VERSION 5.8 ;
BUSBITCHARS "[]" ;
DIVIDERCHAR "/" ;
UNITS
    DATABASE MICRONS 1000 ;
END UNITS

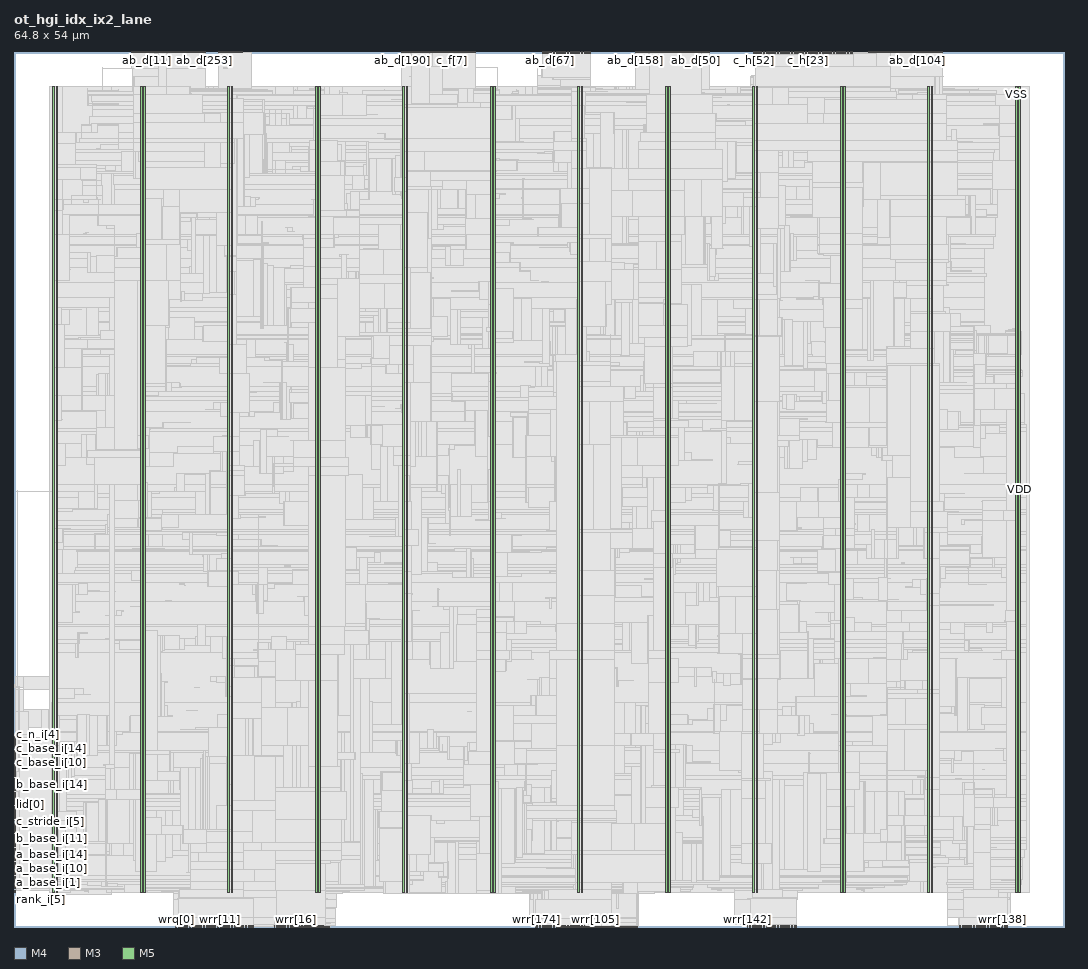
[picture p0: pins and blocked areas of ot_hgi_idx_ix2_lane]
MACRO ot_hgi_idx_ix2_lane
  FOREIGN ot_hgi_idx_ix2_lane 0 0 ;
  CLASS BLOCK ;
  SIZE 64.8 BY 54 ;
  PIN a_base_i[0]
    DIRECTION INPUT ;
    USE SIGNAL ;
    PORT
      LAYER M4 ;
        RECT  0 2.64 0.084 2.664 ;
    END
  END a_base_i[0]
  PIN a_base_i[10]
    DIRECTION INPUT ;
    USE SIGNAL ;
    PORT
      LAYER M4 ;
        RECT  0 3.6 0.084 3.624 ;
    END
  END a_base_i[10]
  PIN a_base_i[11]
    DIRECTION INPUT ;
    USE SIGNAL ;
    PORT
      LAYER M4 ;
        RECT  0 3.696 0.084 3.72 ;
    END
  END a_base_i[11]
  PIN a_base_i[12]
    DIRECTION INPUT ;
    USE SIGNAL ;
    PORT
      LAYER M4 ;
        RECT  0 3.792 0.084 3.816 ;
    END
  END a_base_i[12]
  PIN a_base_i[13]
    DIRECTION INPUT ;
    USE SIGNAL ;
    PORT
      LAYER M4 ;
        RECT  0 3.888 0.084 3.912 ;
    END
  END a_base_i[13]
  PIN a_base_i[14]
    DIRECTION INPUT ;
    USE SIGNAL ;
    PORT
      LAYER M4 ;
        RECT  0 3.984 0.084 4.008 ;
    END
  END a_base_i[14]
  PIN a_base_i[15]
    DIRECTION INPUT ;
    USE SIGNAL ;
    PORT
      LAYER M4 ;
        RECT  0 4.08 0.084 4.104 ;
    END
  END a_base_i[15]
  PIN a_base_i[16]
    DIRECTION INPUT ;
    USE SIGNAL ;
    PORT
      LAYER M4 ;
        RECT  0 4.176 0.084 4.2 ;
    END
  END a_base_i[16]
  PIN a_base_i[17]
    DIRECTION INPUT ;
    USE SIGNAL ;
    PORT
      LAYER M4 ;
        RECT  0 4.272 0.084 4.296 ;
    END
  END a_base_i[17]
  PIN a_base_i[1]
    DIRECTION INPUT ;
    USE SIGNAL ;
    PORT
      LAYER M4 ;
        RECT  0 2.736 0.084 2.76 ;
    END
  END a_base_i[1]
  PIN a_base_i[2]
    DIRECTION INPUT ;
    USE SIGNAL ;
    PORT
      LAYER M4 ;
        RECT  0 2.832 0.084 2.856 ;
    END
  END a_base_i[2]
  PIN a_base_i[3]
    DIRECTION INPUT ;
    USE SIGNAL ;
    PORT
      LAYER M4 ;
        RECT  0 2.928 0.084 2.952 ;
    END
  END a_base_i[3]
  PIN a_base_i[4]
    DIRECTION INPUT ;
    USE SIGNAL ;
    PORT
      LAYER M4 ;
        RECT  0 3.024 0.084 3.048 ;
    END
  END a_base_i[4]
  PIN a_base_i[5]
    DIRECTION INPUT ;
    USE SIGNAL ;
    PORT
      LAYER M4 ;
        RECT  0 3.12 0.084 3.144 ;
    END
  END a_base_i[5]
  PIN a_base_i[6]
    DIRECTION INPUT ;
    USE SIGNAL ;
    PORT
      LAYER M4 ;
        RECT  0 3.216 0.084 3.24 ;
    END
  END a_base_i[6]
  PIN a_base_i[7]
    DIRECTION INPUT ;
    USE SIGNAL ;
    PORT
      LAYER M4 ;
        RECT  0 3.312 0.084 3.336 ;
    END
  END a_base_i[7]
  PIN a_base_i[8]
    DIRECTION INPUT ;
    USE SIGNAL ;
    PORT
      LAYER M4 ;
        RECT  0 3.408 0.084 3.432 ;
    END
  END a_base_i[8]
  PIN a_base_i[9]
    DIRECTION INPUT ;
    USE SIGNAL ;
    PORT
      LAYER M4 ;
        RECT  0 3.504 0.084 3.528 ;
    END
  END a_base_i[9]
  PIN a_cr
    DIRECTION INPUT ;
    USE SIGNAL ;
    PORT
      LAYER M3 ;
        RECT  7.236 53.963 7.254 54 ;
    END
  END a_cr
  PIN a_v
    DIRECTION OUTPUT ;
    USE SIGNAL ;
    PORT
      LAYER M3 ;
        RECT  7.308 53.963 7.326 54 ;
    END
  END a_v
  PIN ab_d[0]
    DIRECTION OUTPUT ;
    USE SIGNAL ;
    PORT
      LAYER M3 ;
        RECT  7.38 53.963 7.398 54 ;
    END
  END ab_d[0]
  PIN ab_d[100]
    DIRECTION OUTPUT ;
    USE SIGNAL ;
    PORT
      LAYER M3 ;
        RECT  55.476 53.963 55.494 54 ;
    END
  END ab_d[100]
  PIN ab_d[101]
    DIRECTION OUTPUT ;
    USE SIGNAL ;
    PORT
      LAYER M3 ;
        RECT  55.548 53.963 55.566 54 ;
    END
  END ab_d[101]
  PIN ab_d[102]
    DIRECTION OUTPUT ;
    USE SIGNAL ;
    PORT
      LAYER M3 ;
        RECT  55.62 53.963 55.638 54 ;
    END
  END ab_d[102]
  PIN ab_d[103]
    DIRECTION OUTPUT ;
    USE SIGNAL ;
    PORT
      LAYER M3 ;
        RECT  55.692 53.963 55.71 54 ;
    END
  END ab_d[103]
  PIN ab_d[104]
    DIRECTION OUTPUT ;
    USE SIGNAL ;
    PORT
      LAYER M3 ;
        RECT  55.764 53.963 55.782 54 ;
    END
  END ab_d[104]
  PIN ab_d[105]
    DIRECTION OUTPUT ;
    USE SIGNAL ;
    PORT
      LAYER M3 ;
        RECT  55.836 53.963 55.854 54 ;
    END
  END ab_d[105]
  PIN ab_d[106]
    DIRECTION OUTPUT ;
    USE SIGNAL ;
    PORT
      LAYER M3 ;
        RECT  55.908 53.963 55.926 54 ;
    END
  END ab_d[106]
  PIN ab_d[107]
    DIRECTION OUTPUT ;
    USE SIGNAL ;
    PORT
      LAYER M3 ;
        RECT  55.98 53.963 55.998 54 ;
    END
  END ab_d[107]
  PIN ab_d[108]
    DIRECTION OUTPUT ;
    USE SIGNAL ;
    PORT
      LAYER M3 ;
        RECT  56.052 53.963 56.07 54 ;
    END
  END ab_d[108]
  PIN ab_d[109]
    DIRECTION OUTPUT ;
    USE SIGNAL ;
    PORT
      LAYER M3 ;
        RECT  56.124 53.963 56.142 54 ;
    END
  END ab_d[109]
  PIN ab_d[10]
    DIRECTION OUTPUT ;
    USE SIGNAL ;
    PORT
      LAYER M3 ;
        RECT  8.1 53.963 8.118 54 ;
    END
  END ab_d[10]
  PIN ab_d[110]
    DIRECTION OUTPUT ;
    USE SIGNAL ;
    PORT
      LAYER M3 ;
        RECT  56.196 53.963 56.214 54 ;
    END
  END ab_d[110]
  PIN ab_d[111]
    DIRECTION OUTPUT ;
    USE SIGNAL ;
    PORT
      LAYER M3 ;
        RECT  56.268 53.963 56.286 54 ;
    END
  END ab_d[111]
  PIN ab_d[112]
    DIRECTION OUTPUT ;
    USE SIGNAL ;
    PORT
      LAYER M3 ;
        RECT  56.34 53.963 56.358 54 ;
    END
  END ab_d[112]
  PIN ab_d[113]
    DIRECTION OUTPUT ;
    USE SIGNAL ;
    PORT
      LAYER M3 ;
        RECT  56.412 53.963 56.43 54 ;
    END
  END ab_d[113]
  PIN ab_d[114]
    DIRECTION OUTPUT ;
    USE SIGNAL ;
    PORT
      LAYER M3 ;
        RECT  56.484 53.963 56.502 54 ;
    END
  END ab_d[114]
  PIN ab_d[115]
    DIRECTION OUTPUT ;
    USE SIGNAL ;
    PORT
      LAYER M3 ;
        RECT  56.556 53.963 56.574 54 ;
    END
  END ab_d[115]
  PIN ab_d[116]
    DIRECTION OUTPUT ;
    USE SIGNAL ;
    PORT
      LAYER M3 ;
        RECT  56.628 53.963 56.646 54 ;
    END
  END ab_d[116]
  PIN ab_d[117]
    DIRECTION OUTPUT ;
    USE SIGNAL ;
    PORT
      LAYER M3 ;
        RECT  56.7 53.963 56.718 54 ;
    END
  END ab_d[117]
  PIN ab_d[118]
    DIRECTION OUTPUT ;
    USE SIGNAL ;
    PORT
      LAYER M3 ;
        RECT  56.772 53.963 56.79 54 ;
    END
  END ab_d[118]
  PIN ab_d[119]
    DIRECTION OUTPUT ;
    USE SIGNAL ;
    PORT
      LAYER M3 ;
        RECT  56.844 53.963 56.862 54 ;
    END
  END ab_d[119]
  PIN ab_d[11]
    DIRECTION OUTPUT ;
    USE SIGNAL ;
    PORT
      LAYER M3 ;
        RECT  8.172 53.963 8.19 54 ;
    END
  END ab_d[11]
  PIN ab_d[120]
    DIRECTION OUTPUT ;
    USE SIGNAL ;
    PORT
      LAYER M3 ;
        RECT  56.916 53.963 56.934 54 ;
    END
  END ab_d[120]
  PIN ab_d[121]
    DIRECTION OUTPUT ;
    USE SIGNAL ;
    PORT
      LAYER M3 ;
        RECT  56.988 53.963 57.006 54 ;
    END
  END ab_d[121]
  PIN ab_d[122]
    DIRECTION OUTPUT ;
    USE SIGNAL ;
    PORT
      LAYER M3 ;
        RECT  57.06 53.963 57.078 54 ;
    END
  END ab_d[122]
  PIN ab_d[123]
    DIRECTION OUTPUT ;
    USE SIGNAL ;
    PORT
      LAYER M3 ;
        RECT  57.132 53.963 57.15 54 ;
    END
  END ab_d[123]
  PIN ab_d[124]
    DIRECTION OUTPUT ;
    USE SIGNAL ;
    PORT
      LAYER M3 ;
        RECT  57.204 53.963 57.222 54 ;
    END
  END ab_d[124]
  PIN ab_d[125]
    DIRECTION OUTPUT ;
    USE SIGNAL ;
    PORT
      LAYER M3 ;
        RECT  57.276 53.963 57.294 54 ;
    END
  END ab_d[125]
  PIN ab_d[126]
    DIRECTION OUTPUT ;
    USE SIGNAL ;
    PORT
      LAYER M3 ;
        RECT  52.74 53.963 52.758 54 ;
    END
  END ab_d[126]
  PIN ab_d[127]
    DIRECTION OUTPUT ;
    USE SIGNAL ;
    PORT
      LAYER M3 ;
        RECT  52.812 53.963 52.83 54 ;
    END
  END ab_d[127]
  PIN ab_d[128]
    DIRECTION OUTPUT ;
    USE SIGNAL ;
    PORT
      LAYER M3 ;
        RECT  52.884 53.963 52.902 54 ;
    END
  END ab_d[128]
  PIN ab_d[129]
    DIRECTION OUTPUT ;
    USE SIGNAL ;
    PORT
      LAYER M3 ;
        RECT  52.956 53.963 52.974 54 ;
    END
  END ab_d[129]
  PIN ab_d[12]
    DIRECTION OUTPUT ;
    USE SIGNAL ;
    PORT
      LAYER M3 ;
        RECT  8.244 53.963 8.262 54 ;
    END
  END ab_d[12]
  PIN ab_d[130]
    DIRECTION OUTPUT ;
    USE SIGNAL ;
    PORT
      LAYER M3 ;
        RECT  53.028 53.963 53.046 54 ;
    END
  END ab_d[130]
  PIN ab_d[131]
    DIRECTION OUTPUT ;
    USE SIGNAL ;
    PORT
      LAYER M3 ;
        RECT  53.1 53.963 53.118 54 ;
    END
  END ab_d[131]
  PIN ab_d[132]
    DIRECTION OUTPUT ;
    USE SIGNAL ;
    PORT
      LAYER M3 ;
        RECT  53.172 53.963 53.19 54 ;
    END
  END ab_d[132]
  PIN ab_d[133]
    DIRECTION OUTPUT ;
    USE SIGNAL ;
    PORT
      LAYER M3 ;
        RECT  53.244 53.963 53.262 54 ;
    END
  END ab_d[133]
  PIN ab_d[134]
    DIRECTION OUTPUT ;
    USE SIGNAL ;
    PORT
      LAYER M3 ;
        RECT  53.316 53.963 53.334 54 ;
    END
  END ab_d[134]
  PIN ab_d[135]
    DIRECTION OUTPUT ;
    USE SIGNAL ;
    PORT
      LAYER M3 ;
        RECT  53.388 53.963 53.406 54 ;
    END
  END ab_d[135]
  PIN ab_d[136]
    DIRECTION OUTPUT ;
    USE SIGNAL ;
    PORT
      LAYER M3 ;
        RECT  53.46 53.963 53.478 54 ;
    END
  END ab_d[136]
  PIN ab_d[137]
    DIRECTION OUTPUT ;
    USE SIGNAL ;
    PORT
      LAYER M3 ;
        RECT  53.532 53.963 53.55 54 ;
    END
  END ab_d[137]
  PIN ab_d[138]
    DIRECTION OUTPUT ;
    USE SIGNAL ;
    PORT
      LAYER M3 ;
        RECT  53.604 53.963 53.622 54 ;
    END
  END ab_d[138]
  PIN ab_d[139]
    DIRECTION OUTPUT ;
    USE SIGNAL ;
    PORT
      LAYER M3 ;
        RECT  53.676 53.963 53.694 54 ;
    END
  END ab_d[139]
  PIN ab_d[13]
    DIRECTION OUTPUT ;
    USE SIGNAL ;
    PORT
      LAYER M3 ;
        RECT  8.316 53.963 8.334 54 ;
    END
  END ab_d[13]
  PIN ab_d[140]
    DIRECTION OUTPUT ;
    USE SIGNAL ;
    PORT
      LAYER M3 ;
        RECT  53.748 53.963 53.766 54 ;
    END
  END ab_d[140]
  PIN ab_d[141]
    DIRECTION OUTPUT ;
    USE SIGNAL ;
    PORT
      LAYER M3 ;
        RECT  53.82 53.963 53.838 54 ;
    END
  END ab_d[141]
  PIN ab_d[142]
    DIRECTION OUTPUT ;
    USE SIGNAL ;
    PORT
      LAYER M3 ;
        RECT  53.892 53.963 53.91 54 ;
    END
  END ab_d[142]
  PIN ab_d[143]
    DIRECTION OUTPUT ;
    USE SIGNAL ;
    PORT
      LAYER M3 ;
        RECT  53.964 53.963 53.982 54 ;
    END
  END ab_d[143]
  PIN ab_d[144]
    DIRECTION OUTPUT ;
    USE SIGNAL ;
    PORT
      LAYER M3 ;
        RECT  54.036 53.963 54.054 54 ;
    END
  END ab_d[144]
  PIN ab_d[145]
    DIRECTION OUTPUT ;
    USE SIGNAL ;
    PORT
      LAYER M3 ;
        RECT  54.108 53.963 54.126 54 ;
    END
  END ab_d[145]
  PIN ab_d[146]
    DIRECTION OUTPUT ;
    USE SIGNAL ;
    PORT
      LAYER M3 ;
        RECT  54.18 53.963 54.198 54 ;
    END
  END ab_d[146]
  PIN ab_d[147]
    DIRECTION OUTPUT ;
    USE SIGNAL ;
    PORT
      LAYER M3 ;
        RECT  54.252 53.963 54.27 54 ;
    END
  END ab_d[147]
  PIN ab_d[148]
    DIRECTION OUTPUT ;
    USE SIGNAL ;
    PORT
      LAYER M3 ;
        RECT  54.324 53.963 54.342 54 ;
    END
  END ab_d[148]
  PIN ab_d[149]
    DIRECTION OUTPUT ;
    USE SIGNAL ;
    PORT
      LAYER M3 ;
        RECT  54.396 53.963 54.414 54 ;
    END
  END ab_d[149]
  PIN ab_d[14]
    DIRECTION OUTPUT ;
    USE SIGNAL ;
    PORT
      LAYER M3 ;
        RECT  8.388 53.963 8.406 54 ;
    END
  END ab_d[14]
  PIN ab_d[150]
    DIRECTION OUTPUT ;
    USE SIGNAL ;
    PORT
      LAYER M3 ;
        RECT  54.468 53.963 54.486 54 ;
    END
  END ab_d[150]
  PIN ab_d[151]
    DIRECTION OUTPUT ;
    USE SIGNAL ;
    PORT
      LAYER M3 ;
        RECT  54.54 53.963 54.558 54 ;
    END
  END ab_d[151]
  PIN ab_d[152]
    DIRECTION OUTPUT ;
    USE SIGNAL ;
    PORT
      LAYER M3 ;
        RECT  54.612 53.963 54.63 54 ;
    END
  END ab_d[152]
  PIN ab_d[153]
    DIRECTION OUTPUT ;
    USE SIGNAL ;
    PORT
      LAYER M3 ;
        RECT  54.684 53.963 54.702 54 ;
    END
  END ab_d[153]
  PIN ab_d[154]
    DIRECTION OUTPUT ;
    USE SIGNAL ;
    PORT
      LAYER M3 ;
        RECT  54.756 53.963 54.774 54 ;
    END
  END ab_d[154]
  PIN ab_d[155]
    DIRECTION OUTPUT ;
    USE SIGNAL ;
    PORT
      LAYER M3 ;
        RECT  54.828 53.963 54.846 54 ;
    END
  END ab_d[155]
  PIN ab_d[156]
    DIRECTION OUTPUT ;
    USE SIGNAL ;
    PORT
      LAYER M3 ;
        RECT  54.9 53.963 54.918 54 ;
    END
  END ab_d[156]
  PIN ab_d[157]
    DIRECTION OUTPUT ;
    USE SIGNAL ;
    PORT
      LAYER M3 ;
        RECT  54.972 53.963 54.99 54 ;
    END
  END ab_d[157]
  PIN ab_d[158]
    DIRECTION OUTPUT ;
    USE SIGNAL ;
    PORT
      LAYER M3 ;
        RECT  38.34 53.963 38.358 54 ;
    END
  END ab_d[158]
  PIN ab_d[159]
    DIRECTION OUTPUT ;
    USE SIGNAL ;
    PORT
      LAYER M3 ;
        RECT  38.412 53.963 38.43 54 ;
    END
  END ab_d[159]
  PIN ab_d[15]
    DIRECTION OUTPUT ;
    USE SIGNAL ;
    PORT
      LAYER M3 ;
        RECT  8.46 53.963 8.478 54 ;
    END
  END ab_d[15]
  PIN ab_d[160]
    DIRECTION OUTPUT ;
    USE SIGNAL ;
    PORT
      LAYER M3 ;
        RECT  38.484 53.963 38.502 54 ;
    END
  END ab_d[160]
  PIN ab_d[161]
    DIRECTION OUTPUT ;
    USE SIGNAL ;
    PORT
      LAYER M3 ;
        RECT  38.556 53.963 38.574 54 ;
    END
  END ab_d[161]
  PIN ab_d[162]
    DIRECTION OUTPUT ;
    USE SIGNAL ;
    PORT
      LAYER M3 ;
        RECT  38.628 53.963 38.646 54 ;
    END
  END ab_d[162]
  PIN ab_d[163]
    DIRECTION OUTPUT ;
    USE SIGNAL ;
    PORT
      LAYER M3 ;
        RECT  38.7 53.963 38.718 54 ;
    END
  END ab_d[163]
  PIN ab_d[164]
    DIRECTION OUTPUT ;
    USE SIGNAL ;
    PORT
      LAYER M3 ;
        RECT  38.772 53.963 38.79 54 ;
    END
  END ab_d[164]
  PIN ab_d[165]
    DIRECTION OUTPUT ;
    USE SIGNAL ;
    PORT
      LAYER M3 ;
        RECT  38.844 53.963 38.862 54 ;
    END
  END ab_d[165]
  PIN ab_d[166]
    DIRECTION OUTPUT ;
    USE SIGNAL ;
    PORT
      LAYER M3 ;
        RECT  38.916 53.963 38.934 54 ;
    END
  END ab_d[166]
  PIN ab_d[167]
    DIRECTION OUTPUT ;
    USE SIGNAL ;
    PORT
      LAYER M3 ;
        RECT  38.988 53.963 39.006 54 ;
    END
  END ab_d[167]
  PIN ab_d[168]
    DIRECTION OUTPUT ;
    USE SIGNAL ;
    PORT
      LAYER M3 ;
        RECT  39.06 53.963 39.078 54 ;
    END
  END ab_d[168]
  PIN ab_d[169]
    DIRECTION OUTPUT ;
    USE SIGNAL ;
    PORT
      LAYER M3 ;
        RECT  39.132 53.963 39.15 54 ;
    END
  END ab_d[169]
  PIN ab_d[16]
    DIRECTION OUTPUT ;
    USE SIGNAL ;
    PORT
      LAYER M3 ;
        RECT  8.532 53.963 8.55 54 ;
    END
  END ab_d[16]
  PIN ab_d[170]
    DIRECTION OUTPUT ;
    USE SIGNAL ;
    PORT
      LAYER M3 ;
        RECT  39.204 53.963 39.222 54 ;
    END
  END ab_d[170]
  PIN ab_d[171]
    DIRECTION OUTPUT ;
    USE SIGNAL ;
    PORT
      LAYER M3 ;
        RECT  39.276 53.963 39.294 54 ;
    END
  END ab_d[171]
  PIN ab_d[172]
    DIRECTION OUTPUT ;
    USE SIGNAL ;
    PORT
      LAYER M3 ;
        RECT  39.348 53.963 39.366 54 ;
    END
  END ab_d[172]
  PIN ab_d[173]
    DIRECTION OUTPUT ;
    USE SIGNAL ;
    PORT
      LAYER M3 ;
        RECT  39.42 53.963 39.438 54 ;
    END
  END ab_d[173]
  PIN ab_d[174]
    DIRECTION OUTPUT ;
    USE SIGNAL ;
    PORT
      LAYER M3 ;
        RECT  39.492 53.963 39.51 54 ;
    END
  END ab_d[174]
  PIN ab_d[175]
    DIRECTION OUTPUT ;
    USE SIGNAL ;
    PORT
      LAYER M3 ;
        RECT  39.564 53.963 39.582 54 ;
    END
  END ab_d[175]
  PIN ab_d[176]
    DIRECTION OUTPUT ;
    USE SIGNAL ;
    PORT
      LAYER M3 ;
        RECT  39.636 53.963 39.654 54 ;
    END
  END ab_d[176]
  PIN ab_d[177]
    DIRECTION OUTPUT ;
    USE SIGNAL ;
    PORT
      LAYER M3 ;
        RECT  39.708 53.963 39.726 54 ;
    END
  END ab_d[177]
  PIN ab_d[178]
    DIRECTION OUTPUT ;
    USE SIGNAL ;
    PORT
      LAYER M3 ;
        RECT  39.78 53.963 39.798 54 ;
    END
  END ab_d[178]
  PIN ab_d[179]
    DIRECTION OUTPUT ;
    USE SIGNAL ;
    PORT
      LAYER M3 ;
        RECT  39.852 53.963 39.87 54 ;
    END
  END ab_d[179]
  PIN ab_d[17]
    DIRECTION OUTPUT ;
    USE SIGNAL ;
    PORT
      LAYER M3 ;
        RECT  8.604 53.963 8.622 54 ;
    END
  END ab_d[17]
  PIN ab_d[180]
    DIRECTION OUTPUT ;
    USE SIGNAL ;
    PORT
      LAYER M3 ;
        RECT  39.924 53.963 39.942 54 ;
    END
  END ab_d[180]
  PIN ab_d[181]
    DIRECTION OUTPUT ;
    USE SIGNAL ;
    PORT
      LAYER M3 ;
        RECT  39.996 53.963 40.014 54 ;
    END
  END ab_d[181]
  PIN ab_d[182]
    DIRECTION OUTPUT ;
    USE SIGNAL ;
    PORT
      LAYER M3 ;
        RECT  40.068 53.963 40.086 54 ;
    END
  END ab_d[182]
  PIN ab_d[183]
    DIRECTION OUTPUT ;
    USE SIGNAL ;
    PORT
      LAYER M3 ;
        RECT  40.14 53.963 40.158 54 ;
    END
  END ab_d[183]
  PIN ab_d[184]
    DIRECTION OUTPUT ;
    USE SIGNAL ;
    PORT
      LAYER M3 ;
        RECT  40.212 53.963 40.23 54 ;
    END
  END ab_d[184]
  PIN ab_d[185]
    DIRECTION OUTPUT ;
    USE SIGNAL ;
    PORT
      LAYER M3 ;
        RECT  40.284 53.963 40.302 54 ;
    END
  END ab_d[185]
  PIN ab_d[186]
    DIRECTION OUTPUT ;
    USE SIGNAL ;
    PORT
      LAYER M3 ;
        RECT  40.356 53.963 40.374 54 ;
    END
  END ab_d[186]
  PIN ab_d[187]
    DIRECTION OUTPUT ;
    USE SIGNAL ;
    PORT
      LAYER M3 ;
        RECT  40.428 53.963 40.446 54 ;
    END
  END ab_d[187]
  PIN ab_d[188]
    DIRECTION OUTPUT ;
    USE SIGNAL ;
    PORT
      LAYER M3 ;
        RECT  40.5 53.963 40.518 54 ;
    END
  END ab_d[188]
  PIN ab_d[189]
    DIRECTION OUTPUT ;
    USE SIGNAL ;
    PORT
      LAYER M3 ;
        RECT  40.572 53.963 40.59 54 ;
    END
  END ab_d[189]
  PIN ab_d[18]
    DIRECTION OUTPUT ;
    USE SIGNAL ;
    PORT
      LAYER M3 ;
        RECT  8.676 53.963 8.694 54 ;
    END
  END ab_d[18]
  PIN ab_d[190]
    DIRECTION OUTPUT ;
    USE SIGNAL ;
    PORT
      LAYER M3 ;
        RECT  23.94 53.963 23.958 54 ;
    END
  END ab_d[190]
  PIN ab_d[191]
    DIRECTION OUTPUT ;
    USE SIGNAL ;
    PORT
      LAYER M3 ;
        RECT  24.012 53.963 24.03 54 ;
    END
  END ab_d[191]
  PIN ab_d[192]
    DIRECTION OUTPUT ;
    USE SIGNAL ;
    PORT
      LAYER M3 ;
        RECT  24.084 53.963 24.102 54 ;
    END
  END ab_d[192]
  PIN ab_d[193]
    DIRECTION OUTPUT ;
    USE SIGNAL ;
    PORT
      LAYER M3 ;
        RECT  24.156 53.963 24.174 54 ;
    END
  END ab_d[193]
  PIN ab_d[194]
    DIRECTION OUTPUT ;
    USE SIGNAL ;
    PORT
      LAYER M3 ;
        RECT  24.228 53.963 24.246 54 ;
    END
  END ab_d[194]
  PIN ab_d[195]
    DIRECTION OUTPUT ;
    USE SIGNAL ;
    PORT
      LAYER M3 ;
        RECT  24.3 53.963 24.318 54 ;
    END
  END ab_d[195]
  PIN ab_d[196]
    DIRECTION OUTPUT ;
    USE SIGNAL ;
    PORT
      LAYER M3 ;
        RECT  24.372 53.963 24.39 54 ;
    END
  END ab_d[196]
  PIN ab_d[197]
    DIRECTION OUTPUT ;
    USE SIGNAL ;
    PORT
      LAYER M3 ;
        RECT  24.444 53.963 24.462 54 ;
    END
  END ab_d[197]
  PIN ab_d[198]
    DIRECTION OUTPUT ;
    USE SIGNAL ;
    PORT
      LAYER M3 ;
        RECT  24.516 53.963 24.534 54 ;
    END
  END ab_d[198]
  PIN ab_d[199]
    DIRECTION OUTPUT ;
    USE SIGNAL ;
    PORT
      LAYER M3 ;
        RECT  24.588 53.963 24.606 54 ;
    END
  END ab_d[199]
  PIN ab_d[19]
    DIRECTION OUTPUT ;
    USE SIGNAL ;
    PORT
      LAYER M3 ;
        RECT  8.748 53.963 8.766 54 ;
    END
  END ab_d[19]
  PIN ab_d[1]
    DIRECTION OUTPUT ;
    USE SIGNAL ;
    PORT
      LAYER M3 ;
        RECT  7.452 53.963 7.47 54 ;
    END
  END ab_d[1]
  PIN ab_d[200]
    DIRECTION OUTPUT ;
    USE SIGNAL ;
    PORT
      LAYER M3 ;
        RECT  24.66 53.963 24.678 54 ;
    END
  END ab_d[200]
  PIN ab_d[201]
    DIRECTION OUTPUT ;
    USE SIGNAL ;
    PORT
      LAYER M3 ;
        RECT  24.732 53.963 24.75 54 ;
    END
  END ab_d[201]
  PIN ab_d[202]
    DIRECTION OUTPUT ;
    USE SIGNAL ;
    PORT
      LAYER M3 ;
        RECT  24.804 53.963 24.822 54 ;
    END
  END ab_d[202]
  PIN ab_d[203]
    DIRECTION OUTPUT ;
    USE SIGNAL ;
    PORT
      LAYER M3 ;
        RECT  24.876 53.963 24.894 54 ;
    END
  END ab_d[203]
  PIN ab_d[204]
    DIRECTION OUTPUT ;
    USE SIGNAL ;
    PORT
      LAYER M3 ;
        RECT  24.948 53.963 24.966 54 ;
    END
  END ab_d[204]
  PIN ab_d[205]
    DIRECTION OUTPUT ;
    USE SIGNAL ;
    PORT
      LAYER M3 ;
        RECT  25.02 53.963 25.038 54 ;
    END
  END ab_d[205]
  PIN ab_d[206]
    DIRECTION OUTPUT ;
    USE SIGNAL ;
    PORT
      LAYER M3 ;
        RECT  25.092 53.963 25.11 54 ;
    END
  END ab_d[206]
  PIN ab_d[207]
    DIRECTION OUTPUT ;
    USE SIGNAL ;
    PORT
      LAYER M3 ;
        RECT  25.164 53.963 25.182 54 ;
    END
  END ab_d[207]
  PIN ab_d[208]
    DIRECTION OUTPUT ;
    USE SIGNAL ;
    PORT
      LAYER M3 ;
        RECT  25.236 53.963 25.254 54 ;
    END
  END ab_d[208]
  PIN ab_d[209]
    DIRECTION OUTPUT ;
    USE SIGNAL ;
    PORT
      LAYER M3 ;
        RECT  25.308 53.963 25.326 54 ;
    END
  END ab_d[209]
  PIN ab_d[20]
    DIRECTION OUTPUT ;
    USE SIGNAL ;
    PORT
      LAYER M3 ;
        RECT  8.82 53.963 8.838 54 ;
    END
  END ab_d[20]
  PIN ab_d[210]
    DIRECTION OUTPUT ;
    USE SIGNAL ;
    PORT
      LAYER M3 ;
        RECT  25.38 53.963 25.398 54 ;
    END
  END ab_d[210]
  PIN ab_d[211]
    DIRECTION OUTPUT ;
    USE SIGNAL ;
    PORT
      LAYER M3 ;
        RECT  25.452 53.963 25.47 54 ;
    END
  END ab_d[211]
  PIN ab_d[212]
    DIRECTION OUTPUT ;
    USE SIGNAL ;
    PORT
      LAYER M3 ;
        RECT  25.524 53.963 25.542 54 ;
    END
  END ab_d[212]
  PIN ab_d[213]
    DIRECTION OUTPUT ;
    USE SIGNAL ;
    PORT
      LAYER M3 ;
        RECT  25.596 53.963 25.614 54 ;
    END
  END ab_d[213]
  PIN ab_d[214]
    DIRECTION OUTPUT ;
    USE SIGNAL ;
    PORT
      LAYER M3 ;
        RECT  25.668 53.963 25.686 54 ;
    END
  END ab_d[214]
  PIN ab_d[215]
    DIRECTION OUTPUT ;
    USE SIGNAL ;
    PORT
      LAYER M3 ;
        RECT  25.74 53.963 25.758 54 ;
    END
  END ab_d[215]
  PIN ab_d[216]
    DIRECTION OUTPUT ;
    USE SIGNAL ;
    PORT
      LAYER M3 ;
        RECT  25.812 53.963 25.83 54 ;
    END
  END ab_d[216]
  PIN ab_d[217]
    DIRECTION OUTPUT ;
    USE SIGNAL ;
    PORT
      LAYER M3 ;
        RECT  25.884 53.963 25.902 54 ;
    END
  END ab_d[217]
  PIN ab_d[218]
    DIRECTION OUTPUT ;
    USE SIGNAL ;
    PORT
      LAYER M3 ;
        RECT  25.956 53.963 25.974 54 ;
    END
  END ab_d[218]
  PIN ab_d[219]
    DIRECTION OUTPUT ;
    USE SIGNAL ;
    PORT
      LAYER M3 ;
        RECT  26.028 53.963 26.046 54 ;
    END
  END ab_d[219]
  PIN ab_d[21]
    DIRECTION OUTPUT ;
    USE SIGNAL ;
    PORT
      LAYER M3 ;
        RECT  8.892 53.963 8.91 54 ;
    END
  END ab_d[21]
  PIN ab_d[220]
    DIRECTION OUTPUT ;
    USE SIGNAL ;
    PORT
      LAYER M3 ;
        RECT  26.1 53.963 26.118 54 ;
    END
  END ab_d[220]
  PIN ab_d[221]
    DIRECTION OUTPUT ;
    USE SIGNAL ;
    PORT
      LAYER M3 ;
        RECT  26.172 53.963 26.19 54 ;
    END
  END ab_d[221]
  PIN ab_d[222]
    DIRECTION OUTPUT ;
    USE SIGNAL ;
    PORT
      LAYER M3 ;
        RECT  9.54 53.963 9.558 54 ;
    END
  END ab_d[222]
  PIN ab_d[223]
    DIRECTION OUTPUT ;
    USE SIGNAL ;
    PORT
      LAYER M3 ;
        RECT  9.612 53.963 9.63 54 ;
    END
  END ab_d[223]
  PIN ab_d[224]
    DIRECTION OUTPUT ;
    USE SIGNAL ;
    PORT
      LAYER M3 ;
        RECT  9.684 53.963 9.702 54 ;
    END
  END ab_d[224]
  PIN ab_d[225]
    DIRECTION OUTPUT ;
    USE SIGNAL ;
    PORT
      LAYER M3 ;
        RECT  9.756 53.963 9.774 54 ;
    END
  END ab_d[225]
  PIN ab_d[226]
    DIRECTION OUTPUT ;
    USE SIGNAL ;
    PORT
      LAYER M3 ;
        RECT  9.828 53.963 9.846 54 ;
    END
  END ab_d[226]
  PIN ab_d[227]
    DIRECTION OUTPUT ;
    USE SIGNAL ;
    PORT
      LAYER M3 ;
        RECT  9.9 53.963 9.918 54 ;
    END
  END ab_d[227]
  PIN ab_d[228]
    DIRECTION OUTPUT ;
    USE SIGNAL ;
    PORT
      LAYER M3 ;
        RECT  9.972 53.963 9.99 54 ;
    END
  END ab_d[228]
  PIN ab_d[229]
    DIRECTION OUTPUT ;
    USE SIGNAL ;
    PORT
      LAYER M3 ;
        RECT  10.044 53.963 10.062 54 ;
    END
  END ab_d[229]
  PIN ab_d[22]
    DIRECTION OUTPUT ;
    USE SIGNAL ;
    PORT
      LAYER M3 ;
        RECT  8.964 53.963 8.982 54 ;
    END
  END ab_d[22]
  PIN ab_d[230]
    DIRECTION OUTPUT ;
    USE SIGNAL ;
    PORT
      LAYER M3 ;
        RECT  10.116 53.963 10.134 54 ;
    END
  END ab_d[230]
  PIN ab_d[231]
    DIRECTION OUTPUT ;
    USE SIGNAL ;
    PORT
      LAYER M3 ;
        RECT  10.188 53.963 10.206 54 ;
    END
  END ab_d[231]
  PIN ab_d[232]
    DIRECTION OUTPUT ;
    USE SIGNAL ;
    PORT
      LAYER M3 ;
        RECT  10.26 53.963 10.278 54 ;
    END
  END ab_d[232]
  PIN ab_d[233]
    DIRECTION OUTPUT ;
    USE SIGNAL ;
    PORT
      LAYER M3 ;
        RECT  10.332 53.963 10.35 54 ;
    END
  END ab_d[233]
  PIN ab_d[234]
    DIRECTION OUTPUT ;
    USE SIGNAL ;
    PORT
      LAYER M3 ;
        RECT  10.404 53.963 10.422 54 ;
    END
  END ab_d[234]
  PIN ab_d[235]
    DIRECTION OUTPUT ;
    USE SIGNAL ;
    PORT
      LAYER M3 ;
        RECT  10.476 53.963 10.494 54 ;
    END
  END ab_d[235]
  PIN ab_d[236]
    DIRECTION OUTPUT ;
    USE SIGNAL ;
    PORT
      LAYER M3 ;
        RECT  10.548 53.963 10.566 54 ;
    END
  END ab_d[236]
  PIN ab_d[237]
    DIRECTION OUTPUT ;
    USE SIGNAL ;
    PORT
      LAYER M3 ;
        RECT  10.62 53.963 10.638 54 ;
    END
  END ab_d[237]
  PIN ab_d[238]
    DIRECTION OUTPUT ;
    USE SIGNAL ;
    PORT
      LAYER M3 ;
        RECT  10.692 53.963 10.71 54 ;
    END
  END ab_d[238]
  PIN ab_d[239]
    DIRECTION OUTPUT ;
    USE SIGNAL ;
    PORT
      LAYER M3 ;
        RECT  10.764 53.963 10.782 54 ;
    END
  END ab_d[239]
  PIN ab_d[23]
    DIRECTION OUTPUT ;
    USE SIGNAL ;
    PORT
      LAYER M3 ;
        RECT  9.036 53.963 9.054 54 ;
    END
  END ab_d[23]
  PIN ab_d[240]
    DIRECTION OUTPUT ;
    USE SIGNAL ;
    PORT
      LAYER M3 ;
        RECT  10.836 53.963 10.854 54 ;
    END
  END ab_d[240]
  PIN ab_d[241]
    DIRECTION OUTPUT ;
    USE SIGNAL ;
    PORT
      LAYER M3 ;
        RECT  10.908 53.963 10.926 54 ;
    END
  END ab_d[241]
  PIN ab_d[242]
    DIRECTION OUTPUT ;
    USE SIGNAL ;
    PORT
      LAYER M3 ;
        RECT  10.98 53.963 10.998 54 ;
    END
  END ab_d[242]
  PIN ab_d[243]
    DIRECTION OUTPUT ;
    USE SIGNAL ;
    PORT
      LAYER M3 ;
        RECT  11.052 53.963 11.07 54 ;
    END
  END ab_d[243]
  PIN ab_d[244]
    DIRECTION OUTPUT ;
    USE SIGNAL ;
    PORT
      LAYER M3 ;
        RECT  11.124 53.963 11.142 54 ;
    END
  END ab_d[244]
  PIN ab_d[245]
    DIRECTION OUTPUT ;
    USE SIGNAL ;
    PORT
      LAYER M3 ;
        RECT  11.196 53.963 11.214 54 ;
    END
  END ab_d[245]
  PIN ab_d[246]
    DIRECTION OUTPUT ;
    USE SIGNAL ;
    PORT
      LAYER M3 ;
        RECT  11.268 53.963 11.286 54 ;
    END
  END ab_d[246]
  PIN ab_d[247]
    DIRECTION OUTPUT ;
    USE SIGNAL ;
    PORT
      LAYER M3 ;
        RECT  11.34 53.963 11.358 54 ;
    END
  END ab_d[247]
  PIN ab_d[248]
    DIRECTION OUTPUT ;
    USE SIGNAL ;
    PORT
      LAYER M3 ;
        RECT  11.412 53.963 11.43 54 ;
    END
  END ab_d[248]
  PIN ab_d[249]
    DIRECTION OUTPUT ;
    USE SIGNAL ;
    PORT
      LAYER M3 ;
        RECT  11.484 53.963 11.502 54 ;
    END
  END ab_d[249]
  PIN ab_d[24]
    DIRECTION OUTPUT ;
    USE SIGNAL ;
    PORT
      LAYER M3 ;
        RECT  9.108 53.963 9.126 54 ;
    END
  END ab_d[24]
  PIN ab_d[250]
    DIRECTION OUTPUT ;
    USE SIGNAL ;
    PORT
      LAYER M3 ;
        RECT  11.556 53.963 11.574 54 ;
    END
  END ab_d[250]
  PIN ab_d[251]
    DIRECTION OUTPUT ;
    USE SIGNAL ;
    PORT
      LAYER M3 ;
        RECT  11.628 53.963 11.646 54 ;
    END
  END ab_d[251]
  PIN ab_d[252]
    DIRECTION OUTPUT ;
    USE SIGNAL ;
    PORT
      LAYER M3 ;
        RECT  11.7 53.963 11.718 54 ;
    END
  END ab_d[252]
  PIN ab_d[253]
    DIRECTION OUTPUT ;
    USE SIGNAL ;
    PORT
      LAYER M3 ;
        RECT  11.772 53.963 11.79 54 ;
    END
  END ab_d[253]
  PIN ab_d[254]
    DIRECTION OUTPUT ;
    USE SIGNAL ;
    PORT
      LAYER M3 ;
        RECT  26.244 53.963 26.262 54 ;
    END
  END ab_d[254]
  PIN ab_d[255]
    DIRECTION OUTPUT ;
    USE SIGNAL ;
    PORT
      LAYER M3 ;
        RECT  26.316 53.963 26.334 54 ;
    END
  END ab_d[255]
  PIN ab_d[25]
    DIRECTION OUTPUT ;
    USE SIGNAL ;
    PORT
      LAYER M3 ;
        RECT  9.18 53.963 9.198 54 ;
    END
  END ab_d[25]
  PIN ab_d[26]
    DIRECTION OUTPUT ;
    USE SIGNAL ;
    PORT
      LAYER M3 ;
        RECT  9.252 53.963 9.27 54 ;
    END
  END ab_d[26]
  PIN ab_d[27]
    DIRECTION OUTPUT ;
    USE SIGNAL ;
    PORT
      LAYER M3 ;
        RECT  9.324 53.963 9.342 54 ;
    END
  END ab_d[27]
  PIN ab_d[28]
    DIRECTION OUTPUT ;
    USE SIGNAL ;
    PORT
      LAYER M3 ;
        RECT  9.396 53.963 9.414 54 ;
    END
  END ab_d[28]
  PIN ab_d[29]
    DIRECTION OUTPUT ;
    USE SIGNAL ;
    PORT
      LAYER M3 ;
        RECT  9.468 53.963 9.486 54 ;
    END
  END ab_d[29]
  PIN ab_d[2]
    DIRECTION OUTPUT ;
    USE SIGNAL ;
    PORT
      LAYER M3 ;
        RECT  7.524 53.963 7.542 54 ;
    END
  END ab_d[2]
  PIN ab_d[30]
    DIRECTION OUTPUT ;
    USE SIGNAL ;
    PORT
      LAYER M3 ;
        RECT  40.644 53.963 40.662 54 ;
    END
  END ab_d[30]
  PIN ab_d[31]
    DIRECTION OUTPUT ;
    USE SIGNAL ;
    PORT
      LAYER M3 ;
        RECT  40.716 53.963 40.734 54 ;
    END
  END ab_d[31]
  PIN ab_d[32]
    DIRECTION OUTPUT ;
    USE SIGNAL ;
    PORT
      LAYER M3 ;
        RECT  40.788 53.963 40.806 54 ;
    END
  END ab_d[32]
  PIN ab_d[33]
    DIRECTION OUTPUT ;
    USE SIGNAL ;
    PORT
      LAYER M3 ;
        RECT  40.86 53.963 40.878 54 ;
    END
  END ab_d[33]
  PIN ab_d[34]
    DIRECTION OUTPUT ;
    USE SIGNAL ;
    PORT
      LAYER M3 ;
        RECT  40.932 53.963 40.95 54 ;
    END
  END ab_d[34]
  PIN ab_d[35]
    DIRECTION OUTPUT ;
    USE SIGNAL ;
    PORT
      LAYER M3 ;
        RECT  41.004 53.963 41.022 54 ;
    END
  END ab_d[35]
  PIN ab_d[36]
    DIRECTION OUTPUT ;
    USE SIGNAL ;
    PORT
      LAYER M3 ;
        RECT  41.076 53.963 41.094 54 ;
    END
  END ab_d[36]
  PIN ab_d[37]
    DIRECTION OUTPUT ;
    USE SIGNAL ;
    PORT
      LAYER M3 ;
        RECT  41.148 53.963 41.166 54 ;
    END
  END ab_d[37]
  PIN ab_d[38]
    DIRECTION OUTPUT ;
    USE SIGNAL ;
    PORT
      LAYER M3 ;
        RECT  41.22 53.963 41.238 54 ;
    END
  END ab_d[38]
  PIN ab_d[39]
    DIRECTION OUTPUT ;
    USE SIGNAL ;
    PORT
      LAYER M3 ;
        RECT  41.292 53.963 41.31 54 ;
    END
  END ab_d[39]
  PIN ab_d[3]
    DIRECTION OUTPUT ;
    USE SIGNAL ;
    PORT
      LAYER M3 ;
        RECT  7.596 53.963 7.614 54 ;
    END
  END ab_d[3]
  PIN ab_d[40]
    DIRECTION OUTPUT ;
    USE SIGNAL ;
    PORT
      LAYER M3 ;
        RECT  41.364 53.963 41.382 54 ;
    END
  END ab_d[40]
  PIN ab_d[41]
    DIRECTION OUTPUT ;
    USE SIGNAL ;
    PORT
      LAYER M3 ;
        RECT  41.436 53.963 41.454 54 ;
    END
  END ab_d[41]
  PIN ab_d[42]
    DIRECTION OUTPUT ;
    USE SIGNAL ;
    PORT
      LAYER M3 ;
        RECT  41.508 53.963 41.526 54 ;
    END
  END ab_d[42]
  PIN ab_d[43]
    DIRECTION OUTPUT ;
    USE SIGNAL ;
    PORT
      LAYER M3 ;
        RECT  41.58 53.963 41.598 54 ;
    END
  END ab_d[43]
  PIN ab_d[44]
    DIRECTION OUTPUT ;
    USE SIGNAL ;
    PORT
      LAYER M3 ;
        RECT  41.652 53.963 41.67 54 ;
    END
  END ab_d[44]
  PIN ab_d[45]
    DIRECTION OUTPUT ;
    USE SIGNAL ;
    PORT
      LAYER M3 ;
        RECT  41.724 53.963 41.742 54 ;
    END
  END ab_d[45]
  PIN ab_d[46]
    DIRECTION OUTPUT ;
    USE SIGNAL ;
    PORT
      LAYER M3 ;
        RECT  41.796 53.963 41.814 54 ;
    END
  END ab_d[46]
  PIN ab_d[47]
    DIRECTION OUTPUT ;
    USE SIGNAL ;
    PORT
      LAYER M3 ;
        RECT  41.868 53.963 41.886 54 ;
    END
  END ab_d[47]
  PIN ab_d[48]
    DIRECTION OUTPUT ;
    USE SIGNAL ;
    PORT
      LAYER M3 ;
        RECT  41.94 53.963 41.958 54 ;
    END
  END ab_d[48]
  PIN ab_d[49]
    DIRECTION OUTPUT ;
    USE SIGNAL ;
    PORT
      LAYER M3 ;
        RECT  42.012 53.963 42.03 54 ;
    END
  END ab_d[49]
  PIN ab_d[4]
    DIRECTION OUTPUT ;
    USE SIGNAL ;
    PORT
      LAYER M3 ;
        RECT  7.668 53.963 7.686 54 ;
    END
  END ab_d[4]
  PIN ab_d[50]
    DIRECTION OUTPUT ;
    USE SIGNAL ;
    PORT
      LAYER M3 ;
        RECT  42.084 53.963 42.102 54 ;
    END
  END ab_d[50]
  PIN ab_d[51]
    DIRECTION OUTPUT ;
    USE SIGNAL ;
    PORT
      LAYER M3 ;
        RECT  42.156 53.963 42.174 54 ;
    END
  END ab_d[51]
  PIN ab_d[52]
    DIRECTION OUTPUT ;
    USE SIGNAL ;
    PORT
      LAYER M3 ;
        RECT  42.228 53.963 42.246 54 ;
    END
  END ab_d[52]
  PIN ab_d[53]
    DIRECTION OUTPUT ;
    USE SIGNAL ;
    PORT
      LAYER M3 ;
        RECT  42.3 53.963 42.318 54 ;
    END
  END ab_d[53]
  PIN ab_d[54]
    DIRECTION OUTPUT ;
    USE SIGNAL ;
    PORT
      LAYER M3 ;
        RECT  42.372 53.963 42.39 54 ;
    END
  END ab_d[54]
  PIN ab_d[55]
    DIRECTION OUTPUT ;
    USE SIGNAL ;
    PORT
      LAYER M3 ;
        RECT  42.444 53.963 42.462 54 ;
    END
  END ab_d[55]
  PIN ab_d[56]
    DIRECTION OUTPUT ;
    USE SIGNAL ;
    PORT
      LAYER M3 ;
        RECT  42.516 53.963 42.534 54 ;
    END
  END ab_d[56]
  PIN ab_d[57]
    DIRECTION OUTPUT ;
    USE SIGNAL ;
    PORT
      LAYER M3 ;
        RECT  42.588 53.963 42.606 54 ;
    END
  END ab_d[57]
  PIN ab_d[58]
    DIRECTION OUTPUT ;
    USE SIGNAL ;
    PORT
      LAYER M3 ;
        RECT  42.66 53.963 42.678 54 ;
    END
  END ab_d[58]
  PIN ab_d[59]
    DIRECTION OUTPUT ;
    USE SIGNAL ;
    PORT
      LAYER M3 ;
        RECT  42.732 53.963 42.75 54 ;
    END
  END ab_d[59]
  PIN ab_d[5]
    DIRECTION OUTPUT ;
    USE SIGNAL ;
    PORT
      LAYER M3 ;
        RECT  7.74 53.963 7.758 54 ;
    END
  END ab_d[5]
  PIN ab_d[60]
    DIRECTION OUTPUT ;
    USE SIGNAL ;
    PORT
      LAYER M3 ;
        RECT  42.804 53.963 42.822 54 ;
    END
  END ab_d[60]
  PIN ab_d[61]
    DIRECTION OUTPUT ;
    USE SIGNAL ;
    PORT
      LAYER M3 ;
        RECT  42.876 53.963 42.894 54 ;
    END
  END ab_d[61]
  PIN ab_d[62]
    DIRECTION OUTPUT ;
    USE SIGNAL ;
    PORT
      LAYER M5 ;
        RECT  32.592 53.916 32.616 54 ;
    END
  END ab_d[62]
  PIN ab_d[63]
    DIRECTION OUTPUT ;
    USE SIGNAL ;
    PORT
      LAYER M5 ;
        RECT  32.688 53.916 32.712 54 ;
    END
  END ab_d[63]
  PIN ab_d[64]
    DIRECTION OUTPUT ;
    USE SIGNAL ;
    PORT
      LAYER M5 ;
        RECT  32.784 53.916 32.808 54 ;
    END
  END ab_d[64]
  PIN ab_d[65]
    DIRECTION OUTPUT ;
    USE SIGNAL ;
    PORT
      LAYER M5 ;
        RECT  32.88 53.916 32.904 54 ;
    END
  END ab_d[65]
  PIN ab_d[66]
    DIRECTION OUTPUT ;
    USE SIGNAL ;
    PORT
      LAYER M5 ;
        RECT  32.976 53.916 33 54 ;
    END
  END ab_d[66]
  PIN ab_d[67]
    DIRECTION OUTPUT ;
    USE SIGNAL ;
    PORT
      LAYER M5 ;
        RECT  33.072 53.916 33.096 54 ;
    END
  END ab_d[67]
  PIN ab_d[68]
    DIRECTION OUTPUT ;
    USE SIGNAL ;
    PORT
      LAYER M5 ;
        RECT  33.168 53.916 33.192 54 ;
    END
  END ab_d[68]
  PIN ab_d[69]
    DIRECTION OUTPUT ;
    USE SIGNAL ;
    PORT
      LAYER M5 ;
        RECT  33.264 53.916 33.288 54 ;
    END
  END ab_d[69]
  PIN ab_d[6]
    DIRECTION OUTPUT ;
    USE SIGNAL ;
    PORT
      LAYER M3 ;
        RECT  7.812 53.963 7.83 54 ;
    END
  END ab_d[6]
  PIN ab_d[70]
    DIRECTION OUTPUT ;
    USE SIGNAL ;
    PORT
      LAYER M5 ;
        RECT  33.36 53.916 33.384 54 ;
    END
  END ab_d[70]
  PIN ab_d[71]
    DIRECTION OUTPUT ;
    USE SIGNAL ;
    PORT
      LAYER M5 ;
        RECT  33.456 53.916 33.48 54 ;
    END
  END ab_d[71]
  PIN ab_d[72]
    DIRECTION OUTPUT ;
    USE SIGNAL ;
    PORT
      LAYER M5 ;
        RECT  33.552 53.916 33.576 54 ;
    END
  END ab_d[72]
  PIN ab_d[73]
    DIRECTION OUTPUT ;
    USE SIGNAL ;
    PORT
      LAYER M5 ;
        RECT  33.648 53.916 33.672 54 ;
    END
  END ab_d[73]
  PIN ab_d[74]
    DIRECTION OUTPUT ;
    USE SIGNAL ;
    PORT
      LAYER M5 ;
        RECT  33.744 53.916 33.768 54 ;
    END
  END ab_d[74]
  PIN ab_d[75]
    DIRECTION OUTPUT ;
    USE SIGNAL ;
    PORT
      LAYER M5 ;
        RECT  33.84 53.916 33.864 54 ;
    END
  END ab_d[75]
  PIN ab_d[76]
    DIRECTION OUTPUT ;
    USE SIGNAL ;
    PORT
      LAYER M5 ;
        RECT  33.936 53.916 33.96 54 ;
    END
  END ab_d[76]
  PIN ab_d[77]
    DIRECTION OUTPUT ;
    USE SIGNAL ;
    PORT
      LAYER M5 ;
        RECT  34.032 53.916 34.056 54 ;
    END
  END ab_d[77]
  PIN ab_d[78]
    DIRECTION OUTPUT ;
    USE SIGNAL ;
    PORT
      LAYER M5 ;
        RECT  34.128 53.916 34.152 54 ;
    END
  END ab_d[78]
  PIN ab_d[79]
    DIRECTION OUTPUT ;
    USE SIGNAL ;
    PORT
      LAYER M5 ;
        RECT  34.224 53.916 34.248 54 ;
    END
  END ab_d[79]
  PIN ab_d[7]
    DIRECTION OUTPUT ;
    USE SIGNAL ;
    PORT
      LAYER M3 ;
        RECT  7.884 53.963 7.902 54 ;
    END
  END ab_d[7]
  PIN ab_d[80]
    DIRECTION OUTPUT ;
    USE SIGNAL ;
    PORT
      LAYER M5 ;
        RECT  34.32 53.916 34.344 54 ;
    END
  END ab_d[80]
  PIN ab_d[81]
    DIRECTION OUTPUT ;
    USE SIGNAL ;
    PORT
      LAYER M5 ;
        RECT  34.416 53.916 34.44 54 ;
    END
  END ab_d[81]
  PIN ab_d[82]
    DIRECTION OUTPUT ;
    USE SIGNAL ;
    PORT
      LAYER M5 ;
        RECT  34.512 53.916 34.536 54 ;
    END
  END ab_d[82]
  PIN ab_d[83]
    DIRECTION OUTPUT ;
    USE SIGNAL ;
    PORT
      LAYER M5 ;
        RECT  34.608 53.916 34.632 54 ;
    END
  END ab_d[83]
  PIN ab_d[84]
    DIRECTION OUTPUT ;
    USE SIGNAL ;
    PORT
      LAYER M5 ;
        RECT  34.704 53.916 34.728 54 ;
    END
  END ab_d[84]
  PIN ab_d[85]
    DIRECTION OUTPUT ;
    USE SIGNAL ;
    PORT
      LAYER M5 ;
        RECT  34.8 53.916 34.824 54 ;
    END
  END ab_d[85]
  PIN ab_d[86]
    DIRECTION OUTPUT ;
    USE SIGNAL ;
    PORT
      LAYER M5 ;
        RECT  34.896 53.916 34.92 54 ;
    END
  END ab_d[86]
  PIN ab_d[87]
    DIRECTION OUTPUT ;
    USE SIGNAL ;
    PORT
      LAYER M5 ;
        RECT  34.992 53.916 35.016 54 ;
    END
  END ab_d[87]
  PIN ab_d[88]
    DIRECTION OUTPUT ;
    USE SIGNAL ;
    PORT
      LAYER M5 ;
        RECT  35.088 53.916 35.112 54 ;
    END
  END ab_d[88]
  PIN ab_d[89]
    DIRECTION OUTPUT ;
    USE SIGNAL ;
    PORT
      LAYER M5 ;
        RECT  35.184 53.916 35.208 54 ;
    END
  END ab_d[89]
  PIN ab_d[8]
    DIRECTION OUTPUT ;
    USE SIGNAL ;
    PORT
      LAYER M3 ;
        RECT  7.956 53.963 7.974 54 ;
    END
  END ab_d[8]
  PIN ab_d[90]
    DIRECTION OUTPUT ;
    USE SIGNAL ;
    PORT
      LAYER M5 ;
        RECT  35.28 53.916 35.304 54 ;
    END
  END ab_d[90]
  PIN ab_d[91]
    DIRECTION OUTPUT ;
    USE SIGNAL ;
    PORT
      LAYER M5 ;
        RECT  35.376 53.916 35.4 54 ;
    END
  END ab_d[91]
  PIN ab_d[92]
    DIRECTION OUTPUT ;
    USE SIGNAL ;
    PORT
      LAYER M5 ;
        RECT  35.472 53.916 35.496 54 ;
    END
  END ab_d[92]
  PIN ab_d[93]
    DIRECTION OUTPUT ;
    USE SIGNAL ;
    PORT
      LAYER M5 ;
        RECT  35.568 53.916 35.592 54 ;
    END
  END ab_d[93]
  PIN ab_d[94]
    DIRECTION OUTPUT ;
    USE SIGNAL ;
    PORT
      LAYER M3 ;
        RECT  55.044 53.963 55.062 54 ;
    END
  END ab_d[94]
  PIN ab_d[95]
    DIRECTION OUTPUT ;
    USE SIGNAL ;
    PORT
      LAYER M3 ;
        RECT  55.116 53.963 55.134 54 ;
    END
  END ab_d[95]
  PIN ab_d[96]
    DIRECTION OUTPUT ;
    USE SIGNAL ;
    PORT
      LAYER M3 ;
        RECT  55.188 53.963 55.206 54 ;
    END
  END ab_d[96]
  PIN ab_d[97]
    DIRECTION OUTPUT ;
    USE SIGNAL ;
    PORT
      LAYER M3 ;
        RECT  55.26 53.963 55.278 54 ;
    END
  END ab_d[97]
  PIN ab_d[98]
    DIRECTION OUTPUT ;
    USE SIGNAL ;
    PORT
      LAYER M3 ;
        RECT  55.332 53.963 55.35 54 ;
    END
  END ab_d[98]
  PIN ab_d[99]
    DIRECTION OUTPUT ;
    USE SIGNAL ;
    PORT
      LAYER M3 ;
        RECT  55.404 53.963 55.422 54 ;
    END
  END ab_d[99]
  PIN ab_d[9]
    DIRECTION OUTPUT ;
    USE SIGNAL ;
    PORT
      LAYER M3 ;
        RECT  8.028 53.963 8.046 54 ;
    END
  END ab_d[9]
  PIN b_base_i[0]
    DIRECTION INPUT ;
    USE SIGNAL ;
    PORT
      LAYER M4 ;
        RECT  0 4.368 0.084 4.392 ;
    END
  END b_base_i[0]
  PIN b_base_i[10]
    DIRECTION INPUT ;
    USE SIGNAL ;
    PORT
      LAYER M4 ;
        RECT  0 5.328 0.084 5.352 ;
    END
  END b_base_i[10]
  PIN b_base_i[11]
    DIRECTION INPUT ;
    USE SIGNAL ;
    PORT
      LAYER M4 ;
        RECT  0 5.424 0.084 5.448 ;
    END
  END b_base_i[11]
  PIN b_base_i[12]
    DIRECTION INPUT ;
    USE SIGNAL ;
    PORT
      LAYER M4 ;
        RECT  0 5.52 0.084 5.544 ;
    END
  END b_base_i[12]
  PIN b_base_i[13]
    DIRECTION INPUT ;
    USE SIGNAL ;
    PORT
      LAYER M4 ;
        RECT  0 5.616 0.084 5.64 ;
    END
  END b_base_i[13]
  PIN b_base_i[14]
    DIRECTION INPUT ;
    USE SIGNAL ;
    PORT
      LAYER M4 ;
        RECT  0 8.784 0.084 8.808 ;
    END
  END b_base_i[14]
  PIN b_base_i[15]
    DIRECTION INPUT ;
    USE SIGNAL ;
    PORT
      LAYER M4 ;
        RECT  0 8.88 0.084 8.904 ;
    END
  END b_base_i[15]
  PIN b_base_i[16]
    DIRECTION INPUT ;
    USE SIGNAL ;
    PORT
      LAYER M4 ;
        RECT  0 8.976 0.084 9 ;
    END
  END b_base_i[16]
  PIN b_base_i[17]
    DIRECTION INPUT ;
    USE SIGNAL ;
    PORT
      LAYER M4 ;
        RECT  0 9.072 0.084 9.096 ;
    END
  END b_base_i[17]
  PIN b_base_i[1]
    DIRECTION INPUT ;
    USE SIGNAL ;
    PORT
      LAYER M4 ;
        RECT  0 4.464 0.084 4.488 ;
    END
  END b_base_i[1]
  PIN b_base_i[2]
    DIRECTION INPUT ;
    USE SIGNAL ;
    PORT
      LAYER M4 ;
        RECT  0 4.56 0.084 4.584 ;
    END
  END b_base_i[2]
  PIN b_base_i[3]
    DIRECTION INPUT ;
    USE SIGNAL ;
    PORT
      LAYER M4 ;
        RECT  0 4.656 0.084 4.68 ;
    END
  END b_base_i[3]
  PIN b_base_i[4]
    DIRECTION INPUT ;
    USE SIGNAL ;
    PORT
      LAYER M4 ;
        RECT  0 4.752 0.084 4.776 ;
    END
  END b_base_i[4]
  PIN b_base_i[5]
    DIRECTION INPUT ;
    USE SIGNAL ;
    PORT
      LAYER M4 ;
        RECT  0 4.848 0.084 4.872 ;
    END
  END b_base_i[5]
  PIN b_base_i[6]
    DIRECTION INPUT ;
    USE SIGNAL ;
    PORT
      LAYER M4 ;
        RECT  0 4.944 0.084 4.968 ;
    END
  END b_base_i[6]
  PIN b_base_i[7]
    DIRECTION INPUT ;
    USE SIGNAL ;
    PORT
      LAYER M4 ;
        RECT  0 5.04 0.084 5.064 ;
    END
  END b_base_i[7]
  PIN b_base_i[8]
    DIRECTION INPUT ;
    USE SIGNAL ;
    PORT
      LAYER M4 ;
        RECT  0 5.136 0.084 5.16 ;
    END
  END b_base_i[8]
  PIN b_base_i[9]
    DIRECTION INPUT ;
    USE SIGNAL ;
    PORT
      LAYER M4 ;
        RECT  0 5.232 0.084 5.256 ;
    END
  END b_base_i[9]
  PIN b_v
    DIRECTION OUTPUT ;
    USE SIGNAL ;
    PORT
      LAYER M3 ;
        RECT  26.388 53.963 26.406 54 ;
    END
  END b_v
  PIN c_base_i[0]
    DIRECTION INPUT ;
    USE SIGNAL ;
    PORT
      LAYER M4 ;
        RECT  0 9.168 0.084 9.192 ;
    END
  END c_base_i[0]
  PIN c_base_i[10]
    DIRECTION INPUT ;
    USE SIGNAL ;
    PORT
      LAYER M4 ;
        RECT  0 10.128 0.084 10.152 ;
    END
  END c_base_i[10]
  PIN c_base_i[11]
    DIRECTION INPUT ;
    USE SIGNAL ;
    PORT
      LAYER M4 ;
        RECT  0 10.224 0.084 10.248 ;
    END
  END c_base_i[11]
  PIN c_base_i[12]
    DIRECTION INPUT ;
    USE SIGNAL ;
    PORT
      LAYER M4 ;
        RECT  0 10.32 0.084 10.344 ;
    END
  END c_base_i[12]
  PIN c_base_i[13]
    DIRECTION INPUT ;
    USE SIGNAL ;
    PORT
      LAYER M4 ;
        RECT  0 10.416 0.084 10.44 ;
    END
  END c_base_i[13]
  PIN c_base_i[14]
    DIRECTION INPUT ;
    USE SIGNAL ;
    PORT
      LAYER M4 ;
        RECT  0 10.512 0.084 10.536 ;
    END
  END c_base_i[14]
  PIN c_base_i[15]
    DIRECTION INPUT ;
    USE SIGNAL ;
    PORT
      LAYER M4 ;
        RECT  0 10.608 0.084 10.632 ;
    END
  END c_base_i[15]
  PIN c_base_i[16]
    DIRECTION INPUT ;
    USE SIGNAL ;
    PORT
      LAYER M4 ;
        RECT  0 10.704 0.084 10.728 ;
    END
  END c_base_i[16]
  PIN c_base_i[17]
    DIRECTION INPUT ;
    USE SIGNAL ;
    PORT
      LAYER M4 ;
        RECT  0 10.8 0.084 10.824 ;
    END
  END c_base_i[17]
  PIN c_base_i[1]
    DIRECTION INPUT ;
    USE SIGNAL ;
    PORT
      LAYER M4 ;
        RECT  0 9.264 0.084 9.288 ;
    END
  END c_base_i[1]
  PIN c_base_i[2]
    DIRECTION INPUT ;
    USE SIGNAL ;
    PORT
      LAYER M4 ;
        RECT  0 9.36 0.084 9.384 ;
    END
  END c_base_i[2]
  PIN c_base_i[3]
    DIRECTION INPUT ;
    USE SIGNAL ;
    PORT
      LAYER M4 ;
        RECT  0 9.456 0.084 9.48 ;
    END
  END c_base_i[3]
  PIN c_base_i[4]
    DIRECTION INPUT ;
    USE SIGNAL ;
    PORT
      LAYER M4 ;
        RECT  0 9.552 0.084 9.576 ;
    END
  END c_base_i[4]
  PIN c_base_i[5]
    DIRECTION INPUT ;
    USE SIGNAL ;
    PORT
      LAYER M4 ;
        RECT  0 9.648 0.084 9.672 ;
    END
  END c_base_i[5]
  PIN c_base_i[6]
    DIRECTION INPUT ;
    USE SIGNAL ;
    PORT
      LAYER M4 ;
        RECT  0 9.744 0.084 9.768 ;
    END
  END c_base_i[6]
  PIN c_base_i[7]
    DIRECTION INPUT ;
    USE SIGNAL ;
    PORT
      LAYER M4 ;
        RECT  0 9.84 0.084 9.864 ;
    END
  END c_base_i[7]
  PIN c_base_i[8]
    DIRECTION INPUT ;
    USE SIGNAL ;
    PORT
      LAYER M4 ;
        RECT  0 9.936 0.084 9.96 ;
    END
  END c_base_i[8]
  PIN c_base_i[9]
    DIRECTION INPUT ;
    USE SIGNAL ;
    PORT
      LAYER M4 ;
        RECT  0 10.032 0.084 10.056 ;
    END
  END c_base_i[9]
  PIN c_cr
    DIRECTION INPUT ;
    USE SIGNAL ;
    PORT
      LAYER M3 ;
        RECT  26.46 53.963 26.478 54 ;
    END
  END c_cr
  PIN c_done
    DIRECTION OUTPUT ;
    USE SIGNAL ;
    PORT
      LAYER M4 ;
        RECT  0 10.896 0.084 10.92 ;
    END
  END c_done
  PIN c_f[0]
    DIRECTION OUTPUT ;
    USE SIGNAL ;
    PORT
      LAYER M3 ;
        RECT  26.532 53.963 26.55 54 ;
    END
  END c_f[0]
  PIN c_f[1]
    DIRECTION OUTPUT ;
    USE SIGNAL ;
    PORT
      LAYER M3 ;
        RECT  26.604 53.963 26.622 54 ;
    END
  END c_f[1]
  PIN c_f[2]
    DIRECTION OUTPUT ;
    USE SIGNAL ;
    PORT
      LAYER M3 ;
        RECT  26.676 53.963 26.694 54 ;
    END
  END c_f[2]
  PIN c_f[3]
    DIRECTION OUTPUT ;
    USE SIGNAL ;
    PORT
      LAYER M3 ;
        RECT  26.748 53.963 26.766 54 ;
    END
  END c_f[3]
  PIN c_f[4]
    DIRECTION OUTPUT ;
    USE SIGNAL ;
    PORT
      LAYER M3 ;
        RECT  26.82 53.963 26.838 54 ;
    END
  END c_f[4]
  PIN c_f[5]
    DIRECTION OUTPUT ;
    USE SIGNAL ;
    PORT
      LAYER M3 ;
        RECT  26.892 53.963 26.91 54 ;
    END
  END c_f[5]
  PIN c_f[6]
    DIRECTION OUTPUT ;
    USE SIGNAL ;
    PORT
      LAYER M3 ;
        RECT  26.964 53.963 26.982 54 ;
    END
  END c_f[6]
  PIN c_f[7]
    DIRECTION OUTPUT ;
    USE SIGNAL ;
    PORT
      LAYER M3 ;
        RECT  27.036 53.963 27.054 54 ;
    END
  END c_f[7]
  PIN c_h[0]
    DIRECTION OUTPUT ;
    USE SIGNAL ;
    PORT
      LAYER M3 ;
        RECT  27.108 53.963 27.126 54 ;
    END
  END c_h[0]
  PIN c_h[100]
    DIRECTION OUTPUT ;
    USE SIGNAL ;
    PORT
      LAYER M3 ;
        RECT  13.788 53.963 13.806 54 ;
    END
  END c_h[100]
  PIN c_h[101]
    DIRECTION OUTPUT ;
    USE SIGNAL ;
    PORT
      LAYER M3 ;
        RECT  13.86 53.963 13.878 54 ;
    END
  END c_h[101]
  PIN c_h[102]
    DIRECTION OUTPUT ;
    USE SIGNAL ;
    PORT
      LAYER M3 ;
        RECT  13.932 53.963 13.95 54 ;
    END
  END c_h[102]
  PIN c_h[103]
    DIRECTION OUTPUT ;
    USE SIGNAL ;
    PORT
      LAYER M3 ;
        RECT  14.004 53.963 14.022 54 ;
    END
  END c_h[103]
  PIN c_h[10]
    DIRECTION OUTPUT ;
    USE SIGNAL ;
    PORT
      LAYER M3 ;
        RECT  27.828 53.963 27.846 54 ;
    END
  END c_h[10]
  PIN c_h[11]
    DIRECTION OUTPUT ;
    USE SIGNAL ;
    PORT
      LAYER M3 ;
        RECT  27.9 53.963 27.918 54 ;
    END
  END c_h[11]
  PIN c_h[12]
    DIRECTION OUTPUT ;
    USE SIGNAL ;
    PORT
      LAYER M3 ;
        RECT  27.972 53.963 27.99 54 ;
    END
  END c_h[12]
  PIN c_h[13]
    DIRECTION OUTPUT ;
    USE SIGNAL ;
    PORT
      LAYER M3 ;
        RECT  28.044 53.963 28.062 54 ;
    END
  END c_h[13]
  PIN c_h[14]
    DIRECTION OUTPUT ;
    USE SIGNAL ;
    PORT
      LAYER M3 ;
        RECT  28.116 53.963 28.134 54 ;
    END
  END c_h[14]
  PIN c_h[15]
    DIRECTION OUTPUT ;
    USE SIGNAL ;
    PORT
      LAYER M3 ;
        RECT  28.188 53.963 28.206 54 ;
    END
  END c_h[15]
  PIN c_h[16]
    DIRECTION OUTPUT ;
    USE SIGNAL ;
    PORT
      LAYER M3 ;
        RECT  28.26 53.963 28.278 54 ;
    END
  END c_h[16]
  PIN c_h[17]
    DIRECTION OUTPUT ;
    USE SIGNAL ;
    PORT
      LAYER M3 ;
        RECT  28.332 53.963 28.35 54 ;
    END
  END c_h[17]
  PIN c_h[18]
    DIRECTION OUTPUT ;
    USE SIGNAL ;
    PORT
      LAYER M3 ;
        RECT  28.404 53.963 28.422 54 ;
    END
  END c_h[18]
  PIN c_h[19]
    DIRECTION OUTPUT ;
    USE SIGNAL ;
    PORT
      LAYER M3 ;
        RECT  28.476 53.963 28.494 54 ;
    END
  END c_h[19]
  PIN c_h[1]
    DIRECTION OUTPUT ;
    USE SIGNAL ;
    PORT
      LAYER M3 ;
        RECT  27.18 53.963 27.198 54 ;
    END
  END c_h[1]
  PIN c_h[20]
    DIRECTION OUTPUT ;
    USE SIGNAL ;
    PORT
      LAYER M5 ;
        RECT  48.72 53.916 48.744 54 ;
    END
  END c_h[20]
  PIN c_h[21]
    DIRECTION OUTPUT ;
    USE SIGNAL ;
    PORT
      LAYER M5 ;
        RECT  48.816 53.916 48.84 54 ;
    END
  END c_h[21]
  PIN c_h[22]
    DIRECTION OUTPUT ;
    USE SIGNAL ;
    PORT
      LAYER M5 ;
        RECT  48.912 53.916 48.936 54 ;
    END
  END c_h[22]
  PIN c_h[23]
    DIRECTION OUTPUT ;
    USE SIGNAL ;
    PORT
      LAYER M5 ;
        RECT  49.008 53.916 49.032 54 ;
    END
  END c_h[23]
  PIN c_h[24]
    DIRECTION OUTPUT ;
    USE SIGNAL ;
    PORT
      LAYER M5 ;
        RECT  49.104 53.916 49.128 54 ;
    END
  END c_h[24]
  PIN c_h[25]
    DIRECTION OUTPUT ;
    USE SIGNAL ;
    PORT
      LAYER M5 ;
        RECT  49.2 53.916 49.224 54 ;
    END
  END c_h[25]
  PIN c_h[26]
    DIRECTION OUTPUT ;
    USE SIGNAL ;
    PORT
      LAYER M5 ;
        RECT  49.296 53.916 49.32 54 ;
    END
  END c_h[26]
  PIN c_h[27]
    DIRECTION OUTPUT ;
    USE SIGNAL ;
    PORT
      LAYER M5 ;
        RECT  49.392 53.916 49.416 54 ;
    END
  END c_h[27]
  PIN c_h[28]
    DIRECTION OUTPUT ;
    USE SIGNAL ;
    PORT
      LAYER M5 ;
        RECT  49.488 53.916 49.512 54 ;
    END
  END c_h[28]
  PIN c_h[29]
    DIRECTION OUTPUT ;
    USE SIGNAL ;
    PORT
      LAYER M5 ;
        RECT  49.584 53.916 49.608 54 ;
    END
  END c_h[29]
  PIN c_h[2]
    DIRECTION OUTPUT ;
    USE SIGNAL ;
    PORT
      LAYER M3 ;
        RECT  27.252 53.963 27.27 54 ;
    END
  END c_h[2]
  PIN c_h[30]
    DIRECTION OUTPUT ;
    USE SIGNAL ;
    PORT
      LAYER M5 ;
        RECT  49.68 53.916 49.704 54 ;
    END
  END c_h[30]
  PIN c_h[31]
    DIRECTION OUTPUT ;
    USE SIGNAL ;
    PORT
      LAYER M5 ;
        RECT  49.776 53.916 49.8 54 ;
    END
  END c_h[31]
  PIN c_h[32]
    DIRECTION OUTPUT ;
    USE SIGNAL ;
    PORT
      LAYER M5 ;
        RECT  49.872 53.916 49.896 54 ;
    END
  END c_h[32]
  PIN c_h[33]
    DIRECTION OUTPUT ;
    USE SIGNAL ;
    PORT
      LAYER M5 ;
        RECT  49.968 53.916 49.992 54 ;
    END
  END c_h[33]
  PIN c_h[34]
    DIRECTION OUTPUT ;
    USE SIGNAL ;
    PORT
      LAYER M5 ;
        RECT  50.064 53.916 50.088 54 ;
    END
  END c_h[34]
  PIN c_h[35]
    DIRECTION OUTPUT ;
    USE SIGNAL ;
    PORT
      LAYER M5 ;
        RECT  50.16 53.916 50.184 54 ;
    END
  END c_h[35]
  PIN c_h[36]
    DIRECTION OUTPUT ;
    USE SIGNAL ;
    PORT
      LAYER M5 ;
        RECT  50.256 53.916 50.28 54 ;
    END
  END c_h[36]
  PIN c_h[37]
    DIRECTION OUTPUT ;
    USE SIGNAL ;
    PORT
      LAYER M5 ;
        RECT  50.352 53.916 50.376 54 ;
    END
  END c_h[37]
  PIN c_h[38]
    DIRECTION OUTPUT ;
    USE SIGNAL ;
    PORT
      LAYER M5 ;
        RECT  50.448 53.916 50.472 54 ;
    END
  END c_h[38]
  PIN c_h[39]
    DIRECTION OUTPUT ;
    USE SIGNAL ;
    PORT
      LAYER M5 ;
        RECT  50.544 53.916 50.568 54 ;
    END
  END c_h[39]
  PIN c_h[3]
    DIRECTION OUTPUT ;
    USE SIGNAL ;
    PORT
      LAYER M3 ;
        RECT  27.324 53.963 27.342 54 ;
    END
  END c_h[3]
  PIN c_h[40]
    DIRECTION OUTPUT ;
    USE SIGNAL ;
    PORT
      LAYER M5 ;
        RECT  50.64 53.916 50.664 54 ;
    END
  END c_h[40]
  PIN c_h[41]
    DIRECTION OUTPUT ;
    USE SIGNAL ;
    PORT
      LAYER M5 ;
        RECT  50.736 53.916 50.76 54 ;
    END
  END c_h[41]
  PIN c_h[42]
    DIRECTION OUTPUT ;
    USE SIGNAL ;
    PORT
      LAYER M5 ;
        RECT  50.832 53.916 50.856 54 ;
    END
  END c_h[42]
  PIN c_h[43]
    DIRECTION OUTPUT ;
    USE SIGNAL ;
    PORT
      LAYER M5 ;
        RECT  50.928 53.916 50.952 54 ;
    END
  END c_h[43]
  PIN c_h[44]
    DIRECTION OUTPUT ;
    USE SIGNAL ;
    PORT
      LAYER M5 ;
        RECT  51.024 53.916 51.048 54 ;
    END
  END c_h[44]
  PIN c_h[45]
    DIRECTION OUTPUT ;
    USE SIGNAL ;
    PORT
      LAYER M5 ;
        RECT  51.12 53.916 51.144 54 ;
    END
  END c_h[45]
  PIN c_h[46]
    DIRECTION OUTPUT ;
    USE SIGNAL ;
    PORT
      LAYER M5 ;
        RECT  51.216 53.916 51.24 54 ;
    END
  END c_h[46]
  PIN c_h[47]
    DIRECTION OUTPUT ;
    USE SIGNAL ;
    PORT
      LAYER M5 ;
        RECT  51.312 53.916 51.336 54 ;
    END
  END c_h[47]
  PIN c_h[48]
    DIRECTION OUTPUT ;
    USE SIGNAL ;
    PORT
      LAYER M5 ;
        RECT  51.408 53.916 51.432 54 ;
    END
  END c_h[48]
  PIN c_h[49]
    DIRECTION OUTPUT ;
    USE SIGNAL ;
    PORT
      LAYER M5 ;
        RECT  51.504 53.916 51.528 54 ;
    END
  END c_h[49]
  PIN c_h[4]
    DIRECTION OUTPUT ;
    USE SIGNAL ;
    PORT
      LAYER M3 ;
        RECT  27.396 53.963 27.414 54 ;
    END
  END c_h[4]
  PIN c_h[50]
    DIRECTION OUTPUT ;
    USE SIGNAL ;
    PORT
      LAYER M5 ;
        RECT  51.6 53.916 51.624 54 ;
    END
  END c_h[50]
  PIN c_h[51]
    DIRECTION OUTPUT ;
    USE SIGNAL ;
    PORT
      LAYER M5 ;
        RECT  51.696 53.916 51.72 54 ;
    END
  END c_h[51]
  PIN c_h[52]
    DIRECTION OUTPUT ;
    USE SIGNAL ;
    PORT
      LAYER M5 ;
        RECT  45.648 53.916 45.672 54 ;
    END
  END c_h[52]
  PIN c_h[53]
    DIRECTION OUTPUT ;
    USE SIGNAL ;
    PORT
      LAYER M5 ;
        RECT  45.744 53.916 45.768 54 ;
    END
  END c_h[53]
  PIN c_h[54]
    DIRECTION OUTPUT ;
    USE SIGNAL ;
    PORT
      LAYER M5 ;
        RECT  45.84 53.916 45.864 54 ;
    END
  END c_h[54]
  PIN c_h[55]
    DIRECTION OUTPUT ;
    USE SIGNAL ;
    PORT
      LAYER M5 ;
        RECT  45.936 53.916 45.96 54 ;
    END
  END c_h[55]
  PIN c_h[56]
    DIRECTION OUTPUT ;
    USE SIGNAL ;
    PORT
      LAYER M5 ;
        RECT  46.032 53.916 46.056 54 ;
    END
  END c_h[56]
  PIN c_h[57]
    DIRECTION OUTPUT ;
    USE SIGNAL ;
    PORT
      LAYER M5 ;
        RECT  46.128 53.916 46.152 54 ;
    END
  END c_h[57]
  PIN c_h[58]
    DIRECTION OUTPUT ;
    USE SIGNAL ;
    PORT
      LAYER M5 ;
        RECT  46.224 53.916 46.248 54 ;
    END
  END c_h[58]
  PIN c_h[59]
    DIRECTION OUTPUT ;
    USE SIGNAL ;
    PORT
      LAYER M5 ;
        RECT  46.32 53.916 46.344 54 ;
    END
  END c_h[59]
  PIN c_h[5]
    DIRECTION OUTPUT ;
    USE SIGNAL ;
    PORT
      LAYER M3 ;
        RECT  27.468 53.963 27.486 54 ;
    END
  END c_h[5]
  PIN c_h[60]
    DIRECTION OUTPUT ;
    USE SIGNAL ;
    PORT
      LAYER M5 ;
        RECT  46.416 53.916 46.44 54 ;
    END
  END c_h[60]
  PIN c_h[61]
    DIRECTION OUTPUT ;
    USE SIGNAL ;
    PORT
      LAYER M5 ;
        RECT  46.512 53.916 46.536 54 ;
    END
  END c_h[61]
  PIN c_h[62]
    DIRECTION OUTPUT ;
    USE SIGNAL ;
    PORT
      LAYER M5 ;
        RECT  46.608 53.916 46.632 54 ;
    END
  END c_h[62]
  PIN c_h[63]
    DIRECTION OUTPUT ;
    USE SIGNAL ;
    PORT
      LAYER M5 ;
        RECT  46.704 53.916 46.728 54 ;
    END
  END c_h[63]
  PIN c_h[64]
    DIRECTION OUTPUT ;
    USE SIGNAL ;
    PORT
      LAYER M5 ;
        RECT  46.8 53.916 46.824 54 ;
    END
  END c_h[64]
  PIN c_h[65]
    DIRECTION OUTPUT ;
    USE SIGNAL ;
    PORT
      LAYER M5 ;
        RECT  46.896 53.916 46.92 54 ;
    END
  END c_h[65]
  PIN c_h[66]
    DIRECTION OUTPUT ;
    USE SIGNAL ;
    PORT
      LAYER M5 ;
        RECT  46.992 53.916 47.016 54 ;
    END
  END c_h[66]
  PIN c_h[67]
    DIRECTION OUTPUT ;
    USE SIGNAL ;
    PORT
      LAYER M5 ;
        RECT  47.088 53.916 47.112 54 ;
    END
  END c_h[67]
  PIN c_h[68]
    DIRECTION OUTPUT ;
    USE SIGNAL ;
    PORT
      LAYER M5 ;
        RECT  47.184 53.916 47.208 54 ;
    END
  END c_h[68]
  PIN c_h[69]
    DIRECTION OUTPUT ;
    USE SIGNAL ;
    PORT
      LAYER M5 ;
        RECT  47.28 53.916 47.304 54 ;
    END
  END c_h[69]
  PIN c_h[6]
    DIRECTION OUTPUT ;
    USE SIGNAL ;
    PORT
      LAYER M3 ;
        RECT  27.54 53.963 27.558 54 ;
    END
  END c_h[6]
  PIN c_h[70]
    DIRECTION OUTPUT ;
    USE SIGNAL ;
    PORT
      LAYER M5 ;
        RECT  47.376 53.916 47.4 54 ;
    END
  END c_h[70]
  PIN c_h[71]
    DIRECTION OUTPUT ;
    USE SIGNAL ;
    PORT
      LAYER M5 ;
        RECT  47.472 53.916 47.496 54 ;
    END
  END c_h[71]
  PIN c_h[72]
    DIRECTION OUTPUT ;
    USE SIGNAL ;
    PORT
      LAYER M5 ;
        RECT  47.568 53.916 47.592 54 ;
    END
  END c_h[72]
  PIN c_h[73]
    DIRECTION OUTPUT ;
    USE SIGNAL ;
    PORT
      LAYER M5 ;
        RECT  47.664 53.916 47.688 54 ;
    END
  END c_h[73]
  PIN c_h[74]
    DIRECTION OUTPUT ;
    USE SIGNAL ;
    PORT
      LAYER M5 ;
        RECT  47.76 53.916 47.784 54 ;
    END
  END c_h[74]
  PIN c_h[75]
    DIRECTION OUTPUT ;
    USE SIGNAL ;
    PORT
      LAYER M5 ;
        RECT  47.856 53.916 47.88 54 ;
    END
  END c_h[75]
  PIN c_h[76]
    DIRECTION OUTPUT ;
    USE SIGNAL ;
    PORT
      LAYER M5 ;
        RECT  47.952 53.916 47.976 54 ;
    END
  END c_h[76]
  PIN c_h[77]
    DIRECTION OUTPUT ;
    USE SIGNAL ;
    PORT
      LAYER M5 ;
        RECT  48.048 53.916 48.072 54 ;
    END
  END c_h[77]
  PIN c_h[78]
    DIRECTION OUTPUT ;
    USE SIGNAL ;
    PORT
      LAYER M5 ;
        RECT  48.144 53.916 48.168 54 ;
    END
  END c_h[78]
  PIN c_h[79]
    DIRECTION OUTPUT ;
    USE SIGNAL ;
    PORT
      LAYER M5 ;
        RECT  48.24 53.916 48.264 54 ;
    END
  END c_h[79]
  PIN c_h[7]
    DIRECTION OUTPUT ;
    USE SIGNAL ;
    PORT
      LAYER M3 ;
        RECT  27.612 53.963 27.63 54 ;
    END
  END c_h[7]
  PIN c_h[80]
    DIRECTION OUTPUT ;
    USE SIGNAL ;
    PORT
      LAYER M5 ;
        RECT  48.336 53.916 48.36 54 ;
    END
  END c_h[80]
  PIN c_h[81]
    DIRECTION OUTPUT ;
    USE SIGNAL ;
    PORT
      LAYER M5 ;
        RECT  48.432 53.916 48.456 54 ;
    END
  END c_h[81]
  PIN c_h[82]
    DIRECTION OUTPUT ;
    USE SIGNAL ;
    PORT
      LAYER M5 ;
        RECT  48.528 53.916 48.552 54 ;
    END
  END c_h[82]
  PIN c_h[83]
    DIRECTION OUTPUT ;
    USE SIGNAL ;
    PORT
      LAYER M5 ;
        RECT  48.624 53.916 48.648 54 ;
    END
  END c_h[83]
  PIN c_h[84]
    DIRECTION OUTPUT ;
    USE SIGNAL ;
    PORT
      LAYER M3 ;
        RECT  12.636 53.963 12.654 54 ;
    END
  END c_h[84]
  PIN c_h[85]
    DIRECTION OUTPUT ;
    USE SIGNAL ;
    PORT
      LAYER M3 ;
        RECT  12.708 53.963 12.726 54 ;
    END
  END c_h[85]
  PIN c_h[86]
    DIRECTION OUTPUT ;
    USE SIGNAL ;
    PORT
      LAYER M3 ;
        RECT  12.78 53.963 12.798 54 ;
    END
  END c_h[86]
  PIN c_h[87]
    DIRECTION OUTPUT ;
    USE SIGNAL ;
    PORT
      LAYER M3 ;
        RECT  12.852 53.963 12.87 54 ;
    END
  END c_h[87]
  PIN c_h[88]
    DIRECTION OUTPUT ;
    USE SIGNAL ;
    PORT
      LAYER M3 ;
        RECT  12.924 53.963 12.942 54 ;
    END
  END c_h[88]
  PIN c_h[89]
    DIRECTION OUTPUT ;
    USE SIGNAL ;
    PORT
      LAYER M3 ;
        RECT  12.996 53.963 13.014 54 ;
    END
  END c_h[89]
  PIN c_h[8]
    DIRECTION OUTPUT ;
    USE SIGNAL ;
    PORT
      LAYER M3 ;
        RECT  27.684 53.963 27.702 54 ;
    END
  END c_h[8]
  PIN c_h[90]
    DIRECTION OUTPUT ;
    USE SIGNAL ;
    PORT
      LAYER M3 ;
        RECT  13.068 53.963 13.086 54 ;
    END
  END c_h[90]
  PIN c_h[91]
    DIRECTION OUTPUT ;
    USE SIGNAL ;
    PORT
      LAYER M3 ;
        RECT  13.14 53.963 13.158 54 ;
    END
  END c_h[91]
  PIN c_h[92]
    DIRECTION OUTPUT ;
    USE SIGNAL ;
    PORT
      LAYER M3 ;
        RECT  13.212 53.963 13.23 54 ;
    END
  END c_h[92]
  PIN c_h[93]
    DIRECTION OUTPUT ;
    USE SIGNAL ;
    PORT
      LAYER M3 ;
        RECT  13.284 53.963 13.302 54 ;
    END
  END c_h[93]
  PIN c_h[94]
    DIRECTION OUTPUT ;
    USE SIGNAL ;
    PORT
      LAYER M3 ;
        RECT  13.356 53.963 13.374 54 ;
    END
  END c_h[94]
  PIN c_h[95]
    DIRECTION OUTPUT ;
    USE SIGNAL ;
    PORT
      LAYER M3 ;
        RECT  13.428 53.963 13.446 54 ;
    END
  END c_h[95]
  PIN c_h[96]
    DIRECTION OUTPUT ;
    USE SIGNAL ;
    PORT
      LAYER M3 ;
        RECT  13.5 53.963 13.518 54 ;
    END
  END c_h[96]
  PIN c_h[97]
    DIRECTION OUTPUT ;
    USE SIGNAL ;
    PORT
      LAYER M3 ;
        RECT  13.572 53.963 13.59 54 ;
    END
  END c_h[97]
  PIN c_h[98]
    DIRECTION OUTPUT ;
    USE SIGNAL ;
    PORT
      LAYER M3 ;
        RECT  13.644 53.963 13.662 54 ;
    END
  END c_h[98]
  PIN c_h[99]
    DIRECTION OUTPUT ;
    USE SIGNAL ;
    PORT
      LAYER M3 ;
        RECT  13.716 53.963 13.734 54 ;
    END
  END c_h[99]
  PIN c_h[9]
    DIRECTION OUTPUT ;
    USE SIGNAL ;
    PORT
      LAYER M3 ;
        RECT  27.756 53.963 27.774 54 ;
    END
  END c_h[9]
  PIN c_n_i[0]
    DIRECTION INPUT ;
    USE SIGNAL ;
    PORT
      LAYER M4 ;
        RECT  0 10.992 0.084 11.016 ;
    END
  END c_n_i[0]
  PIN c_n_i[10]
    DIRECTION INPUT ;
    USE SIGNAL ;
    PORT
      LAYER M4 ;
        RECT  0 5.808 0.084 5.832 ;
    END
  END c_n_i[10]
  PIN c_n_i[11]
    DIRECTION INPUT ;
    USE SIGNAL ;
    PORT
      LAYER M4 ;
        RECT  0 5.904 0.084 5.928 ;
    END
  END c_n_i[11]
  PIN c_n_i[1]
    DIRECTION INPUT ;
    USE SIGNAL ;
    PORT
      LAYER M4 ;
        RECT  0 11.088 0.084 11.112 ;
    END
  END c_n_i[1]
  PIN c_n_i[2]
    DIRECTION INPUT ;
    USE SIGNAL ;
    PORT
      LAYER M4 ;
        RECT  0 11.184 0.084 11.208 ;
    END
  END c_n_i[2]
  PIN c_n_i[3]
    DIRECTION INPUT ;
    USE SIGNAL ;
    PORT
      LAYER M4 ;
        RECT  0 11.28 0.084 11.304 ;
    END
  END c_n_i[3]
  PIN c_n_i[4]
    DIRECTION INPUT ;
    USE SIGNAL ;
    PORT
      LAYER M4 ;
        RECT  0 11.376 0.084 11.4 ;
    END
  END c_n_i[4]
  PIN c_n_i[5]
    DIRECTION INPUT ;
    USE SIGNAL ;
    PORT
      LAYER M4 ;
        RECT  0 11.472 0.084 11.496 ;
    END
  END c_n_i[5]
  PIN c_n_i[6]
    DIRECTION INPUT ;
    USE SIGNAL ;
    PORT
      LAYER M4 ;
        RECT  0 11.568 0.084 11.592 ;
    END
  END c_n_i[6]
  PIN c_n_i[7]
    DIRECTION INPUT ;
    USE SIGNAL ;
    PORT
      LAYER M4 ;
        RECT  0 11.664 0.084 11.688 ;
    END
  END c_n_i[7]
  PIN c_n_i[8]
    DIRECTION INPUT ;
    USE SIGNAL ;
    PORT
      LAYER M4 ;
        RECT  0 11.76 0.084 11.784 ;
    END
  END c_n_i[8]
  PIN c_n_i[9]
    DIRECTION INPUT ;
    USE SIGNAL ;
    PORT
      LAYER M4 ;
        RECT  0 5.712 0.084 5.736 ;
    END
  END c_n_i[9]
  PIN c_stride_i[0]
    DIRECTION INPUT ;
    USE SIGNAL ;
    PORT
      LAYER M4 ;
        RECT  0 6 0.084 6.024 ;
    END
  END c_stride_i[0]
  PIN c_stride_i[10]
    DIRECTION INPUT ;
    USE SIGNAL ;
    PORT
      LAYER M4 ;
        RECT  0 6.96 0.084 6.984 ;
    END
  END c_stride_i[10]
  PIN c_stride_i[11]
    DIRECTION INPUT ;
    USE SIGNAL ;
    PORT
      LAYER M4 ;
        RECT  0 7.056 0.084 7.08 ;
    END
  END c_stride_i[11]
  PIN c_stride_i[12]
    DIRECTION INPUT ;
    USE SIGNAL ;
    PORT
      LAYER M4 ;
        RECT  0 7.152 0.084 7.176 ;
    END
  END c_stride_i[12]
  PIN c_stride_i[13]
    DIRECTION INPUT ;
    USE SIGNAL ;
    PORT
      LAYER M4 ;
        RECT  0 7.248 0.084 7.272 ;
    END
  END c_stride_i[13]
  PIN c_stride_i[14]
    DIRECTION INPUT ;
    USE SIGNAL ;
    PORT
      LAYER M4 ;
        RECT  0 7.344 0.084 7.368 ;
    END
  END c_stride_i[14]
  PIN c_stride_i[15]
    DIRECTION INPUT ;
    USE SIGNAL ;
    PORT
      LAYER M4 ;
        RECT  0 7.44 0.084 7.464 ;
    END
  END c_stride_i[15]
  PIN c_stride_i[16]
    DIRECTION INPUT ;
    USE SIGNAL ;
    PORT
      LAYER M4 ;
        RECT  0 7.536 0.084 7.56 ;
    END
  END c_stride_i[16]
  PIN c_stride_i[17]
    DIRECTION INPUT ;
    USE SIGNAL ;
    PORT
      LAYER M4 ;
        RECT  0 7.632 0.084 7.656 ;
    END
  END c_stride_i[17]
  PIN c_stride_i[1]
    DIRECTION INPUT ;
    USE SIGNAL ;
    PORT
      LAYER M4 ;
        RECT  0 6.096 0.084 6.12 ;
    END
  END c_stride_i[1]
  PIN c_stride_i[2]
    DIRECTION INPUT ;
    USE SIGNAL ;
    PORT
      LAYER M4 ;
        RECT  0 6.192 0.084 6.216 ;
    END
  END c_stride_i[2]
  PIN c_stride_i[3]
    DIRECTION INPUT ;
    USE SIGNAL ;
    PORT
      LAYER M4 ;
        RECT  0 6.288 0.084 6.312 ;
    END
  END c_stride_i[3]
  PIN c_stride_i[4]
    DIRECTION INPUT ;
    USE SIGNAL ;
    PORT
      LAYER M4 ;
        RECT  0 6.384 0.084 6.408 ;
    END
  END c_stride_i[4]
  PIN c_stride_i[5]
    DIRECTION INPUT ;
    USE SIGNAL ;
    PORT
      LAYER M4 ;
        RECT  0 6.48 0.084 6.504 ;
    END
  END c_stride_i[5]
  PIN c_stride_i[6]
    DIRECTION INPUT ;
    USE SIGNAL ;
    PORT
      LAYER M4 ;
        RECT  0 6.576 0.084 6.6 ;
    END
  END c_stride_i[6]
  PIN c_stride_i[7]
    DIRECTION INPUT ;
    USE SIGNAL ;
    PORT
      LAYER M4 ;
        RECT  0 6.672 0.084 6.696 ;
    END
  END c_stride_i[7]
  PIN c_stride_i[8]
    DIRECTION INPUT ;
    USE SIGNAL ;
    PORT
      LAYER M4 ;
        RECT  0 6.768 0.084 6.792 ;
    END
  END c_stride_i[8]
  PIN c_stride_i[9]
    DIRECTION INPUT ;
    USE SIGNAL ;
    PORT
      LAYER M4 ;
        RECT  0 6.864 0.084 6.888 ;
    END
  END c_stride_i[9]
  PIN c_v
    DIRECTION OUTPUT ;
    USE SIGNAL ;
    PORT
      LAYER M3 ;
        RECT  14.076 53.963 14.094 54 ;
    END
  END c_v
  PIN clk
    DIRECTION INPUT ;
    USE SIGNAL ;
    PORT
      LAYER M4 ;
        RECT  0 7.728 0.084 7.752 ;
    END
  END clk
  PIN idle
    DIRECTION OUTPUT ;
    USE SIGNAL ;
    PORT
      LAYER M4 ;
        RECT  0 7.824 0.084 7.848 ;
    END
  END idle
  PIN keep_en_i
    DIRECTION INPUT ;
    USE SIGNAL ;
    PORT
      LAYER M4 ;
        RECT  0 7.92 0.084 7.944 ;
    END
  END keep_en_i
  PIN lid[0]
    DIRECTION INPUT ;
    USE SIGNAL ;
    PORT
      LAYER M4 ;
        RECT  0 8.016 0.084 8.04 ;
    END
  END lid[0]
  PIN lid[1]
    DIRECTION INPUT ;
    USE SIGNAL ;
    PORT
      LAYER M4 ;
        RECT  0 8.112 0.084 8.136 ;
    END
  END lid[1]
  PIN lid[2]
    DIRECTION INPUT ;
    USE SIGNAL ;
    PORT
      LAYER M4 ;
        RECT  0 8.208 0.084 8.232 ;
    END
  END lid[2]
  PIN rank_i[0]
    DIRECTION INPUT ;
    USE SIGNAL ;
    PORT
      LAYER M4 ;
        RECT  0 8.304 0.084 8.328 ;
    END
  END rank_i[0]
  PIN rank_i[1]
    DIRECTION INPUT ;
    USE SIGNAL ;
    PORT
      LAYER M4 ;
        RECT  0 8.4 0.084 8.424 ;
    END
  END rank_i[1]
  PIN rank_i[2]
    DIRECTION INPUT ;
    USE SIGNAL ;
    PORT
      LAYER M4 ;
        RECT  0 8.496 0.084 8.52 ;
    END
  END rank_i[2]
  PIN rank_i[3]
    DIRECTION INPUT ;
    USE SIGNAL ;
    PORT
      LAYER M4 ;
        RECT  0 8.592 0.084 8.616 ;
    END
  END rank_i[3]
  PIN rank_i[4]
    DIRECTION INPUT ;
    USE SIGNAL ;
    PORT
      LAYER M4 ;
        RECT  0 8.688 0.084 8.712 ;
    END
  END rank_i[4]
  PIN rank_i[5]
    DIRECTION INPUT ;
    USE SIGNAL ;
    PORT
      LAYER M4 ;
        RECT  0 2.16 0.084 2.184 ;
    END
  END rank_i[5]
  PIN rank_i[6]
    DIRECTION INPUT ;
    USE SIGNAL ;
    PORT
      LAYER M4 ;
        RECT  0 2.256 0.084 2.28 ;
    END
  END rank_i[6]
  PIN rg_gnt
    DIRECTION INPUT ;
    USE SIGNAL ;
    PORT
      LAYER M5 ;
        RECT  9.936 0 9.96 0.084 ;
    END
  END rg_gnt
  PIN rst_n
    DIRECTION INPUT ;
    USE SIGNAL ;
    PORT
      LAYER M4 ;
        RECT  0 2.352 0.084 2.376 ;
    END
  END rst_n
  PIN run
    DIRECTION INPUT ;
    USE SIGNAL ;
    PORT
      LAYER M4 ;
        RECT  0 2.448 0.084 2.472 ;
    END
  END run
  PIN start
    DIRECTION INPUT ;
    USE SIGNAL ;
    PORT
      LAYER M4 ;
        RECT  0 2.544 0.084 2.568 ;
    END
  END start
  PIN wrq[0]
    DIRECTION OUTPUT ;
    USE SIGNAL ;
    PORT
      LAYER M5 ;
        RECT  10.032 0 10.056 0.084 ;
    END
  END wrq[0]
  PIN wrq[10]
    DIRECTION OUTPUT ;
    USE SIGNAL ;
    PORT
      LAYER M5 ;
        RECT  10.992 0 11.016 0.084 ;
    END
  END wrq[10]
  PIN wrq[11]
    DIRECTION OUTPUT ;
    USE SIGNAL ;
    PORT
      LAYER M5 ;
        RECT  11.088 0 11.112 0.084 ;
    END
  END wrq[11]
  PIN wrq[12]
    DIRECTION OUTPUT ;
    USE SIGNAL ;
    PORT
      LAYER M5 ;
        RECT  11.184 0 11.208 0.084 ;
    END
  END wrq[12]
  PIN wrq[13]
    DIRECTION OUTPUT ;
    USE SIGNAL ;
    PORT
      LAYER M5 ;
        RECT  11.28 0 11.304 0.084 ;
    END
  END wrq[13]
  PIN wrq[14]
    DIRECTION OUTPUT ;
    USE SIGNAL ;
    PORT
      LAYER M5 ;
        RECT  11.376 0 11.4 0.084 ;
    END
  END wrq[14]
  PIN wrq[15]
    DIRECTION OUTPUT ;
    USE SIGNAL ;
    PORT
      LAYER M5 ;
        RECT  11.472 0 11.496 0.084 ;
    END
  END wrq[15]
  PIN wrq[1]
    DIRECTION OUTPUT ;
    USE SIGNAL ;
    PORT
      LAYER M5 ;
        RECT  10.128 0 10.152 0.084 ;
    END
  END wrq[1]
  PIN wrq[2]
    DIRECTION OUTPUT ;
    USE SIGNAL ;
    PORT
      LAYER M5 ;
        RECT  10.224 0 10.248 0.084 ;
    END
  END wrq[2]
  PIN wrq[3]
    DIRECTION OUTPUT ;
    USE SIGNAL ;
    PORT
      LAYER M5 ;
        RECT  10.32 0 10.344 0.084 ;
    END
  END wrq[3]
  PIN wrq[4]
    DIRECTION OUTPUT ;
    USE SIGNAL ;
    PORT
      LAYER M5 ;
        RECT  10.416 0 10.44 0.084 ;
    END
  END wrq[4]
  PIN wrq[5]
    DIRECTION OUTPUT ;
    USE SIGNAL ;
    PORT
      LAYER M5 ;
        RECT  10.512 0 10.536 0.084 ;
    END
  END wrq[5]
  PIN wrq[6]
    DIRECTION OUTPUT ;
    USE SIGNAL ;
    PORT
      LAYER M5 ;
        RECT  10.608 0 10.632 0.084 ;
    END
  END wrq[6]
  PIN wrq[7]
    DIRECTION OUTPUT ;
    USE SIGNAL ;
    PORT
      LAYER M5 ;
        RECT  10.704 0 10.728 0.084 ;
    END
  END wrq[7]
  PIN wrq[8]
    DIRECTION OUTPUT ;
    USE SIGNAL ;
    PORT
      LAYER M5 ;
        RECT  10.8 0 10.824 0.084 ;
    END
  END wrq[8]
  PIN wrq[9]
    DIRECTION OUTPUT ;
    USE SIGNAL ;
    PORT
      LAYER M5 ;
        RECT  10.896 0 10.92 0.084 ;
    END
  END wrq[9]
  PIN wrq_cr
    DIRECTION INPUT ;
    USE SIGNAL ;
    PORT
      LAYER M5 ;
        RECT  11.568 0 11.592 0.084 ;
    END
  END wrq_cr
  PIN wrr[0]
    DIRECTION INPUT ;
    USE SIGNAL ;
    PORT
      LAYER M5 ;
        RECT  11.664 0 11.688 0.084 ;
    END
  END wrr[0]
  PIN wrr[100]
    DIRECTION INPUT ;
    USE SIGNAL ;
    PORT
      LAYER M3 ;
        RECT  35.532 0 35.55 0.037 ;
    END
  END wrr[100]
  PIN wrr[101]
    DIRECTION INPUT ;
    USE SIGNAL ;
    PORT
      LAYER M3 ;
        RECT  35.604 0 35.622 0.037 ;
    END
  END wrr[101]
  PIN wrr[102]
    DIRECTION INPUT ;
    USE SIGNAL ;
    PORT
      LAYER M3 ;
        RECT  35.676 0 35.694 0.037 ;
    END
  END wrr[102]
  PIN wrr[103]
    DIRECTION INPUT ;
    USE SIGNAL ;
    PORT
      LAYER M3 ;
        RECT  35.748 0 35.766 0.037 ;
    END
  END wrr[103]
  PIN wrr[104]
    DIRECTION INPUT ;
    USE SIGNAL ;
    PORT
      LAYER M3 ;
        RECT  35.82 0 35.838 0.037 ;
    END
  END wrr[104]
  PIN wrr[105]
    DIRECTION INPUT ;
    USE SIGNAL ;
    PORT
      LAYER M3 ;
        RECT  35.892 0 35.91 0.037 ;
    END
  END wrr[105]
  PIN wrr[106]
    DIRECTION INPUT ;
    USE SIGNAL ;
    PORT
      LAYER M3 ;
        RECT  35.964 0 35.982 0.037 ;
    END
  END wrr[106]
  PIN wrr[107]
    DIRECTION INPUT ;
    USE SIGNAL ;
    PORT
      LAYER M3 ;
        RECT  36.036 0 36.054 0.037 ;
    END
  END wrr[107]
  PIN wrr[108]
    DIRECTION INPUT ;
    USE SIGNAL ;
    PORT
      LAYER M3 ;
        RECT  36.108 0 36.126 0.037 ;
    END
  END wrr[108]
  PIN wrr[109]
    DIRECTION INPUT ;
    USE SIGNAL ;
    PORT
      LAYER M3 ;
        RECT  36.18 0 36.198 0.037 ;
    END
  END wrr[109]
  PIN wrr[10]
    DIRECTION INPUT ;
    USE SIGNAL ;
    PORT
      LAYER M5 ;
        RECT  12.624 0 12.648 0.084 ;
    END
  END wrr[10]
  PIN wrr[110]
    DIRECTION INPUT ;
    USE SIGNAL ;
    PORT
      LAYER M5 ;
        RECT  58.32 0 58.344 0.084 ;
    END
  END wrr[110]
  PIN wrr[111]
    DIRECTION INPUT ;
    USE SIGNAL ;
    PORT
      LAYER M5 ;
        RECT  58.416 0 58.44 0.084 ;
    END
  END wrr[111]
  PIN wrr[112]
    DIRECTION INPUT ;
    USE SIGNAL ;
    PORT
      LAYER M5 ;
        RECT  58.512 0 58.536 0.084 ;
    END
  END wrr[112]
  PIN wrr[113]
    DIRECTION INPUT ;
    USE SIGNAL ;
    PORT
      LAYER M5 ;
        RECT  58.608 0 58.632 0.084 ;
    END
  END wrr[113]
  PIN wrr[114]
    DIRECTION INPUT ;
    USE SIGNAL ;
    PORT
      LAYER M5 ;
        RECT  58.704 0 58.728 0.084 ;
    END
  END wrr[114]
  PIN wrr[115]
    DIRECTION INPUT ;
    USE SIGNAL ;
    PORT
      LAYER M5 ;
        RECT  58.8 0 58.824 0.084 ;
    END
  END wrr[115]
  PIN wrr[116]
    DIRECTION INPUT ;
    USE SIGNAL ;
    PORT
      LAYER M5 ;
        RECT  58.896 0 58.92 0.084 ;
    END
  END wrr[116]
  PIN wrr[117]
    DIRECTION INPUT ;
    USE SIGNAL ;
    PORT
      LAYER M5 ;
        RECT  58.992 0 59.016 0.084 ;
    END
  END wrr[117]
  PIN wrr[118]
    DIRECTION INPUT ;
    USE SIGNAL ;
    PORT
      LAYER M5 ;
        RECT  59.088 0 59.112 0.084 ;
    END
  END wrr[118]
  PIN wrr[119]
    DIRECTION INPUT ;
    USE SIGNAL ;
    PORT
      LAYER M5 ;
        RECT  59.184 0 59.208 0.084 ;
    END
  END wrr[119]
  PIN wrr[11]
    DIRECTION INPUT ;
    USE SIGNAL ;
    PORT
      LAYER M5 ;
        RECT  12.72 0 12.744 0.084 ;
    END
  END wrr[11]
  PIN wrr[120]
    DIRECTION INPUT ;
    USE SIGNAL ;
    PORT
      LAYER M5 ;
        RECT  59.28 0 59.304 0.084 ;
    END
  END wrr[120]
  PIN wrr[121]
    DIRECTION INPUT ;
    USE SIGNAL ;
    PORT
      LAYER M5 ;
        RECT  59.376 0 59.4 0.084 ;
    END
  END wrr[121]
  PIN wrr[122]
    DIRECTION INPUT ;
    USE SIGNAL ;
    PORT
      LAYER M5 ;
        RECT  59.472 0 59.496 0.084 ;
    END
  END wrr[122]
  PIN wrr[123]
    DIRECTION INPUT ;
    USE SIGNAL ;
    PORT
      LAYER M5 ;
        RECT  59.568 0 59.592 0.084 ;
    END
  END wrr[123]
  PIN wrr[124]
    DIRECTION INPUT ;
    USE SIGNAL ;
    PORT
      LAYER M5 ;
        RECT  59.664 0 59.688 0.084 ;
    END
  END wrr[124]
  PIN wrr[125]
    DIRECTION INPUT ;
    USE SIGNAL ;
    PORT
      LAYER M5 ;
        RECT  59.76 0 59.784 0.084 ;
    END
  END wrr[125]
  PIN wrr[126]
    DIRECTION INPUT ;
    USE SIGNAL ;
    PORT
      LAYER M5 ;
        RECT  59.856 0 59.88 0.084 ;
    END
  END wrr[126]
  PIN wrr[127]
    DIRECTION INPUT ;
    USE SIGNAL ;
    PORT
      LAYER M5 ;
        RECT  59.952 0 59.976 0.084 ;
    END
  END wrr[127]
  PIN wrr[128]
    DIRECTION INPUT ;
    USE SIGNAL ;
    PORT
      LAYER M5 ;
        RECT  60.048 0 60.072 0.084 ;
    END
  END wrr[128]
  PIN wrr[129]
    DIRECTION INPUT ;
    USE SIGNAL ;
    PORT
      LAYER M5 ;
        RECT  60.144 0 60.168 0.084 ;
    END
  END wrr[129]
  PIN wrr[12]
    DIRECTION INPUT ;
    USE SIGNAL ;
    PORT
      LAYER M5 ;
        RECT  12.816 0 12.84 0.084 ;
    END
  END wrr[12]
  PIN wrr[130]
    DIRECTION INPUT ;
    USE SIGNAL ;
    PORT
      LAYER M5 ;
        RECT  60.24 0 60.264 0.084 ;
    END
  END wrr[130]
  PIN wrr[131]
    DIRECTION INPUT ;
    USE SIGNAL ;
    PORT
      LAYER M5 ;
        RECT  60.336 0 60.36 0.084 ;
    END
  END wrr[131]
  PIN wrr[132]
    DIRECTION INPUT ;
    USE SIGNAL ;
    PORT
      LAYER M5 ;
        RECT  60.432 0 60.456 0.084 ;
    END
  END wrr[132]
  PIN wrr[133]
    DIRECTION INPUT ;
    USE SIGNAL ;
    PORT
      LAYER M5 ;
        RECT  60.528 0 60.552 0.084 ;
    END
  END wrr[133]
  PIN wrr[134]
    DIRECTION INPUT ;
    USE SIGNAL ;
    PORT
      LAYER M5 ;
        RECT  60.624 0 60.648 0.084 ;
    END
  END wrr[134]
  PIN wrr[135]
    DIRECTION INPUT ;
    USE SIGNAL ;
    PORT
      LAYER M5 ;
        RECT  60.72 0 60.744 0.084 ;
    END
  END wrr[135]
  PIN wrr[136]
    DIRECTION INPUT ;
    USE SIGNAL ;
    PORT
      LAYER M5 ;
        RECT  60.816 0 60.84 0.084 ;
    END
  END wrr[136]
  PIN wrr[137]
    DIRECTION INPUT ;
    USE SIGNAL ;
    PORT
      LAYER M5 ;
        RECT  60.912 0 60.936 0.084 ;
    END
  END wrr[137]
  PIN wrr[138]
    DIRECTION INPUT ;
    USE SIGNAL ;
    PORT
      LAYER M5 ;
        RECT  61.008 0 61.032 0.084 ;
    END
  END wrr[138]
  PIN wrr[139]
    DIRECTION INPUT ;
    USE SIGNAL ;
    PORT
      LAYER M5 ;
        RECT  61.104 0 61.128 0.084 ;
    END
  END wrr[139]
  PIN wrr[13]
    DIRECTION INPUT ;
    USE SIGNAL ;
    PORT
      LAYER M5 ;
        RECT  12.912 0 12.936 0.084 ;
    END
  END wrr[13]
  PIN wrr[140]
    DIRECTION INPUT ;
    USE SIGNAL ;
    PORT
      LAYER M5 ;
        RECT  61.2 0 61.224 0.084 ;
    END
  END wrr[140]
  PIN wrr[141]
    DIRECTION INPUT ;
    USE SIGNAL ;
    PORT
      LAYER M5 ;
        RECT  61.296 0 61.32 0.084 ;
    END
  END wrr[141]
  PIN wrr[142]
    DIRECTION INPUT ;
    USE SIGNAL ;
    PORT
      LAYER M5 ;
        RECT  45.264 0 45.288 0.084 ;
    END
  END wrr[142]
  PIN wrr[143]
    DIRECTION INPUT ;
    USE SIGNAL ;
    PORT
      LAYER M5 ;
        RECT  45.36 0 45.384 0.084 ;
    END
  END wrr[143]
  PIN wrr[144]
    DIRECTION INPUT ;
    USE SIGNAL ;
    PORT
      LAYER M5 ;
        RECT  45.456 0 45.48 0.084 ;
    END
  END wrr[144]
  PIN wrr[145]
    DIRECTION INPUT ;
    USE SIGNAL ;
    PORT
      LAYER M5 ;
        RECT  45.552 0 45.576 0.084 ;
    END
  END wrr[145]
  PIN wrr[146]
    DIRECTION INPUT ;
    USE SIGNAL ;
    PORT
      LAYER M5 ;
        RECT  45.648 0 45.672 0.084 ;
    END
  END wrr[146]
  PIN wrr[147]
    DIRECTION INPUT ;
    USE SIGNAL ;
    PORT
      LAYER M5 ;
        RECT  45.744 0 45.768 0.084 ;
    END
  END wrr[147]
  PIN wrr[148]
    DIRECTION INPUT ;
    USE SIGNAL ;
    PORT
      LAYER M5 ;
        RECT  45.84 0 45.864 0.084 ;
    END
  END wrr[148]
  PIN wrr[149]
    DIRECTION INPUT ;
    USE SIGNAL ;
    PORT
      LAYER M5 ;
        RECT  45.936 0 45.96 0.084 ;
    END
  END wrr[149]
  PIN wrr[14]
    DIRECTION INPUT ;
    USE SIGNAL ;
    PORT
      LAYER M3 ;
        RECT  17.244 0 17.262 0.037 ;
    END
  END wrr[14]
  PIN wrr[150]
    DIRECTION INPUT ;
    USE SIGNAL ;
    PORT
      LAYER M5 ;
        RECT  46.032 0 46.056 0.084 ;
    END
  END wrr[150]
  PIN wrr[151]
    DIRECTION INPUT ;
    USE SIGNAL ;
    PORT
      LAYER M5 ;
        RECT  46.128 0 46.152 0.084 ;
    END
  END wrr[151]
  PIN wrr[152]
    DIRECTION INPUT ;
    USE SIGNAL ;
    PORT
      LAYER M5 ;
        RECT  46.224 0 46.248 0.084 ;
    END
  END wrr[152]
  PIN wrr[153]
    DIRECTION INPUT ;
    USE SIGNAL ;
    PORT
      LAYER M5 ;
        RECT  46.32 0 46.344 0.084 ;
    END
  END wrr[153]
  PIN wrr[154]
    DIRECTION INPUT ;
    USE SIGNAL ;
    PORT
      LAYER M5 ;
        RECT  46.416 0 46.44 0.084 ;
    END
  END wrr[154]
  PIN wrr[155]
    DIRECTION INPUT ;
    USE SIGNAL ;
    PORT
      LAYER M5 ;
        RECT  46.512 0 46.536 0.084 ;
    END
  END wrr[155]
  PIN wrr[156]
    DIRECTION INPUT ;
    USE SIGNAL ;
    PORT
      LAYER M5 ;
        RECT  46.608 0 46.632 0.084 ;
    END
  END wrr[156]
  PIN wrr[157]
    DIRECTION INPUT ;
    USE SIGNAL ;
    PORT
      LAYER M5 ;
        RECT  46.704 0 46.728 0.084 ;
    END
  END wrr[157]
  PIN wrr[158]
    DIRECTION INPUT ;
    USE SIGNAL ;
    PORT
      LAYER M5 ;
        RECT  46.8 0 46.824 0.084 ;
    END
  END wrr[158]
  PIN wrr[159]
    DIRECTION INPUT ;
    USE SIGNAL ;
    PORT
      LAYER M5 ;
        RECT  46.896 0 46.92 0.084 ;
    END
  END wrr[159]
  PIN wrr[15]
    DIRECTION INPUT ;
    USE SIGNAL ;
    PORT
      LAYER M3 ;
        RECT  17.316 0 17.334 0.037 ;
    END
  END wrr[15]
  PIN wrr[160]
    DIRECTION INPUT ;
    USE SIGNAL ;
    PORT
      LAYER M5 ;
        RECT  46.992 0 47.016 0.084 ;
    END
  END wrr[160]
  PIN wrr[161]
    DIRECTION INPUT ;
    USE SIGNAL ;
    PORT
      LAYER M5 ;
        RECT  47.088 0 47.112 0.084 ;
    END
  END wrr[161]
  PIN wrr[162]
    DIRECTION INPUT ;
    USE SIGNAL ;
    PORT
      LAYER M5 ;
        RECT  47.184 0 47.208 0.084 ;
    END
  END wrr[162]
  PIN wrr[163]
    DIRECTION INPUT ;
    USE SIGNAL ;
    PORT
      LAYER M5 ;
        RECT  47.28 0 47.304 0.084 ;
    END
  END wrr[163]
  PIN wrr[164]
    DIRECTION INPUT ;
    USE SIGNAL ;
    PORT
      LAYER M5 ;
        RECT  47.376 0 47.4 0.084 ;
    END
  END wrr[164]
  PIN wrr[165]
    DIRECTION INPUT ;
    USE SIGNAL ;
    PORT
      LAYER M5 ;
        RECT  47.472 0 47.496 0.084 ;
    END
  END wrr[165]
  PIN wrr[166]
    DIRECTION INPUT ;
    USE SIGNAL ;
    PORT
      LAYER M5 ;
        RECT  47.568 0 47.592 0.084 ;
    END
  END wrr[166]
  PIN wrr[167]
    DIRECTION INPUT ;
    USE SIGNAL ;
    PORT
      LAYER M5 ;
        RECT  47.664 0 47.688 0.084 ;
    END
  END wrr[167]
  PIN wrr[168]
    DIRECTION INPUT ;
    USE SIGNAL ;
    PORT
      LAYER M5 ;
        RECT  47.76 0 47.784 0.084 ;
    END
  END wrr[168]
  PIN wrr[169]
    DIRECTION INPUT ;
    USE SIGNAL ;
    PORT
      LAYER M5 ;
        RECT  47.856 0 47.88 0.084 ;
    END
  END wrr[169]
  PIN wrr[16]
    DIRECTION INPUT ;
    USE SIGNAL ;
    PORT
      LAYER M3 ;
        RECT  17.388 0 17.406 0.037 ;
    END
  END wrr[16]
  PIN wrr[170]
    DIRECTION INPUT ;
    USE SIGNAL ;
    PORT
      LAYER M5 ;
        RECT  47.952 0 47.976 0.084 ;
    END
  END wrr[170]
  PIN wrr[171]
    DIRECTION INPUT ;
    USE SIGNAL ;
    PORT
      LAYER M5 ;
        RECT  48.048 0 48.072 0.084 ;
    END
  END wrr[171]
  PIN wrr[172]
    DIRECTION INPUT ;
    USE SIGNAL ;
    PORT
      LAYER M5 ;
        RECT  48.144 0 48.168 0.084 ;
    END
  END wrr[172]
  PIN wrr[173]
    DIRECTION INPUT ;
    USE SIGNAL ;
    PORT
      LAYER M5 ;
        RECT  48.24 0 48.264 0.084 ;
    END
  END wrr[173]
  PIN wrr[174]
    DIRECTION INPUT ;
    USE SIGNAL ;
    PORT
      LAYER M5 ;
        RECT  32.208 0 32.232 0.084 ;
    END
  END wrr[174]
  PIN wrr[175]
    DIRECTION INPUT ;
    USE SIGNAL ;
    PORT
      LAYER M5 ;
        RECT  32.304 0 32.328 0.084 ;
    END
  END wrr[175]
  PIN wrr[176]
    DIRECTION INPUT ;
    USE SIGNAL ;
    PORT
      LAYER M5 ;
        RECT  32.4 0 32.424 0.084 ;
    END
  END wrr[176]
  PIN wrr[177]
    DIRECTION INPUT ;
    USE SIGNAL ;
    PORT
      LAYER M5 ;
        RECT  32.496 0 32.52 0.084 ;
    END
  END wrr[177]
  PIN wrr[178]
    DIRECTION INPUT ;
    USE SIGNAL ;
    PORT
      LAYER M5 ;
        RECT  32.592 0 32.616 0.084 ;
    END
  END wrr[178]
  PIN wrr[179]
    DIRECTION INPUT ;
    USE SIGNAL ;
    PORT
      LAYER M5 ;
        RECT  32.688 0 32.712 0.084 ;
    END
  END wrr[179]
  PIN wrr[17]
    DIRECTION INPUT ;
    USE SIGNAL ;
    PORT
      LAYER M3 ;
        RECT  17.46 0 17.478 0.037 ;
    END
  END wrr[17]
  PIN wrr[180]
    DIRECTION INPUT ;
    USE SIGNAL ;
    PORT
      LAYER M5 ;
        RECT  32.784 0 32.808 0.084 ;
    END
  END wrr[180]
  PIN wrr[181]
    DIRECTION INPUT ;
    USE SIGNAL ;
    PORT
      LAYER M5 ;
        RECT  32.88 0 32.904 0.084 ;
    END
  END wrr[181]
  PIN wrr[182]
    DIRECTION INPUT ;
    USE SIGNAL ;
    PORT
      LAYER M5 ;
        RECT  32.976 0 33 0.084 ;
    END
  END wrr[182]
  PIN wrr[183]
    DIRECTION INPUT ;
    USE SIGNAL ;
    PORT
      LAYER M5 ;
        RECT  33.072 0 33.096 0.084 ;
    END
  END wrr[183]
  PIN wrr[184]
    DIRECTION INPUT ;
    USE SIGNAL ;
    PORT
      LAYER M5 ;
        RECT  33.168 0 33.192 0.084 ;
    END
  END wrr[184]
  PIN wrr[185]
    DIRECTION INPUT ;
    USE SIGNAL ;
    PORT
      LAYER M5 ;
        RECT  33.264 0 33.288 0.084 ;
    END
  END wrr[185]
  PIN wrr[186]
    DIRECTION INPUT ;
    USE SIGNAL ;
    PORT
      LAYER M5 ;
        RECT  33.36 0 33.384 0.084 ;
    END
  END wrr[186]
  PIN wrr[187]
    DIRECTION INPUT ;
    USE SIGNAL ;
    PORT
      LAYER M5 ;
        RECT  33.456 0 33.48 0.084 ;
    END
  END wrr[187]
  PIN wrr[188]
    DIRECTION INPUT ;
    USE SIGNAL ;
    PORT
      LAYER M5 ;
        RECT  33.552 0 33.576 0.084 ;
    END
  END wrr[188]
  PIN wrr[189]
    DIRECTION INPUT ;
    USE SIGNAL ;
    PORT
      LAYER M5 ;
        RECT  33.648 0 33.672 0.084 ;
    END
  END wrr[189]
  PIN wrr[18]
    DIRECTION INPUT ;
    USE SIGNAL ;
    PORT
      LAYER M3 ;
        RECT  17.532 0 17.55 0.037 ;
    END
  END wrr[18]
  PIN wrr[190]
    DIRECTION INPUT ;
    USE SIGNAL ;
    PORT
      LAYER M5 ;
        RECT  33.744 0 33.768 0.084 ;
    END
  END wrr[190]
  PIN wrr[191]
    DIRECTION INPUT ;
    USE SIGNAL ;
    PORT
      LAYER M5 ;
        RECT  33.84 0 33.864 0.084 ;
    END
  END wrr[191]
  PIN wrr[192]
    DIRECTION INPUT ;
    USE SIGNAL ;
    PORT
      LAYER M5 ;
        RECT  33.936 0 33.96 0.084 ;
    END
  END wrr[192]
  PIN wrr[193]
    DIRECTION INPUT ;
    USE SIGNAL ;
    PORT
      LAYER M5 ;
        RECT  34.032 0 34.056 0.084 ;
    END
  END wrr[193]
  PIN wrr[194]
    DIRECTION INPUT ;
    USE SIGNAL ;
    PORT
      LAYER M5 ;
        RECT  34.128 0 34.152 0.084 ;
    END
  END wrr[194]
  PIN wrr[195]
    DIRECTION INPUT ;
    USE SIGNAL ;
    PORT
      LAYER M5 ;
        RECT  34.224 0 34.248 0.084 ;
    END
  END wrr[195]
  PIN wrr[196]
    DIRECTION INPUT ;
    USE SIGNAL ;
    PORT
      LAYER M5 ;
        RECT  34.32 0 34.344 0.084 ;
    END
  END wrr[196]
  PIN wrr[197]
    DIRECTION INPUT ;
    USE SIGNAL ;
    PORT
      LAYER M5 ;
        RECT  34.416 0 34.44 0.084 ;
    END
  END wrr[197]
  PIN wrr[198]
    DIRECTION INPUT ;
    USE SIGNAL ;
    PORT
      LAYER M5 ;
        RECT  34.512 0 34.536 0.084 ;
    END
  END wrr[198]
  PIN wrr[199]
    DIRECTION INPUT ;
    USE SIGNAL ;
    PORT
      LAYER M5 ;
        RECT  34.608 0 34.632 0.084 ;
    END
  END wrr[199]
  PIN wrr[19]
    DIRECTION INPUT ;
    USE SIGNAL ;
    PORT
      LAYER M3 ;
        RECT  17.604 0 17.622 0.037 ;
    END
  END wrr[19]
  PIN wrr[1]
    DIRECTION INPUT ;
    USE SIGNAL ;
    PORT
      LAYER M5 ;
        RECT  11.76 0 11.784 0.084 ;
    END
  END wrr[1]
  PIN wrr[200]
    DIRECTION INPUT ;
    USE SIGNAL ;
    PORT
      LAYER M5 ;
        RECT  34.704 0 34.728 0.084 ;
    END
  END wrr[200]
  PIN wrr[201]
    DIRECTION INPUT ;
    USE SIGNAL ;
    PORT
      LAYER M5 ;
        RECT  34.8 0 34.824 0.084 ;
    END
  END wrr[201]
  PIN wrr[202]
    DIRECTION INPUT ;
    USE SIGNAL ;
    PORT
      LAYER M5 ;
        RECT  34.896 0 34.92 0.084 ;
    END
  END wrr[202]
  PIN wrr[203]
    DIRECTION INPUT ;
    USE SIGNAL ;
    PORT
      LAYER M5 ;
        RECT  34.992 0 35.016 0.084 ;
    END
  END wrr[203]
  PIN wrr[204]
    DIRECTION INPUT ;
    USE SIGNAL ;
    PORT
      LAYER M5 ;
        RECT  35.088 0 35.112 0.084 ;
    END
  END wrr[204]
  PIN wrr[205]
    DIRECTION INPUT ;
    USE SIGNAL ;
    PORT
      LAYER M5 ;
        RECT  35.184 0 35.208 0.084 ;
    END
  END wrr[205]
  PIN wrr[206]
    DIRECTION INPUT ;
    USE SIGNAL ;
    PORT
      LAYER M5 ;
        RECT  16.08 0 16.104 0.084 ;
    END
  END wrr[206]
  PIN wrr[207]
    DIRECTION INPUT ;
    USE SIGNAL ;
    PORT
      LAYER M5 ;
        RECT  16.176 0 16.2 0.084 ;
    END
  END wrr[207]
  PIN wrr[208]
    DIRECTION INPUT ;
    USE SIGNAL ;
    PORT
      LAYER M5 ;
        RECT  16.272 0 16.296 0.084 ;
    END
  END wrr[208]
  PIN wrr[209]
    DIRECTION INPUT ;
    USE SIGNAL ;
    PORT
      LAYER M5 ;
        RECT  16.368 0 16.392 0.084 ;
    END
  END wrr[209]
  PIN wrr[20]
    DIRECTION INPUT ;
    USE SIGNAL ;
    PORT
      LAYER M3 ;
        RECT  17.676 0 17.694 0.037 ;
    END
  END wrr[20]
  PIN wrr[210]
    DIRECTION INPUT ;
    USE SIGNAL ;
    PORT
      LAYER M5 ;
        RECT  16.464 0 16.488 0.084 ;
    END
  END wrr[210]
  PIN wrr[211]
    DIRECTION INPUT ;
    USE SIGNAL ;
    PORT
      LAYER M5 ;
        RECT  16.56 0 16.584 0.084 ;
    END
  END wrr[211]
  PIN wrr[212]
    DIRECTION INPUT ;
    USE SIGNAL ;
    PORT
      LAYER M5 ;
        RECT  16.656 0 16.68 0.084 ;
    END
  END wrr[212]
  PIN wrr[213]
    DIRECTION INPUT ;
    USE SIGNAL ;
    PORT
      LAYER M5 ;
        RECT  16.752 0 16.776 0.084 ;
    END
  END wrr[213]
  PIN wrr[214]
    DIRECTION INPUT ;
    USE SIGNAL ;
    PORT
      LAYER M5 ;
        RECT  16.848 0 16.872 0.084 ;
    END
  END wrr[214]
  PIN wrr[215]
    DIRECTION INPUT ;
    USE SIGNAL ;
    PORT
      LAYER M5 ;
        RECT  16.944 0 16.968 0.084 ;
    END
  END wrr[215]
  PIN wrr[216]
    DIRECTION INPUT ;
    USE SIGNAL ;
    PORT
      LAYER M5 ;
        RECT  17.04 0 17.064 0.084 ;
    END
  END wrr[216]
  PIN wrr[217]
    DIRECTION INPUT ;
    USE SIGNAL ;
    PORT
      LAYER M5 ;
        RECT  17.136 0 17.16 0.084 ;
    END
  END wrr[217]
  PIN wrr[218]
    DIRECTION INPUT ;
    USE SIGNAL ;
    PORT
      LAYER M5 ;
        RECT  17.232 0 17.256 0.084 ;
    END
  END wrr[218]
  PIN wrr[219]
    DIRECTION INPUT ;
    USE SIGNAL ;
    PORT
      LAYER M5 ;
        RECT  17.328 0 17.352 0.084 ;
    END
  END wrr[219]
  PIN wrr[21]
    DIRECTION INPUT ;
    USE SIGNAL ;
    PORT
      LAYER M3 ;
        RECT  17.748 0 17.766 0.037 ;
    END
  END wrr[21]
  PIN wrr[220]
    DIRECTION INPUT ;
    USE SIGNAL ;
    PORT
      LAYER M5 ;
        RECT  17.424 0 17.448 0.084 ;
    END
  END wrr[220]
  PIN wrr[221]
    DIRECTION INPUT ;
    USE SIGNAL ;
    PORT
      LAYER M5 ;
        RECT  17.52 0 17.544 0.084 ;
    END
  END wrr[221]
  PIN wrr[222]
    DIRECTION INPUT ;
    USE SIGNAL ;
    PORT
      LAYER M5 ;
        RECT  17.616 0 17.64 0.084 ;
    END
  END wrr[222]
  PIN wrr[223]
    DIRECTION INPUT ;
    USE SIGNAL ;
    PORT
      LAYER M5 ;
        RECT  17.712 0 17.736 0.084 ;
    END
  END wrr[223]
  PIN wrr[224]
    DIRECTION INPUT ;
    USE SIGNAL ;
    PORT
      LAYER M5 ;
        RECT  17.808 0 17.832 0.084 ;
    END
  END wrr[224]
  PIN wrr[225]
    DIRECTION INPUT ;
    USE SIGNAL ;
    PORT
      LAYER M5 ;
        RECT  17.904 0 17.928 0.084 ;
    END
  END wrr[225]
  PIN wrr[226]
    DIRECTION INPUT ;
    USE SIGNAL ;
    PORT
      LAYER M5 ;
        RECT  18 0 18.024 0.084 ;
    END
  END wrr[226]
  PIN wrr[227]
    DIRECTION INPUT ;
    USE SIGNAL ;
    PORT
      LAYER M5 ;
        RECT  18.096 0 18.12 0.084 ;
    END
  END wrr[227]
  PIN wrr[228]
    DIRECTION INPUT ;
    USE SIGNAL ;
    PORT
      LAYER M5 ;
        RECT  18.192 0 18.216 0.084 ;
    END
  END wrr[228]
  PIN wrr[229]
    DIRECTION INPUT ;
    USE SIGNAL ;
    PORT
      LAYER M5 ;
        RECT  18.288 0 18.312 0.084 ;
    END
  END wrr[229]
  PIN wrr[22]
    DIRECTION INPUT ;
    USE SIGNAL ;
    PORT
      LAYER M3 ;
        RECT  17.82 0 17.838 0.037 ;
    END
  END wrr[22]
  PIN wrr[230]
    DIRECTION INPUT ;
    USE SIGNAL ;
    PORT
      LAYER M5 ;
        RECT  18.384 0 18.408 0.084 ;
    END
  END wrr[230]
  PIN wrr[231]
    DIRECTION INPUT ;
    USE SIGNAL ;
    PORT
      LAYER M5 ;
        RECT  18.48 0 18.504 0.084 ;
    END
  END wrr[231]
  PIN wrr[232]
    DIRECTION INPUT ;
    USE SIGNAL ;
    PORT
      LAYER M5 ;
        RECT  18.576 0 18.6 0.084 ;
    END
  END wrr[232]
  PIN wrr[233]
    DIRECTION INPUT ;
    USE SIGNAL ;
    PORT
      LAYER M5 ;
        RECT  18.672 0 18.696 0.084 ;
    END
  END wrr[233]
  PIN wrr[234]
    DIRECTION INPUT ;
    USE SIGNAL ;
    PORT
      LAYER M5 ;
        RECT  18.768 0 18.792 0.084 ;
    END
  END wrr[234]
  PIN wrr[235]
    DIRECTION INPUT ;
    USE SIGNAL ;
    PORT
      LAYER M5 ;
        RECT  18.864 0 18.888 0.084 ;
    END
  END wrr[235]
  PIN wrr[236]
    DIRECTION INPUT ;
    USE SIGNAL ;
    PORT
      LAYER M5 ;
        RECT  18.96 0 18.984 0.084 ;
    END
  END wrr[236]
  PIN wrr[237]
    DIRECTION INPUT ;
    USE SIGNAL ;
    PORT
      LAYER M5 ;
        RECT  19.056 0 19.08 0.084 ;
    END
  END wrr[237]
  PIN wrr[238]
    DIRECTION INPUT ;
    USE SIGNAL ;
    PORT
      LAYER M5 ;
        RECT  13.008 0 13.032 0.084 ;
    END
  END wrr[238]
  PIN wrr[239]
    DIRECTION INPUT ;
    USE SIGNAL ;
    PORT
      LAYER M5 ;
        RECT  13.104 0 13.128 0.084 ;
    END
  END wrr[239]
  PIN wrr[23]
    DIRECTION INPUT ;
    USE SIGNAL ;
    PORT
      LAYER M3 ;
        RECT  17.892 0 17.91 0.037 ;
    END
  END wrr[23]
  PIN wrr[240]
    DIRECTION INPUT ;
    USE SIGNAL ;
    PORT
      LAYER M5 ;
        RECT  13.2 0 13.224 0.084 ;
    END
  END wrr[240]
  PIN wrr[241]
    DIRECTION INPUT ;
    USE SIGNAL ;
    PORT
      LAYER M5 ;
        RECT  13.296 0 13.32 0.084 ;
    END
  END wrr[241]
  PIN wrr[242]
    DIRECTION INPUT ;
    USE SIGNAL ;
    PORT
      LAYER M5 ;
        RECT  13.392 0 13.416 0.084 ;
    END
  END wrr[242]
  PIN wrr[243]
    DIRECTION INPUT ;
    USE SIGNAL ;
    PORT
      LAYER M5 ;
        RECT  13.488 0 13.512 0.084 ;
    END
  END wrr[243]
  PIN wrr[244]
    DIRECTION INPUT ;
    USE SIGNAL ;
    PORT
      LAYER M5 ;
        RECT  13.584 0 13.608 0.084 ;
    END
  END wrr[244]
  PIN wrr[245]
    DIRECTION INPUT ;
    USE SIGNAL ;
    PORT
      LAYER M5 ;
        RECT  13.68 0 13.704 0.084 ;
    END
  END wrr[245]
  PIN wrr[246]
    DIRECTION INPUT ;
    USE SIGNAL ;
    PORT
      LAYER M5 ;
        RECT  13.776 0 13.8 0.084 ;
    END
  END wrr[246]
  PIN wrr[247]
    DIRECTION INPUT ;
    USE SIGNAL ;
    PORT
      LAYER M5 ;
        RECT  13.872 0 13.896 0.084 ;
    END
  END wrr[247]
  PIN wrr[248]
    DIRECTION INPUT ;
    USE SIGNAL ;
    PORT
      LAYER M5 ;
        RECT  13.968 0 13.992 0.084 ;
    END
  END wrr[248]
  PIN wrr[249]
    DIRECTION INPUT ;
    USE SIGNAL ;
    PORT
      LAYER M5 ;
        RECT  14.064 0 14.088 0.084 ;
    END
  END wrr[249]
  PIN wrr[24]
    DIRECTION INPUT ;
    USE SIGNAL ;
    PORT
      LAYER M3 ;
        RECT  17.964 0 17.982 0.037 ;
    END
  END wrr[24]
  PIN wrr[250]
    DIRECTION INPUT ;
    USE SIGNAL ;
    PORT
      LAYER M5 ;
        RECT  14.16 0 14.184 0.084 ;
    END
  END wrr[250]
  PIN wrr[251]
    DIRECTION INPUT ;
    USE SIGNAL ;
    PORT
      LAYER M5 ;
        RECT  14.256 0 14.28 0.084 ;
    END
  END wrr[251]
  PIN wrr[252]
    DIRECTION INPUT ;
    USE SIGNAL ;
    PORT
      LAYER M5 ;
        RECT  14.352 0 14.376 0.084 ;
    END
  END wrr[252]
  PIN wrr[253]
    DIRECTION INPUT ;
    USE SIGNAL ;
    PORT
      LAYER M5 ;
        RECT  14.448 0 14.472 0.084 ;
    END
  END wrr[253]
  PIN wrr[254]
    DIRECTION INPUT ;
    USE SIGNAL ;
    PORT
      LAYER M5 ;
        RECT  14.544 0 14.568 0.084 ;
    END
  END wrr[254]
  PIN wrr[255]
    DIRECTION INPUT ;
    USE SIGNAL ;
    PORT
      LAYER M5 ;
        RECT  14.64 0 14.664 0.084 ;
    END
  END wrr[255]
  PIN wrr[256]
    DIRECTION INPUT ;
    USE SIGNAL ;
    PORT
      LAYER M5 ;
        RECT  14.736 0 14.76 0.084 ;
    END
  END wrr[256]
  PIN wrr[25]
    DIRECTION INPUT ;
    USE SIGNAL ;
    PORT
      LAYER M3 ;
        RECT  18.036 0 18.054 0.037 ;
    END
  END wrr[25]
  PIN wrr[26]
    DIRECTION INPUT ;
    USE SIGNAL ;
    PORT
      LAYER M3 ;
        RECT  18.108 0 18.126 0.037 ;
    END
  END wrr[26]
  PIN wrr[27]
    DIRECTION INPUT ;
    USE SIGNAL ;
    PORT
      LAYER M3 ;
        RECT  18.18 0 18.198 0.037 ;
    END
  END wrr[27]
  PIN wrr[28]
    DIRECTION INPUT ;
    USE SIGNAL ;
    PORT
      LAYER M3 ;
        RECT  18.252 0 18.27 0.037 ;
    END
  END wrr[28]
  PIN wrr[29]
    DIRECTION INPUT ;
    USE SIGNAL ;
    PORT
      LAYER M3 ;
        RECT  18.324 0 18.342 0.037 ;
    END
  END wrr[29]
  PIN wrr[2]
    DIRECTION INPUT ;
    USE SIGNAL ;
    PORT
      LAYER M5 ;
        RECT  11.856 0 11.88 0.084 ;
    END
  END wrr[2]
  PIN wrr[30]
    DIRECTION INPUT ;
    USE SIGNAL ;
    PORT
      LAYER M3 ;
        RECT  18.396 0 18.414 0.037 ;
    END
  END wrr[30]
  PIN wrr[31]
    DIRECTION INPUT ;
    USE SIGNAL ;
    PORT
      LAYER M3 ;
        RECT  18.468 0 18.486 0.037 ;
    END
  END wrr[31]
  PIN wrr[32]
    DIRECTION INPUT ;
    USE SIGNAL ;
    PORT
      LAYER M3 ;
        RECT  18.54 0 18.558 0.037 ;
    END
  END wrr[32]
  PIN wrr[33]
    DIRECTION INPUT ;
    USE SIGNAL ;
    PORT
      LAYER M3 ;
        RECT  18.612 0 18.63 0.037 ;
    END
  END wrr[33]
  PIN wrr[34]
    DIRECTION INPUT ;
    USE SIGNAL ;
    PORT
      LAYER M3 ;
        RECT  18.684 0 18.702 0.037 ;
    END
  END wrr[34]
  PIN wrr[35]
    DIRECTION INPUT ;
    USE SIGNAL ;
    PORT
      LAYER M3 ;
        RECT  18.756 0 18.774 0.037 ;
    END
  END wrr[35]
  PIN wrr[36]
    DIRECTION INPUT ;
    USE SIGNAL ;
    PORT
      LAYER M3 ;
        RECT  18.828 0 18.846 0.037 ;
    END
  END wrr[36]
  PIN wrr[37]
    DIRECTION INPUT ;
    USE SIGNAL ;
    PORT
      LAYER M3 ;
        RECT  18.9 0 18.918 0.037 ;
    END
  END wrr[37]
  PIN wrr[38]
    DIRECTION INPUT ;
    USE SIGNAL ;
    PORT
      LAYER M3 ;
        RECT  18.972 0 18.99 0.037 ;
    END
  END wrr[38]
  PIN wrr[39]
    DIRECTION INPUT ;
    USE SIGNAL ;
    PORT
      LAYER M3 ;
        RECT  19.044 0 19.062 0.037 ;
    END
  END wrr[39]
  PIN wrr[3]
    DIRECTION INPUT ;
    USE SIGNAL ;
    PORT
      LAYER M5 ;
        RECT  11.952 0 11.976 0.084 ;
    END
  END wrr[3]
  PIN wrr[40]
    DIRECTION INPUT ;
    USE SIGNAL ;
    PORT
      LAYER M3 ;
        RECT  19.116 0 19.134 0.037 ;
    END
  END wrr[40]
  PIN wrr[41]
    DIRECTION INPUT ;
    USE SIGNAL ;
    PORT
      LAYER M3 ;
        RECT  19.188 0 19.206 0.037 ;
    END
  END wrr[41]
  PIN wrr[42]
    DIRECTION INPUT ;
    USE SIGNAL ;
    PORT
      LAYER M3 ;
        RECT  19.26 0 19.278 0.037 ;
    END
  END wrr[42]
  PIN wrr[43]
    DIRECTION INPUT ;
    USE SIGNAL ;
    PORT
      LAYER M3 ;
        RECT  19.332 0 19.35 0.037 ;
    END
  END wrr[43]
  PIN wrr[44]
    DIRECTION INPUT ;
    USE SIGNAL ;
    PORT
      LAYER M3 ;
        RECT  19.404 0 19.422 0.037 ;
    END
  END wrr[44]
  PIN wrr[45]
    DIRECTION INPUT ;
    USE SIGNAL ;
    PORT
      LAYER M3 ;
        RECT  19.476 0 19.494 0.037 ;
    END
  END wrr[45]
  PIN wrr[46]
    DIRECTION INPUT ;
    USE SIGNAL ;
    PORT
      LAYER M3 ;
        RECT  36.252 0 36.27 0.037 ;
    END
  END wrr[46]
  PIN wrr[47]
    DIRECTION INPUT ;
    USE SIGNAL ;
    PORT
      LAYER M3 ;
        RECT  36.324 0 36.342 0.037 ;
    END
  END wrr[47]
  PIN wrr[48]
    DIRECTION INPUT ;
    USE SIGNAL ;
    PORT
      LAYER M3 ;
        RECT  36.396 0 36.414 0.037 ;
    END
  END wrr[48]
  PIN wrr[49]
    DIRECTION INPUT ;
    USE SIGNAL ;
    PORT
      LAYER M3 ;
        RECT  36.468 0 36.486 0.037 ;
    END
  END wrr[49]
  PIN wrr[4]
    DIRECTION INPUT ;
    USE SIGNAL ;
    PORT
      LAYER M5 ;
        RECT  12.048 0 12.072 0.084 ;
    END
  END wrr[4]
  PIN wrr[50]
    DIRECTION INPUT ;
    USE SIGNAL ;
    PORT
      LAYER M3 ;
        RECT  36.54 0 36.558 0.037 ;
    END
  END wrr[50]
  PIN wrr[51]
    DIRECTION INPUT ;
    USE SIGNAL ;
    PORT
      LAYER M3 ;
        RECT  36.612 0 36.63 0.037 ;
    END
  END wrr[51]
  PIN wrr[52]
    DIRECTION INPUT ;
    USE SIGNAL ;
    PORT
      LAYER M3 ;
        RECT  36.684 0 36.702 0.037 ;
    END
  END wrr[52]
  PIN wrr[53]
    DIRECTION INPUT ;
    USE SIGNAL ;
    PORT
      LAYER M3 ;
        RECT  36.756 0 36.774 0.037 ;
    END
  END wrr[53]
  PIN wrr[54]
    DIRECTION INPUT ;
    USE SIGNAL ;
    PORT
      LAYER M3 ;
        RECT  36.828 0 36.846 0.037 ;
    END
  END wrr[54]
  PIN wrr[55]
    DIRECTION INPUT ;
    USE SIGNAL ;
    PORT
      LAYER M3 ;
        RECT  36.9 0 36.918 0.037 ;
    END
  END wrr[55]
  PIN wrr[56]
    DIRECTION INPUT ;
    USE SIGNAL ;
    PORT
      LAYER M3 ;
        RECT  36.972 0 36.99 0.037 ;
    END
  END wrr[56]
  PIN wrr[57]
    DIRECTION INPUT ;
    USE SIGNAL ;
    PORT
      LAYER M3 ;
        RECT  37.044 0 37.062 0.037 ;
    END
  END wrr[57]
  PIN wrr[58]
    DIRECTION INPUT ;
    USE SIGNAL ;
    PORT
      LAYER M3 ;
        RECT  37.116 0 37.134 0.037 ;
    END
  END wrr[58]
  PIN wrr[59]
    DIRECTION INPUT ;
    USE SIGNAL ;
    PORT
      LAYER M3 ;
        RECT  37.188 0 37.206 0.037 ;
    END
  END wrr[59]
  PIN wrr[5]
    DIRECTION INPUT ;
    USE SIGNAL ;
    PORT
      LAYER M5 ;
        RECT  12.144 0 12.168 0.084 ;
    END
  END wrr[5]
  PIN wrr[60]
    DIRECTION INPUT ;
    USE SIGNAL ;
    PORT
      LAYER M3 ;
        RECT  37.26 0 37.278 0.037 ;
    END
  END wrr[60]
  PIN wrr[61]
    DIRECTION INPUT ;
    USE SIGNAL ;
    PORT
      LAYER M3 ;
        RECT  37.332 0 37.35 0.037 ;
    END
  END wrr[61]
  PIN wrr[62]
    DIRECTION INPUT ;
    USE SIGNAL ;
    PORT
      LAYER M3 ;
        RECT  37.404 0 37.422 0.037 ;
    END
  END wrr[62]
  PIN wrr[63]
    DIRECTION INPUT ;
    USE SIGNAL ;
    PORT
      LAYER M3 ;
        RECT  37.476 0 37.494 0.037 ;
    END
  END wrr[63]
  PIN wrr[64]
    DIRECTION INPUT ;
    USE SIGNAL ;
    PORT
      LAYER M3 ;
        RECT  37.548 0 37.566 0.037 ;
    END
  END wrr[64]
  PIN wrr[65]
    DIRECTION INPUT ;
    USE SIGNAL ;
    PORT
      LAYER M3 ;
        RECT  37.62 0 37.638 0.037 ;
    END
  END wrr[65]
  PIN wrr[66]
    DIRECTION INPUT ;
    USE SIGNAL ;
    PORT
      LAYER M3 ;
        RECT  37.692 0 37.71 0.037 ;
    END
  END wrr[66]
  PIN wrr[67]
    DIRECTION INPUT ;
    USE SIGNAL ;
    PORT
      LAYER M3 ;
        RECT  37.764 0 37.782 0.037 ;
    END
  END wrr[67]
  PIN wrr[68]
    DIRECTION INPUT ;
    USE SIGNAL ;
    PORT
      LAYER M3 ;
        RECT  37.836 0 37.854 0.037 ;
    END
  END wrr[68]
  PIN wrr[69]
    DIRECTION INPUT ;
    USE SIGNAL ;
    PORT
      LAYER M3 ;
        RECT  37.908 0 37.926 0.037 ;
    END
  END wrr[69]
  PIN wrr[6]
    DIRECTION INPUT ;
    USE SIGNAL ;
    PORT
      LAYER M5 ;
        RECT  12.24 0 12.264 0.084 ;
    END
  END wrr[6]
  PIN wrr[70]
    DIRECTION INPUT ;
    USE SIGNAL ;
    PORT
      LAYER M3 ;
        RECT  37.98 0 37.998 0.037 ;
    END
  END wrr[70]
  PIN wrr[71]
    DIRECTION INPUT ;
    USE SIGNAL ;
    PORT
      LAYER M3 ;
        RECT  38.052 0 38.07 0.037 ;
    END
  END wrr[71]
  PIN wrr[72]
    DIRECTION INPUT ;
    USE SIGNAL ;
    PORT
      LAYER M3 ;
        RECT  38.124 0 38.142 0.037 ;
    END
  END wrr[72]
  PIN wrr[73]
    DIRECTION INPUT ;
    USE SIGNAL ;
    PORT
      LAYER M3 ;
        RECT  38.196 0 38.214 0.037 ;
    END
  END wrr[73]
  PIN wrr[74]
    DIRECTION INPUT ;
    USE SIGNAL ;
    PORT
      LAYER M3 ;
        RECT  38.268 0 38.286 0.037 ;
    END
  END wrr[74]
  PIN wrr[75]
    DIRECTION INPUT ;
    USE SIGNAL ;
    PORT
      LAYER M3 ;
        RECT  38.34 0 38.358 0.037 ;
    END
  END wrr[75]
  PIN wrr[76]
    DIRECTION INPUT ;
    USE SIGNAL ;
    PORT
      LAYER M3 ;
        RECT  38.412 0 38.43 0.037 ;
    END
  END wrr[76]
  PIN wrr[77]
    DIRECTION INPUT ;
    USE SIGNAL ;
    PORT
      LAYER M3 ;
        RECT  38.484 0 38.502 0.037 ;
    END
  END wrr[77]
  PIN wrr[78]
    DIRECTION INPUT ;
    USE SIGNAL ;
    PORT
      LAYER M3 ;
        RECT  33.948 0 33.966 0.037 ;
    END
  END wrr[78]
  PIN wrr[79]
    DIRECTION INPUT ;
    USE SIGNAL ;
    PORT
      LAYER M3 ;
        RECT  34.02 0 34.038 0.037 ;
    END
  END wrr[79]
  PIN wrr[7]
    DIRECTION INPUT ;
    USE SIGNAL ;
    PORT
      LAYER M5 ;
        RECT  12.336 0 12.36 0.084 ;
    END
  END wrr[7]
  PIN wrr[80]
    DIRECTION INPUT ;
    USE SIGNAL ;
    PORT
      LAYER M3 ;
        RECT  34.092 0 34.11 0.037 ;
    END
  END wrr[80]
  PIN wrr[81]
    DIRECTION INPUT ;
    USE SIGNAL ;
    PORT
      LAYER M3 ;
        RECT  34.164 0 34.182 0.037 ;
    END
  END wrr[81]
  PIN wrr[82]
    DIRECTION INPUT ;
    USE SIGNAL ;
    PORT
      LAYER M3 ;
        RECT  34.236 0 34.254 0.037 ;
    END
  END wrr[82]
  PIN wrr[83]
    DIRECTION INPUT ;
    USE SIGNAL ;
    PORT
      LAYER M3 ;
        RECT  34.308 0 34.326 0.037 ;
    END
  END wrr[83]
  PIN wrr[84]
    DIRECTION INPUT ;
    USE SIGNAL ;
    PORT
      LAYER M3 ;
        RECT  34.38 0 34.398 0.037 ;
    END
  END wrr[84]
  PIN wrr[85]
    DIRECTION INPUT ;
    USE SIGNAL ;
    PORT
      LAYER M3 ;
        RECT  34.452 0 34.47 0.037 ;
    END
  END wrr[85]
  PIN wrr[86]
    DIRECTION INPUT ;
    USE SIGNAL ;
    PORT
      LAYER M3 ;
        RECT  34.524 0 34.542 0.037 ;
    END
  END wrr[86]
  PIN wrr[87]
    DIRECTION INPUT ;
    USE SIGNAL ;
    PORT
      LAYER M3 ;
        RECT  34.596 0 34.614 0.037 ;
    END
  END wrr[87]
  PIN wrr[88]
    DIRECTION INPUT ;
    USE SIGNAL ;
    PORT
      LAYER M3 ;
        RECT  34.668 0 34.686 0.037 ;
    END
  END wrr[88]
  PIN wrr[89]
    DIRECTION INPUT ;
    USE SIGNAL ;
    PORT
      LAYER M3 ;
        RECT  34.74 0 34.758 0.037 ;
    END
  END wrr[89]
  PIN wrr[8]
    DIRECTION INPUT ;
    USE SIGNAL ;
    PORT
      LAYER M5 ;
        RECT  12.432 0 12.456 0.084 ;
    END
  END wrr[8]
  PIN wrr[90]
    DIRECTION INPUT ;
    USE SIGNAL ;
    PORT
      LAYER M3 ;
        RECT  34.812 0 34.83 0.037 ;
    END
  END wrr[90]
  PIN wrr[91]
    DIRECTION INPUT ;
    USE SIGNAL ;
    PORT
      LAYER M3 ;
        RECT  34.884 0 34.902 0.037 ;
    END
  END wrr[91]
  PIN wrr[92]
    DIRECTION INPUT ;
    USE SIGNAL ;
    PORT
      LAYER M3 ;
        RECT  34.956 0 34.974 0.037 ;
    END
  END wrr[92]
  PIN wrr[93]
    DIRECTION INPUT ;
    USE SIGNAL ;
    PORT
      LAYER M3 ;
        RECT  35.028 0 35.046 0.037 ;
    END
  END wrr[93]
  PIN wrr[94]
    DIRECTION INPUT ;
    USE SIGNAL ;
    PORT
      LAYER M3 ;
        RECT  35.1 0 35.118 0.037 ;
    END
  END wrr[94]
  PIN wrr[95]
    DIRECTION INPUT ;
    USE SIGNAL ;
    PORT
      LAYER M3 ;
        RECT  35.172 0 35.19 0.037 ;
    END
  END wrr[95]
  PIN wrr[96]
    DIRECTION INPUT ;
    USE SIGNAL ;
    PORT
      LAYER M3 ;
        RECT  35.244 0 35.262 0.037 ;
    END
  END wrr[96]
  PIN wrr[97]
    DIRECTION INPUT ;
    USE SIGNAL ;
    PORT
      LAYER M3 ;
        RECT  35.316 0 35.334 0.037 ;
    END
  END wrr[97]
  PIN wrr[98]
    DIRECTION INPUT ;
    USE SIGNAL ;
    PORT
      LAYER M3 ;
        RECT  35.388 0 35.406 0.037 ;
    END
  END wrr[98]
  PIN wrr[99]
    DIRECTION INPUT ;
    USE SIGNAL ;
    PORT
      LAYER M3 ;
        RECT  35.46 0 35.478 0.037 ;
    END
  END wrr[99]
  PIN wrr[9]
    DIRECTION INPUT ;
    USE SIGNAL ;
    PORT
      LAYER M5 ;
        RECT  12.528 0 12.552 0.084 ;
    END
  END wrr[9]
  PIN VDD
    DIRECTION INOUT ;
    USE POWER ;
    PORT
      LAYER M5 ;
        RECT  61.992 2.151 62.112 51.849 ;
        RECT  56.592 2.151 56.712 51.849 ;
        RECT  51.192 2.151 51.312 51.849 ;
        RECT  45.792 2.151 45.912 51.849 ;
        RECT  40.392 2.151 40.512 51.849 ;
        RECT  34.992 2.151 35.112 51.849 ;
        RECT  29.592 2.151 29.712 51.849 ;
        RECT  24.192 2.151 24.312 51.849 ;
        RECT  18.792 2.151 18.912 51.849 ;
        RECT  13.392 2.151 13.512 51.849 ;
        RECT  7.992 2.151 8.112 51.849 ;
        RECT  2.592 2.151 2.712 51.849 ;
    END
  END VDD
  PIN VSS
    DIRECTION INOUT ;
    USE GROUND ;
    PORT
      LAYER M5 ;
        RECT  61.8 2.137 61.92 51.863 ;
        RECT  56.4 2.137 56.52 51.863 ;
        RECT  51 2.137 51.12 51.863 ;
        RECT  45.6 2.137 45.72 51.863 ;
        RECT  40.2 2.137 40.32 51.863 ;
        RECT  34.8 2.137 34.92 51.863 ;
        RECT  29.4 2.137 29.52 51.863 ;
        RECT  24 2.137 24.12 51.863 ;
        RECT  18.6 2.137 18.72 51.863 ;
        RECT  13.2 2.137 13.32 51.863 ;
        RECT  7.8 2.137 7.92 51.863 ;
        RECT  2.4 2.137 2.52 51.863 ;
    END
  END VSS
  # OT_OBS_CLOSED layer=M5 d_um=1.536 added=297
  OBS
    LAYER RVTN ;
     RECT  2.16 2.16 62.64 2.295 ;
     RECT  2.16 2.565 62.64 2.835 ;
     RECT  2.16 3.105 62.64 3.375 ;
     RECT  2.16 3.645 62.64 3.915 ;
     RECT  2.16 4.185 62.64 4.455 ;
     RECT  2.16 4.725 62.64 4.995 ;
     RECT  2.16 5.265 62.64 5.535 ;
     RECT  2.16 5.805 62.64 6.075 ;
     RECT  2.16 6.345 62.64 6.615 ;
     RECT  2.16 6.885 62.64 7.155 ;
     RECT  2.16 7.425 62.64 7.695 ;
     RECT  2.16 7.965 62.64 8.235 ;
     RECT  2.16 8.505 62.64 8.775 ;
     RECT  2.16 9.045 62.64 9.315 ;
     RECT  2.16 9.585 62.64 9.855 ;
     RECT  2.16 10.125 62.64 10.395 ;
     RECT  2.16 10.665 62.64 10.935 ;
     RECT  2.16 11.205 62.64 11.475 ;
     RECT  2.16 11.745 62.64 12.015 ;
     RECT  2.16 12.285 62.64 12.555 ;
     RECT  2.16 12.825 62.64 13.095 ;
     RECT  2.16 13.365 62.64 13.635 ;
     RECT  2.16 13.905 62.64 14.175 ;
     RECT  2.16 14.445 62.64 14.715 ;
     RECT  2.16 14.985 62.64 15.255 ;
     RECT  2.16 15.525 62.64 15.795 ;
     RECT  2.16 16.065 62.64 16.335 ;
     RECT  2.16 16.605 62.64 16.875 ;
     RECT  2.16 17.145 62.64 17.415 ;
     RECT  2.16 17.685 62.64 17.955 ;
     RECT  2.16 18.225 62.64 18.495 ;
     RECT  2.16 18.765 62.64 19.035 ;
     RECT  2.16 19.305 62.64 19.575 ;
     RECT  2.16 19.845 62.64 20.115 ;
     RECT  2.16 20.385 62.64 20.655 ;
     RECT  2.16 20.925 62.64 21.195 ;
     RECT  2.16 21.465 62.64 21.735 ;
     RECT  2.16 22.005 62.64 22.275 ;
     RECT  2.16 22.545 62.64 22.815 ;
     RECT  2.16 23.085 62.64 23.355 ;
     RECT  2.16 23.625 62.64 23.895 ;
     RECT  2.16 24.165 62.64 24.435 ;
     RECT  2.16 24.705 62.64 24.975 ;
     RECT  2.16 25.245 62.64 25.515 ;
     RECT  2.16 25.785 62.64 26.055 ;
     RECT  2.16 26.325 62.64 26.595 ;
     RECT  2.16 26.865 62.64 27.135 ;
     RECT  2.16 27.405 62.64 27.675 ;
     RECT  2.16 27.945 62.64 28.215 ;
     RECT  2.16 28.485 62.64 28.755 ;
     RECT  2.16 29.025 62.64 29.295 ;
     RECT  2.16 29.565 62.64 29.835 ;
     RECT  2.16 30.105 62.64 30.375 ;
     RECT  2.16 30.645 62.64 30.915 ;
     RECT  2.16 31.185 62.64 31.455 ;
     RECT  2.16 31.725 62.64 31.995 ;
     RECT  2.16 32.265 62.64 32.535 ;
     RECT  2.16 32.805 62.64 33.075 ;
     RECT  2.16 33.345 62.64 33.615 ;
     RECT  2.16 33.885 62.64 34.155 ;
     RECT  2.16 34.425 62.64 34.695 ;
     RECT  2.16 34.965 62.64 35.235 ;
     RECT  2.16 35.505 62.64 35.775 ;
     RECT  2.16 36.045 62.64 36.315 ;
     RECT  2.16 36.585 62.64 36.855 ;
     RECT  2.16 37.125 62.64 37.395 ;
     RECT  2.16 37.665 62.64 37.935 ;
     RECT  2.16 38.205 62.64 38.475 ;
     RECT  2.16 38.745 62.64 39.015 ;
     RECT  2.16 39.285 62.64 39.555 ;
     RECT  2.16 39.825 62.64 40.095 ;
     RECT  2.16 40.365 62.64 40.635 ;
     RECT  2.16 40.905 62.64 41.175 ;
     RECT  2.16 41.445 62.64 41.715 ;
     RECT  2.16 41.985 62.64 42.255 ;
     RECT  2.16 42.525 62.64 42.795 ;
     RECT  2.16 43.065 62.64 43.335 ;
     RECT  2.16 43.605 62.64 43.875 ;
     RECT  2.16 44.145 62.64 44.415 ;
     RECT  2.16 44.685 62.64 44.955 ;
     RECT  2.16 45.225 62.64 45.495 ;
     RECT  2.16 45.765 62.64 46.035 ;
     RECT  2.16 46.305 62.64 46.575 ;
     RECT  2.16 46.845 62.64 47.115 ;
     RECT  2.16 47.385 62.64 47.655 ;
     RECT  2.16 47.925 62.64 48.195 ;
     RECT  2.16 48.465 62.64 48.735 ;
     RECT  2.16 49.005 62.64 49.275 ;
     RECT  2.16 49.545 62.64 49.815 ;
     RECT  2.16 50.085 62.64 50.355 ;
     RECT  2.16 50.625 62.64 50.895 ;
     RECT  2.16 51.165 62.64 51.435 ;
     RECT  2.16 51.705 62.64 51.84 ;
    LAYER RVTP ;
     RECT  2.16 2.295 62.64 2.565 ;
     RECT  2.16 2.835 62.64 3.105 ;
     RECT  2.16 3.375 62.64 3.645 ;
     RECT  2.16 3.915 62.64 4.185 ;
     RECT  2.16 4.455 62.64 4.725 ;
     RECT  2.16 4.995 62.64 5.265 ;
     RECT  2.16 5.535 62.64 5.805 ;
     RECT  2.16 6.075 62.64 6.345 ;
     RECT  2.16 6.615 62.64 6.885 ;
     RECT  2.16 7.155 62.64 7.425 ;
     RECT  2.16 7.695 62.64 7.965 ;
     RECT  2.16 8.235 62.64 8.505 ;
     RECT  2.16 8.775 62.64 9.045 ;
     RECT  2.16 9.315 62.64 9.585 ;
     RECT  2.16 9.855 62.64 10.125 ;
     RECT  2.16 10.395 62.64 10.665 ;
     RECT  2.16 10.935 62.64 11.205 ;
     RECT  2.16 11.475 62.64 11.745 ;
     RECT  2.16 12.015 62.64 12.285 ;
     RECT  2.16 12.555 62.64 12.825 ;
     RECT  2.16 13.095 62.64 13.365 ;
     RECT  2.16 13.635 62.64 13.905 ;
     RECT  2.16 14.175 62.64 14.445 ;
     RECT  2.16 14.715 62.64 14.985 ;
     RECT  2.16 15.255 62.64 15.525 ;
     RECT  2.16 15.795 62.64 16.065 ;
     RECT  2.16 16.335 62.64 16.605 ;
     RECT  2.16 16.875 62.64 17.145 ;
     RECT  2.16 17.415 62.64 17.685 ;
     RECT  2.16 17.955 62.64 18.225 ;
     RECT  2.16 18.495 62.64 18.765 ;
     RECT  2.16 19.035 62.64 19.305 ;
     RECT  2.16 19.575 62.64 19.845 ;
     RECT  2.16 20.115 62.64 20.385 ;
     RECT  2.16 20.655 62.64 20.925 ;
     RECT  2.16 21.195 62.64 21.465 ;
     RECT  2.16 21.735 62.64 22.005 ;
     RECT  2.16 22.275 62.64 22.545 ;
     RECT  2.16 22.815 62.64 23.085 ;
     RECT  2.16 23.355 62.64 23.625 ;
     RECT  2.16 23.895 62.64 24.165 ;
     RECT  2.16 24.435 62.64 24.705 ;
     RECT  2.16 24.975 62.64 25.245 ;
     RECT  2.16 25.515 62.64 25.785 ;
     RECT  2.16 26.055 62.64 26.325 ;
     RECT  2.16 26.595 62.64 26.865 ;
     RECT  2.16 27.135 62.64 27.405 ;
     RECT  2.16 27.675 62.64 27.945 ;
     RECT  2.16 28.215 62.64 28.485 ;
     RECT  2.16 28.755 62.64 29.025 ;
     RECT  2.16 29.295 62.64 29.565 ;
     RECT  2.16 29.835 62.64 30.105 ;
     RECT  2.16 30.375 62.64 30.645 ;
     RECT  2.16 30.915 62.64 31.185 ;
     RECT  2.16 31.455 62.64 31.725 ;
     RECT  2.16 31.995 62.64 32.265 ;
     RECT  2.16 32.535 62.64 32.805 ;
     RECT  2.16 33.075 62.64 33.345 ;
     RECT  2.16 33.615 62.64 33.885 ;
     RECT  2.16 34.155 62.64 34.425 ;
     RECT  2.16 34.695 62.64 34.965 ;
     RECT  2.16 35.235 62.64 35.505 ;
     RECT  2.16 35.775 62.64 36.045 ;
     RECT  2.16 36.315 62.64 36.585 ;
     RECT  2.16 36.855 62.64 37.125 ;
     RECT  2.16 37.395 62.64 37.665 ;
     RECT  2.16 37.935 62.64 38.205 ;
     RECT  2.16 38.475 62.64 38.745 ;
     RECT  2.16 39.015 62.64 39.285 ;
     RECT  2.16 39.555 62.64 39.825 ;
     RECT  2.16 40.095 62.64 40.365 ;
     RECT  2.16 40.635 62.64 40.905 ;
     RECT  2.16 41.175 62.64 41.445 ;
     RECT  2.16 41.715 62.64 41.985 ;
     RECT  2.16 42.255 62.64 42.525 ;
     RECT  2.16 42.795 62.64 43.065 ;
     RECT  2.16 43.335 62.64 43.605 ;
     RECT  2.16 43.875 62.64 44.145 ;
     RECT  2.16 44.415 62.64 44.685 ;
     RECT  2.16 44.955 62.64 45.225 ;
     RECT  2.16 45.495 62.64 45.765 ;
     RECT  2.16 46.035 62.64 46.305 ;
     RECT  2.16 46.575 62.64 46.845 ;
     RECT  2.16 47.115 62.64 47.385 ;
     RECT  2.16 47.655 62.64 47.925 ;
     RECT  2.16 48.195 62.64 48.465 ;
     RECT  2.16 48.735 62.64 49.005 ;
     RECT  2.16 49.275 62.64 49.545 ;
     RECT  2.16 49.815 62.64 50.085 ;
     RECT  2.16 50.355 62.64 50.625 ;
     RECT  2.16 50.895 62.64 51.165 ;
     RECT  2.16 51.435 62.64 51.705 ;
    LAYER M1 ;
     RECT  2.16 2.151 62.64 51.849 ;
    LAYER M2 ;
     RECT  0.031 14.796 0.067 14.94 ;
     RECT  0.103 2.232 0.139 2.628 ;
     RECT  0.103 3.96 0.139 4.518 ;
     RECT  0.103 12.834 0.139 12.852 ;
     RECT  0.139 12.834 0.175 13.428 ;
     RECT  0.103 6.822 0.347 7.92 ;
     RECT  0.347 6.822 0.383 7.839 ;
     RECT  0.139 2.232 0.535 2.826 ;
     RECT  0.139 3.888 0.535 5.058 ;
     RECT  0.383 6.822 0.535 7.65 ;
     RECT  0.067 14.796 0.571 15.48 ;
     RECT  0.175 12.294 1.723 13.428 ;
     RECT  0.247 10.746 2.119 10.764 ;
     RECT  1.723 11.952 2.119 13.428 ;
     RECT  0.535 2.232 2.16 5.058 ;
     RECT  0.535 6.696 2.16 7.65 ;
     RECT  0.535 9.36 2.16 9.378 ;
     RECT  2.119 10.746 2.16 13.428 ;
     RECT  0.571 14.652 2.16 15.48 ;
     RECT  2.16 2.151 3.019 51.849 ;
     RECT  3.019 2.034 6.035 51.849 ;
     RECT  5.431 52.992 7.835 53.01 ;
     RECT  7.771 53.946 8.159 53.964 ;
     RECT  6.035 2.106 8.167 51.849 ;
     RECT  8.167 2.106 8.267 51.894 ;
     RECT  8.267 2.106 10.543 51.849 ;
     RECT  10.543 2.07 10.823 51.849 ;
     RECT  11.227 53.946 11.263 53.964 ;
     RECT  11.263 53.874 11.363 53.964 ;
     RECT  10.823 2.106 11.983 51.849 ;
     RECT  11.983 2.07 12.299 51.849 ;
     RECT  13.207 52.992 13.279 53.01 ;
     RECT  13.351 53.874 13.423 53.892 ;
     RECT  13.279 52.956 13.495 53.01 ;
     RECT  13.423 53.874 13.667 53.964 ;
     RECT  13.495 52.911 13.847 53.01 ;
     RECT  13.667 53.91 14.171 53.964 ;
     RECT  13.847 52.911 14.567 52.929 ;
     RECT  14.171 53.946 14.639 53.964 ;
     RECT  12.299 2.106 16.123 51.849 ;
     RECT  15.079 1.152 16.519 1.17 ;
     RECT  16.411 0.261 16.591 0.279 ;
     RECT  16.591 0.036 17.059 0.279 ;
     RECT  16.519 1.152 17.059 1.242 ;
     RECT  17.059 0.036 17.087 1.242 ;
     RECT  16.123 1.998 17.275 51.849 ;
     RECT  17.275 1.656 17.483 51.849 ;
     RECT  17.087 0.036 17.851 0.594 ;
     RECT  17.851 0.036 18.535 1.242 ;
     RECT  17.483 1.998 18.535 51.849 ;
     RECT  18.535 0.036 19.139 51.849 ;
     RECT  19.139 1.152 19.499 51.849 ;
     RECT  19.139 0.036 19.535 0.162 ;
     RECT  19.535 0.108 19.571 0.162 ;
     RECT  19.571 0.108 19.823 0.126 ;
     RECT  19.499 1.224 19.895 1.242 ;
     RECT  19.499 2.07 20.291 51.849 ;
     RECT  20.291 2.106 24.007 51.849 ;
     RECT  24.007 2.106 24.151 51.93 ;
     RECT  23.971 53.946 24.223 53.964 ;
     RECT  24.151 2.106 24.359 52.002 ;
     RECT  24.223 53.874 24.395 53.964 ;
     RECT  24.395 53.946 24.503 53.964 ;
     RECT  24.359 2.106 26.411 51.849 ;
     RECT  28.327 53.028 29.867 53.046 ;
     RECT  26.411 2.151 31.567 51.849 ;
     RECT  31.567 2.106 31.999 51.849 ;
     RECT  31.999 2.07 32.531 51.849 ;
     RECT  33.583 0.261 33.691 0.279 ;
     RECT  33.691 0.108 33.799 0.279 ;
     RECT  32.531 2.106 33.979 51.849 ;
     RECT  33.799 0.036 34.051 0.279 ;
     RECT  34.051 0.036 34.267 0.324 ;
     RECT  33.979 2.034 34.807 51.849 ;
     RECT  34.267 0.036 34.907 0.396 ;
     RECT  34.907 0.036 35.267 0.198 ;
     RECT  35.267 0.036 35.627 0.126 ;
     RECT  35.627 0.036 36.355 0.054 ;
     RECT  34.807 1.728 37.039 51.849 ;
     RECT  37.039 1.341 37.147 51.849 ;
     RECT  37.147 1.296 37.291 51.849 ;
     RECT  36.355 0.036 37.327 0.162 ;
     RECT  37.291 1.224 37.327 51.849 ;
     RECT  37.327 0.036 37.499 0.234 ;
     RECT  37.327 1.152 37.787 51.849 ;
     RECT  37.787 1.728 37.967 51.849 ;
     RECT  37.499 0.036 38.003 0.126 ;
     RECT  38.003 0.108 38.147 0.126 ;
     RECT  37.967 1.8 38.147 51.849 ;
     RECT  38.147 2.034 38.435 51.849 ;
     RECT  38.435 2.106 38.731 51.849 ;
     RECT  38.731 2.106 38.803 52.47 ;
     RECT  38.803 2.106 38.939 53.01 ;
     RECT  38.939 2.106 39.083 52.47 ;
     RECT  39.083 2.106 39.191 51.849 ;
     RECT  40.171 53.946 40.207 53.964 ;
     RECT  40.207 53.874 40.387 53.964 ;
     RECT  40.387 53.802 40.487 53.964 ;
     RECT  40.487 53.874 40.667 53.964 ;
     RECT  40.667 53.946 40.991 53.964 ;
     RECT  39.191 2.151 41.107 51.849 ;
     RECT  41.107 2.106 44.635 51.849 ;
     RECT  44.635 2.07 45.059 51.849 ;
     RECT  45.059 2.106 45.095 51.849 ;
     RECT  54.715 53.946 54.751 53.964 ;
     RECT  54.751 53.874 54.851 53.964 ;
     RECT  45.095 2.151 55.939 51.849 ;
     RECT  55.939 2.151 56.155 51.894 ;
     RECT  56.155 2.151 56.435 51.966 ;
     RECT  56.479 53.874 56.551 53.892 ;
     RECT  56.551 53.874 56.795 53.964 ;
     RECT  56.795 53.946 56.903 53.964 ;
     RECT  56.191 53.028 57.263 53.046 ;
     RECT  56.435 2.151 62.64 51.849 ;
    LAYER M3 ;
     RECT  17.244 0.012 19.494 0.031 ;
     RECT  33.948 0.012 38.502 0.031 ;
     RECT  33.804 0.031 38.502 0.077 ;
     RECT  33.804 0.077 38.43 0.091 ;
     RECT  16.596 0.031 19.53 0.103 ;
     RECT  33.768 0.091 38.43 0.103 ;
     RECT  10.008 0.091 11.034 0.139 ;
     RECT  11.916 0.091 11.934 0.139 ;
     RECT  32.688 0.091 32.706 0.139 ;
     RECT  45 0.091 45.414 0.139 ;
     RECT  61.236 0.091 61.254 0.139 ;
     RECT  44.46 0.139 45.414 0.187 ;
     RECT  16.596 0.103 19.818 0.256 ;
     RECT  33.696 0.103 38.43 0.256 ;
     RECT  32.328 0.139 32.706 0.427 ;
     RECT  47.34 0.091 47.358 0.475 ;
     RECT  48.204 0.091 48.222 0.475 ;
     RECT  15.48 0.475 15.498 0.523 ;
     RECT  16.416 0.256 19.818 0.523 ;
     RECT  33.588 0.256 38.43 0.523 ;
     RECT  47.34 0.475 48.222 0.523 ;
     RECT  10.008 0.139 11.934 0.571 ;
     RECT  12.672 0.523 12.69 0.571 ;
     RECT  31.788 0.427 32.706 0.571 ;
     RECT  33.444 0.523 38.43 0.571 ;
     RECT  44.46 0.187 45.594 0.571 ;
     RECT  46.8 0.523 48.222 0.571 ;
     RECT  57.6 0.091 57.618 0.571 ;
     RECT  58.536 0.091 59.274 0.571 ;
     RECT  12.672 0.571 14.274 1.099 ;
     RECT  57.6 0.571 59.886 1.099 ;
     RECT  15.084 0.523 15.498 1.147 ;
     RECT  16.38 0.523 19.818 1.147 ;
     RECT  15.084 1.147 19.818 1.219 ;
     RECT  9.828 0.571 11.934 1.723 ;
     RECT  12.672 1.099 14.31 1.723 ;
     RECT  15.084 1.219 19.89 1.723 ;
     RECT  44.46 0.571 48.222 1.723 ;
     RECT  57.6 1.099 60.03 1.723 ;
     RECT  61.236 0.139 61.47 1.723 ;
     RECT  9.828 1.723 19.89 2.065 ;
     RECT  3.024 2.029 3.042 2.101 ;
     RECT  6.012 2.029 6.03 2.101 ;
     RECT  31.788 0.571 38.43 2.101 ;
     RECT  3.024 2.101 3.474 2.143 ;
     RECT  57.6 1.723 61.47 2.143 ;
     RECT  4.608 2.101 4.626 2.191 ;
     RECT  9.828 2.065 20.286 2.191 ;
     RECT  29.415 2.143 29.505 2.191 ;
     RECT  31.572 2.101 38.43 2.191 ;
     RECT  39.168 2.101 39.186 2.191 ;
     RECT  40.215 2.143 40.305 2.191 ;
     RECT  41.112 2.101 41.13 2.191 ;
     RECT  9.108 2.191 20.718 2.227 ;
     RECT  52.452 2.191 52.47 2.227 ;
     RECT  29.415 2.191 30.222 2.251 ;
     RECT  31.356 2.191 40.305 2.251 ;
     RECT  2.415 2.143 3.474 2.263 ;
     RECT  4.32 2.191 4.626 2.263 ;
     RECT  7.815 2.143 7.905 2.263 ;
     RECT  8.64 2.227 20.718 2.263 ;
     RECT  21.636 2.227 21.654 2.263 ;
     RECT  44.46 1.723 48.366 2.263 ;
     RECT  5.724 2.101 6.03 2.299 ;
     RECT  28.548 2.191 28.566 2.299 ;
     RECT  41.112 2.191 41.742 2.299 ;
     RECT  2.415 2.263 4.626 2.335 ;
     RECT  5.4 2.299 6.03 2.335 ;
     RECT  6.804 2.191 6.822 2.335 ;
     RECT  22.788 2.059 22.806 2.335 ;
     RECT  27.36 2.299 28.566 2.335 ;
     RECT  29.415 2.251 40.305 2.335 ;
     RECT  43.416 2.263 43.686 2.335 ;
     RECT  52.272 2.227 52.47 2.335 ;
     RECT  2.415 2.335 6.822 2.347 ;
     RECT  7.815 2.263 21.654 2.371 ;
     RECT  22.788 2.335 22.842 2.371 ;
     RECT  43.056 2.335 43.686 2.371 ;
     RECT  44.46 2.263 48.69 2.371 ;
     RECT  51.984 2.335 52.47 2.371 ;
     RECT  24.015 2.143 24.105 2.413 ;
     RECT  27.36 2.335 40.305 2.413 ;
     RECT  41.112 2.299 41.886 2.413 ;
     RECT  51.015 2.143 51.105 2.413 ;
     RECT  51.984 2.371 53.01 2.413 ;
     RECT  56.415 2.143 56.505 2.413 ;
     RECT  57.6 2.143 61.905 2.413 ;
     RECT  7.815 2.371 22.842 2.461 ;
     RECT  24.015 2.413 24.297 2.461 ;
     RECT  27.36 2.413 41.886 2.461 ;
     RECT  43.056 2.371 49.662 2.461 ;
     RECT  51.015 2.413 53.01 2.461 ;
     RECT  26.388 2.101 26.406 2.497 ;
     RECT  27.36 2.461 41.922 2.497 ;
     RECT  51.015 2.461 53.694 2.569 ;
     RECT  54.828 2.533 54.846 2.569 ;
     RECT  51.015 2.569 54.846 2.605 ;
     RECT  2.304 2.347 6.822 2.641 ;
     RECT  7.815 2.461 22.878 2.641 ;
     RECT  23.94 2.461 24.297 2.641 ;
     RECT  26.388 2.497 41.922 2.641 ;
     RECT  42.768 2.461 49.662 2.641 ;
     RECT  51.015 2.605 55.062 2.641 ;
     RECT  57.6 2.413 62.097 2.641 ;
     RECT  26.388 2.641 55.062 2.731 ;
     RECT  57.528 2.641 62.154 2.759 ;
     RECT  0.108 2.227 0.126 2.803 ;
     RECT  2.304 2.641 22.878 2.827 ;
     RECT  23.94 2.641 24.606 2.839 ;
     RECT  2.304 2.827 23.166 2.911 ;
     RECT  23.94 2.839 25.254 2.911 ;
     RECT  57.636 2.759 62.154 2.911 ;
     RECT  2.304 2.911 25.254 2.923 ;
     RECT  0.108 2.803 0.162 3.067 ;
     RECT  26.388 2.731 55.134 3.073 ;
     RECT  26.208 3.073 55.134 3.101 ;
     RECT  27.324 3.101 55.134 3.181 ;
     RECT  56.415 2.413 56.697 3.181 ;
     RECT  1.728 2.923 25.254 3.209 ;
     RECT  0.108 3.067 0.198 3.379 ;
     RECT  25.056 3.209 25.254 3.403 ;
     RECT  26.208 3.101 26.514 3.403 ;
     RECT  0.108 3.379 0.558 3.437 ;
     RECT  25.056 3.403 26.514 3.437 ;
     RECT  27.324 3.181 56.697 3.677 ;
     RECT  53.604 3.677 56.697 3.685 ;
     RECT  53.604 3.685 56.898 3.721 ;
     RECT  57.636 2.911 62.226 3.721 ;
     RECT  25.092 3.437 26.514 3.947 ;
     RECT  25.164 3.947 26.514 3.979 ;
     RECT  27.324 3.677 52.758 3.979 ;
     RECT  25.164 3.979 52.758 4.145 ;
     RECT  53.604 3.721 62.226 4.145 ;
     RECT  0.108 3.437 0.162 4.189 ;
     RECT  58.32 4.145 62.226 4.261 ;
     RECT  1.728 3.209 24.297 4.415 ;
     RECT  53.604 4.145 57.51 4.415 ;
     RECT  1.728 4.415 5.922 4.451 ;
     RECT  27.252 4.145 52.758 4.459 ;
     RECT  53.604 4.415 57.15 4.459 ;
     RECT  1.728 4.451 5.886 4.685 ;
     RECT  58.32 4.261 62.334 4.801 ;
     RECT  25.164 4.145 26.514 4.927 ;
     RECT  27.252 4.459 57.15 4.927 ;
     RECT  58.32 4.801 62.478 5.161 ;
     RECT  6.732 4.415 24.297 5.197 ;
     RECT  25.164 4.927 57.15 5.197 ;
     RECT  2.268 4.685 5.886 5.269 ;
     RECT  6.732 5.197 57.186 5.269 ;
     RECT  2.268 5.269 57.186 5.341 ;
     RECT  57.924 5.161 62.478 5.341 ;
     RECT  0.108 4.189 0.558 5.453 ;
     RECT  2.268 5.341 62.478 5.495 ;
     RECT  0.504 5.453 0.558 5.645 ;
     RECT  0.504 5.645 0.522 5.741 ;
     RECT  2.304 5.495 62.478 6.575 ;
     RECT  0.54 6.691 0.558 6.817 ;
     RECT  0.108 6.817 0.558 6.893 ;
     RECT  2.304 6.575 5.85 7.465 ;
     RECT  6.624 6.575 62.478 7.465 ;
     RECT  0.108 6.893 0.162 7.627 ;
     RECT  2.304 7.465 62.478 7.771 ;
     RECT  0.108 7.627 0.234 7.816 ;
     RECT  0.108 7.816 0.378 7.949 ;
     RECT  2.304 7.771 62.514 7.961 ;
     RECT  2.304 7.961 62.478 8.195 ;
     RECT  0.144 7.949 0.342 8.525 ;
     RECT  2.304 8.195 55.458 9.121 ;
     RECT  56.196 8.195 62.478 9.121 ;
     RECT  2.304 9.121 62.478 9.347 ;
     RECT  0.144 8.525 0.234 9.355 ;
     RECT  0.108 9.355 0.558 9.773 ;
     RECT  2.304 9.347 30.258 9.835 ;
     RECT  31.068 9.347 62.478 10.085 ;
     RECT  31.176 10.085 62.478 10.121 ;
     RECT  0.108 9.773 0.234 10.507 ;
     RECT  1.728 9.835 30.258 10.741 ;
     RECT  1.728 10.741 30.438 10.867 ;
     RECT  31.212 10.121 62.478 10.867 ;
     RECT  0.108 10.507 0.882 11.851 ;
     RECT  1.728 10.867 62.478 11.975 ;
     RECT  2.268 11.975 62.478 12.083 ;
     RECT  0.072 11.851 0.882 13.325 ;
     RECT  2.304 12.083 62.478 13.865 ;
     RECT  0.072 13.325 0.594 14.675 ;
     RECT  0.072 14.675 0.27 14.791 ;
     RECT  0.036 14.791 0.27 14.819 ;
     RECT  0.036 14.819 0.09 14.945 ;
     RECT  0.072 14.945 0.09 15.485 ;
     RECT  2.415 13.865 62.478 16.943 ;
     RECT  30.672 16.943 62.478 17.221 ;
     RECT  30.672 17.221 62.514 17.483 ;
     RECT  2.415 16.943 29.826 17.761 ;
     RECT  30.672 17.483 62.478 17.761 ;
     RECT  2.415 17.761 62.478 18.535 ;
     RECT  2.415 18.535 62.514 18.689 ;
     RECT  2.415 18.689 62.478 20.093 ;
     RECT  2.415 20.093 29.97 21.235 ;
     RECT  30.78 20.093 62.478 21.235 ;
     RECT  2.415 21.235 62.478 21.803 ;
     RECT  3.708 21.803 62.478 22.001 ;
     RECT  3.78 22.001 62.478 22.199 ;
     RECT  3.888 22.199 62.478 22.379 ;
     RECT  3.888 22.379 51.297 23.161 ;
     RECT  3.852 23.161 51.297 23.251 ;
     RECT  52.056 22.379 62.478 23.251 ;
     RECT  2.415 21.803 2.97 23.275 ;
     RECT  3.852 23.251 62.478 23.275 ;
     RECT  2.415 23.275 62.478 23.459 ;
     RECT  2.415 23.459 8.298 24.205 ;
     RECT  9.144 23.459 62.478 24.205 ;
     RECT  2.415 24.205 62.478 24.431 ;
     RECT  2.415 24.431 52.074 24.509 ;
     RECT  2.415 24.509 8.406 24.781 ;
     RECT  2.376 24.781 8.406 25.079 ;
     RECT  9.18 24.509 52.074 25.447 ;
     RECT  52.812 24.431 62.478 25.447 ;
     RECT  9.18 25.447 62.478 25.591 ;
     RECT  2.415 25.079 8.406 25.789 ;
     RECT  9.144 25.591 62.478 25.789 ;
     RECT  2.415 25.789 62.478 26.519 ;
     RECT  2.415 26.519 52.074 27.337 ;
     RECT  52.812 26.519 62.478 27.337 ;
     RECT  2.415 27.337 62.478 30.605 ;
     RECT  2.415 30.605 30.042 30.749 ;
     RECT  30.78 30.605 62.478 30.839 ;
     RECT  52.776 30.839 62.478 31.019 ;
     RECT  52.776 31.019 62.37 31.145 ;
     RECT  30.78 30.839 51.966 31.181 ;
     RECT  30.78 31.181 51.858 31.531 ;
     RECT  30.636 31.531 51.858 31.757 ;
     RECT  2.415 30.749 29.697 31.801 ;
     RECT  30.636 31.757 51.714 31.801 ;
     RECT  2.415 31.801 51.714 32.503 ;
     RECT  2.415 32.503 51.858 32.737 ;
     RECT  52.812 31.145 62.37 32.909 ;
     RECT  2.415 32.737 51.894 33.053 ;
     RECT  50.148 33.053 51.894 33.151 ;
     RECT  52.812 32.909 62.097 33.151 ;
     RECT  2.415 33.053 49.41 33.377 ;
     RECT  50.148 33.151 62.097 33.413 ;
     RECT  52.596 33.413 62.097 33.961 ;
     RECT  50.148 33.413 51.858 34.195 ;
     RECT  52.596 33.961 62.262 34.195 ;
     RECT  32.94 33.377 49.41 34.321 ;
     RECT  50.148 34.195 62.262 34.321 ;
     RECT  32.94 34.321 62.262 34.349 ;
     RECT  32.94 34.349 62.154 34.385 ;
     RECT  2.415 33.377 32.202 34.591 ;
     RECT  32.94 34.385 62.097 34.591 ;
     RECT  2.415 34.591 62.097 35.195 ;
     RECT  2.415 35.195 49.302 35.303 ;
     RECT  50.184 35.195 62.097 35.311 ;
     RECT  50.184 35.311 62.19 35.573 ;
     RECT  50.184 35.573 62.154 36.049 ;
     RECT  50.04 36.049 62.154 36.211 ;
     RECT  2.415 35.303 49.23 36.247 ;
     RECT  2.415 36.247 49.266 36.319 ;
     RECT  50.004 36.211 62.154 36.319 ;
     RECT  2.415 36.319 62.154 36.509 ;
     RECT  5.184 36.509 62.154 36.581 ;
     RECT  22.428 36.581 62.154 36.653 ;
     RECT  61.2 36.653 62.154 36.779 ;
     RECT  61.2 36.779 62.097 36.815 ;
     RECT  61.344 36.815 62.097 36.851 ;
     RECT  61.632 36.851 62.097 36.923 ;
     RECT  22.428 36.653 60.246 37.121 ;
     RECT  5.184 36.581 21.69 37.327 ;
     RECT  22.428 37.121 59.886 37.327 ;
     RECT  5.184 37.327 59.886 37.355 ;
     RECT  5.184 37.355 33.282 37.967 ;
     RECT  22.5 37.967 33.282 38.101 ;
     RECT  34.02 37.355 59.886 38.101 ;
     RECT  2.415 36.509 4.446 38.245 ;
     RECT  5.184 37.967 21.69 38.245 ;
     RECT  2.415 38.245 21.69 38.821 ;
     RECT  22.5 38.101 59.886 38.821 ;
     RECT  2.415 38.821 59.886 39.749 ;
     RECT  55.44 39.749 59.886 40.171 ;
     RECT  55.44 40.171 60.03 40.361 ;
     RECT  2.415 39.749 54.63 40.711 ;
     RECT  55.44 40.361 59.886 40.711 ;
     RECT  2.415 40.711 59.886 41.243 ;
     RECT  55.332 41.243 59.886 41.881 ;
     RECT  2.415 41.243 54.522 42.061 ;
     RECT  2.415 42.061 54.558 42.139 ;
     RECT  55.332 41.881 60.426 42.139 ;
     RECT  2.415 42.139 60.426 42.601 ;
     RECT  2.415 42.601 60.57 42.719 ;
     RECT  2.415 42.719 14.31 42.755 ;
     RECT  15.048 42.719 60.57 43.771 ;
     RECT  3.42 42.755 14.31 43.879 ;
     RECT  15.048 43.771 60.714 43.879 ;
     RECT  2.415 42.755 2.697 43.951 ;
     RECT  3.42 43.879 60.714 43.951 ;
     RECT  2.415 43.951 60.714 44.609 ;
     RECT  3.564 44.609 5.454 45.149 ;
     RECT  6.192 44.609 60.714 45.527 ;
     RECT  21.636 45.527 60.714 45.571 ;
     RECT  61.815 36.923 62.097 45.571 ;
     RECT  4.248 45.149 5.454 45.761 ;
     RECT  6.192 45.527 20.898 45.805 ;
     RECT  4.248 45.761 5.418 46.075 ;
     RECT  21.636 45.571 62.097 46.139 ;
     RECT  6.156 45.805 20.898 46.363 ;
     RECT  21.636 46.139 60.39 46.363 ;
     RECT  6.156 46.363 60.39 46.499 ;
     RECT  4.14 46.075 5.418 46.507 ;
     RECT  6.156 46.499 15.93 46.507 ;
     RECT  61.128 46.139 62.097 46.571 ;
     RECT  4.14 46.507 15.93 46.615 ;
     RECT  4.032 46.615 15.93 46.651 ;
     RECT  3.996 46.651 15.93 46.843 ;
     RECT  16.74 46.499 60.39 47.191 ;
     RECT  3.6 46.843 15.93 47.281 ;
     RECT  16.74 47.191 60.462 47.281 ;
     RECT  61.815 46.571 62.097 47.461 ;
     RECT  3.6 47.281 60.462 47.821 ;
     RECT  3.6 47.821 60.498 47.965 ;
     RECT  61.344 47.461 62.097 47.965 ;
     RECT  3.6 47.965 62.097 48.389 ;
     RECT  3.78 48.389 62.097 48.413 ;
     RECT  4.068 48.413 62.097 48.659 ;
     RECT  4.176 48.659 62.097 49.469 ;
     RECT  4.176 49.469 15.75 49.505 ;
     RECT  16.488 49.469 62.097 49.919 ;
     RECT  4.68 49.505 15.75 50.009 ;
     RECT  4.824 50.009 15.75 50.431 ;
     RECT  16.488 49.919 17.262 50.431 ;
     RECT  4.824 50.431 17.262 50.701 ;
     RECT  18.036 49.919 62.097 50.701 ;
     RECT  4.824 50.701 62.097 50.729 ;
     RECT  4.824 50.729 60.642 50.935 ;
     RECT  4.788 50.935 60.642 50.971 ;
     RECT  4.752 50.971 60.642 51.307 ;
     RECT  4.536 51.307 60.642 51.359 ;
     RECT  4.536 51.359 20.61 51.395 ;
     RECT  21.492 51.359 60.642 51.395 ;
     RECT  30.708 51.395 31.158 51.431 ;
     RECT  32.292 51.395 60.642 51.467 ;
     RECT  20.088 51.395 20.61 51.503 ;
     RECT  4.536 51.395 15.93 51.539 ;
     RECT  30.744 51.431 31.158 51.539 ;
     RECT  2.415 44.609 2.697 51.587 ;
     RECT  61.815 50.729 62.097 51.587 ;
     RECT  4.536 51.539 6.462 51.629 ;
     RECT  7.308 51.539 15.93 51.629 ;
     RECT  17.244 51.395 19.17 51.629 ;
     RECT  20.088 51.503 20.106 51.629 ;
     RECT  21.492 51.395 29.97 51.629 ;
     RECT  30.996 51.539 31.158 51.629 ;
     RECT  44.856 51.467 60.642 51.629 ;
     RECT  5.436 51.629 5.49 51.665 ;
     RECT  6.444 51.629 6.462 51.665 ;
     RECT  7.308 51.629 15.642 51.665 ;
     RECT  17.352 51.629 17.37 51.665 ;
     RECT  18.216 51.629 19.17 51.665 ;
     RECT  22.86 51.629 22.878 51.665 ;
     RECT  23.94 51.629 29.97 51.665 ;
     RECT  30.996 51.629 31.014 51.665 ;
     RECT  32.292 51.467 43.902 51.665 ;
     RECT  44.856 51.629 59.526 51.665 ;
     RECT  52.74 51.665 59.526 51.677 ;
     RECT  7.308 51.665 15.138 51.701 ;
     RECT  38.232 51.665 42.894 51.701 ;
     RECT  7.308 51.701 14.634 51.737 ;
     RECT  23.94 51.665 29.862 51.737 ;
     RECT  43.884 51.665 43.902 51.737 ;
     RECT  52.74 51.677 58.014 51.737 ;
     RECT  59.508 51.677 59.526 51.737 ;
     RECT  4.536 51.629 4.554 51.773 ;
     RECT  18.216 51.665 18.99 51.773 ;
     RECT  23.94 51.737 28.566 51.773 ;
     RECT  32.292 51.665 36.306 51.773 ;
     RECT  52.74 51.737 57.366 51.773 ;
     RECT  37.188 51.665 37.206 51.809 ;
     RECT  44.856 51.665 51.966 51.809 ;
     RECT  32.292 51.773 35.874 51.821 ;
     RECT  45.468 51.809 51.858 51.821 ;
     RECT  2.415 51.587 2.505 51.857 ;
     RECT  18.615 51.773 18.705 51.857 ;
     RECT  29.415 51.737 29.862 51.857 ;
     RECT  61.815 51.587 61.905 51.857 ;
     RECT  32.292 51.821 35.55 51.917 ;
     RECT  45.468 51.821 51.75 51.965 ;
     RECT  45.468 51.965 51.462 52.445 ;
     RECT  45.468 52.445 47.25 52.493 ;
     RECT  52.74 51.773 57.33 52.493 ;
     RECT  32.292 51.917 35.262 52.541 ;
     RECT  45.54 52.493 47.25 52.541 ;
     RECT  51.444 52.445 51.462 52.925 ;
     RECT  48.852 52.445 49.842 52.973 ;
     RECT  7.308 51.737 11.79 52.987 ;
     RECT  5.436 51.665 5.454 53.015 ;
     RECT  33.048 52.541 35.262 53.021 ;
     RECT  46.008 52.541 47.25 53.021 ;
     RECT  29.844 51.857 29.862 53.051 ;
     RECT  32.292 52.541 32.31 53.069 ;
     RECT  33.048 53.021 33.066 53.069 ;
     RECT  33.984 53.021 34.11 53.069 ;
     RECT  46.008 53.021 46.134 53.069 ;
     RECT  48.852 52.973 49.806 53.069 ;
     RECT  49.284 53.069 49.302 53.741 ;
     RECT  34.092 53.069 34.11 53.885 ;
     RECT  46.008 53.069 46.026 53.885 ;
     RECT  47.196 53.021 47.214 53.885 ;
     RECT  50.616 52.445 50.634 53.885 ;
     RECT  12.636 51.737 14.634 53.969 ;
     RECT  7.236 52.987 11.79 53.981 ;
     RECT  12.636 53.969 14.094 53.981 ;
     RECT  23.94 51.773 28.494 53.981 ;
     RECT  38.34 51.701 42.894 53.981 ;
     RECT  52.74 52.493 57.294 53.981 ;
    LAYER M4 ;
     RECT  0.06 2.352 0.061 11.784 ;
     RECT  0.061 2.352 0.317 11.88 ;
     RECT  0.181 14.784 0.323 14.808 ;
     RECT  0.317 2.352 2.293 11.688 ;
     RECT  2.293 2.352 2.408 11.784 ;
     RECT  0.181 26.88 2.408 26.904 ;
     RECT  2.408 2.148 2.512 51.852 ;
     RECT  2.512 2.418 2.704 51.582 ;
     RECT  2.704 3.072 2.765 6.168 ;
     RECT  2.704 7.152 2.837 13.032 ;
     RECT  2.704 31.296 2.915 32.76 ;
     RECT  2.704 37.152 2.945 38.232 ;
     RECT  2.915 31.296 2.981 31.32 ;
     RECT  2.704 23.28 3.052 24.6 ;
     RECT  2.704 44.256 3.053 44.904 ;
     RECT  2.704 34.176 3.089 35.832 ;
     RECT  3.089 34.512 3.107 35.832 ;
     RECT  2.704 28.464 3.161 29.832 ;
     RECT  2.765 4.416 3.197 6.168 ;
     RECT  2.837 7.152 3.269 11.448 ;
     RECT  2.765 3.072 3.341 3.096 ;
     RECT  3.269 8.496 3.341 11.448 ;
     RECT  2.945 37.152 3.413 38.136 ;
     RECT  2.704 39.888 3.443 41.64 ;
     RECT  3.443 40.56 3.484 40.584 ;
     RECT  3.052 24.576 3.485 24.6 ;
     RECT  3.341 8.544 3.557 11.448 ;
     RECT  3.107 34.656 3.557 35.832 ;
     RECT  2.704 18.816 3.593 21.144 ;
     RECT  2.704 25.632 3.629 25.848 ;
     RECT  3.557 9.312 3.737 11.448 ;
     RECT  2.704 14.112 3.737 14.712 ;
     RECT  2.704 42.72 3.773 42.744 ;
     RECT  3.74 48.384 3.781 48.408 ;
     RECT  2.704 17.472 3.805 17.496 ;
     RECT  3.593 19.44 3.809 21.144 ;
     RECT  3.781 48.384 3.827 49.032 ;
     RECT  3.737 9.936 3.841 11.448 ;
     RECT  2.837 12.816 3.841 13.032 ;
     RECT  3.197 5.136 3.877 6.168 ;
     RECT  3.269 7.152 3.877 7.176 ;
     RECT  3.841 9.936 3.913 13.08 ;
     RECT  3.805 16.656 3.949 17.496 ;
     RECT  3.949 16.656 3.953 18.168 ;
     RECT  3.809 20.544 3.985 21.144 ;
     RECT  3.629 25.824 3.985 25.848 ;
     RECT  2.704 26.88 3.985 26.904 ;
     RECT  3.557 34.896 3.985 35.832 ;
     RECT  3.809 19.44 4.025 19.464 ;
     RECT  3.953 17.472 4.061 18.168 ;
     RECT  2.704 46.848 4.085 46.872 ;
     RECT  2.915 32.736 4.129 32.76 ;
     RECT  3.985 34.896 4.133 36.408 ;
     RECT  3.161 28.992 4.165 29.832 ;
     RECT  3.413 38.112 4.169 38.136 ;
     RECT  4.085 46.128 4.169 46.872 ;
     RECT  4.129 31.872 4.213 32.76 ;
     RECT  3.737 14.352 4.277 14.712 ;
     RECT  3.877 5.136 4.309 7.176 ;
     RECT  3.053 44.88 4.309 44.904 ;
     RECT  4.213 32.736 4.385 32.76 ;
     RECT  4.309 5.136 4.405 7.656 ;
     RECT  4.273 42.768 4.417 42.792 ;
     RECT  4.165 28.992 4.489 30.408 ;
     RECT  4.405 4.512 4.493 7.656 ;
     RECT  3.913 9.936 4.493 13.128 ;
     RECT  4.417 42.768 4.493 42.888 ;
     RECT  3.443 41.616 4.525 41.64 ;
     RECT  3.985 20.544 4.529 21.192 ;
     RECT  4.508 51.312 4.549 51.336 ;
     RECT  3.769 2.784 4.561 2.808 ;
     RECT  4.525 41.088 4.561 41.64 ;
     RECT  4.061 18.144 4.565 18.168 ;
     RECT  4.549 50.688 4.595 51.336 ;
     RECT  4.493 42.864 4.601 42.888 ;
     RECT  4.309 44.688 4.601 44.904 ;
     RECT  4.493 10.608 4.637 13.128 ;
     RECT  4.561 40.416 4.709 41.64 ;
     RECT  4.277 14.352 4.745 14.376 ;
     RECT  3.827 49.008 4.813 49.032 ;
     RECT  4.595 50.688 4.853 50.808 ;
     RECT  3.985 25.824 4.981 26.904 ;
     RECT  3.052 23.28 4.993 23.304 ;
     RECT  4.489 28.512 5.027 30.408 ;
     RECT  4.993 23.28 5.033 24.264 ;
     RECT  4.601 44.88 5.065 44.904 ;
     RECT  5.027 28.752 5.077 30.408 ;
     RECT  4.169 46.8 5.077 46.872 ;
     RECT  4.525 32.784 5.101 32.808 ;
     RECT  5.065 34.08 5.101 34.104 ;
     RECT  5.077 28.752 5.123 30.84 ;
     RECT  4.709 40.416 5.123 41.4 ;
     RECT  5.065 44.88 5.149 45 ;
     RECT  5.132 43.872 5.173 43.896 ;
     RECT  4.637 10.608 5.177 13.032 ;
     RECT  4.981 25.824 5.177 27.336 ;
     RECT  5.123 41.088 5.177 41.4 ;
     RECT  4.813 49.008 5.177 49.56 ;
     RECT  4.493 5.28 5.209 7.656 ;
     RECT  5.101 32.784 5.209 34.104 ;
     RECT  5.173 43.296 5.219 43.896 ;
     RECT  4.529 20.688 5.285 20.76 ;
     RECT  4.133 35.328 5.317 36.408 ;
     RECT  5.101 48 5.317 48.024 ;
     RECT  5.149 44.88 5.321 44.904 ;
     RECT  5.317 35.328 5.363 36.792 ;
     RECT  4.561 2.544 5.389 2.808 ;
     RECT  5.363 36.24 5.404 36.792 ;
     RECT  5.123 29.808 5.592 30.84 ;
     RECT  5.389 2.496 5.641 2.808 ;
     RECT  5.033 24.24 5.641 24.264 ;
     RECT  5.592 29.808 5.641 31.8 ;
     RECT  5.209 32.784 5.641 34.152 ;
     RECT  5.077 46.8 5.641 47.016 ;
     RECT  5.209 5.28 5.653 7.896 ;
     RECT  5.533 9.984 5.653 10.008 ;
     RECT  5.653 9.312 5.699 10.008 ;
     RECT  5.177 11.184 5.713 13.032 ;
     RECT  5.219 43.296 5.713 43.32 ;
     RECT  5.641 2.496 5.725 2.856 ;
     RECT  5.653 5.184 5.749 7.896 ;
     RECT  5.699 9.312 5.749 9.816 ;
     RECT  5.641 24.24 5.749 24.84 ;
     RECT  5.713 11.184 5.753 13.08 ;
     RECT  5.641 29.808 5.753 34.152 ;
     RECT  5.725 2.496 5.789 2.808 ;
     RECT  5.749 24.24 5.789 25.464 ;
     RECT  5.753 30.144 5.789 34.152 ;
     RECT  5.885 38.784 5.893 38.808 ;
     RECT  5.677 17.76 5.933 17.784 ;
     RECT  5.753 13.056 5.969 13.08 ;
     RECT  5.893 37.968 5.969 38.808 ;
     RECT  5.789 30.144 6.005 31.8 ;
     RECT  5.177 26.736 6.149 27.336 ;
     RECT  5.713 43.104 6.221 43.32 ;
     RECT  6.221 43.104 6.227 43.128 ;
     RECT  5.641 46.704 6.253 47.016 ;
     RECT  5.123 28.752 6.289 28.776 ;
     RECT  5.285 20.688 6.293 20.712 ;
     RECT  5.677 19.2 6.325 19.224 ;
     RECT  5.177 41.376 6.325 41.4 ;
     RECT  5.753 11.184 6.329 12.072 ;
     RECT  5.789 32.784 6.329 34.152 ;
     RECT  6.149 26.88 6.361 27.336 ;
     RECT  6.289 28.416 6.361 28.776 ;
     RECT  5.789 2.496 6.365 2.712 ;
     RECT  6.325 41.376 6.365 41.928 ;
     RECT  5.969 37.968 6.397 37.992 ;
     RECT  6.005 30.144 6.437 30.84 ;
     RECT  4.853 50.784 6.437 50.808 ;
     RECT  5.317 48 6.469 48.264 ;
     RECT  5.177 49.536 6.469 49.56 ;
     RECT  6.329 34.128 6.473 34.152 ;
     RECT  6.469 48 6.473 49.56 ;
     RECT  6.037 17.52 6.541 17.688 ;
     RECT  6.253 46.608 6.613 47.016 ;
     RECT  6.325 19.2 6.617 19.512 ;
     RECT  6.365 2.496 6.689 2.52 ;
     RECT  6.329 11.904 6.725 12.072 ;
     RECT  6.617 19.488 6.761 19.512 ;
     RECT  6.361 26.88 7.093 28.776 ;
     RECT  6.437 30.144 7.093 30.168 ;
     RECT  5.749 5.184 7.153 9.816 ;
     RECT  6.725 12 7.153 12.072 ;
     RECT  7.153 12 7.189 12.984 ;
     RECT  7.153 21.984 7.225 22.008 ;
     RECT  5.404 36.24 7.261 36.264 ;
     RECT  6.397 37.584 7.261 37.992 ;
     RECT  7.153 5.184 7.369 10.68 ;
     RECT  6.613 46.608 7.405 47.88 ;
     RECT  7.093 26.88 7.441 30.168 ;
     RECT  7.261 36.24 7.441 37.992 ;
     RECT  7.369 4.128 7.513 10.68 ;
     RECT  7.405 46.224 7.513 47.88 ;
     RECT  6.473 49.008 7.513 49.56 ;
     RECT  7.513 46.224 7.525 49.56 ;
     RECT  6.365 41.904 7.549 41.928 ;
     RECT  5.789 24.672 7.621 25.464 ;
     RECT  7.441 26.88 7.621 30.6 ;
     RECT  7.441 36.096 7.657 37.992 ;
     RECT  7.657 36.096 7.669 38.184 ;
     RECT  7.613 39.888 7.669 39.912 ;
     RECT  7.621 24.672 7.693 30.6 ;
     RECT  7.669 51.36 7.765 51.384 ;
     RECT  7.513 3.408 7.808 10.68 ;
     RECT  7.189 12 7.808 13.08 ;
     RECT  6.541 17.136 7.808 17.688 ;
     RECT  7.189 19.776 7.808 19.8 ;
     RECT  7.225 21.36 7.808 22.008 ;
     RECT  7.297 23.328 7.808 23.352 ;
     RECT  7.693 24.672 7.808 30.696 ;
     RECT  6.329 32.784 7.808 33.048 ;
     RECT  6.865 34.32 7.808 34.344 ;
     RECT  7.669 36 7.808 39.912 ;
     RECT  7.549 41.904 7.808 42.792 ;
     RECT  7.525 46.224 7.808 50.04 ;
     RECT  7.765 51.216 7.808 51.384 ;
     RECT  7.381 52.464 7.808 52.488 ;
     RECT  7.808 2.148 7.912 52.488 ;
     RECT  7.912 2.418 8.104 52.488 ;
     RECT  8.104 44.448 8.201 51.384 ;
     RECT  8.104 24.48 8.237 27.432 ;
     RECT  8.104 28.416 8.339 30.84 ;
     RECT  8.339 30.288 8.381 30.84 ;
     RECT  8.381 30.672 8.453 30.84 ;
     RECT  8.104 36.096 8.453 38.472 ;
     RECT  8.237 24.48 8.489 26.904 ;
     RECT  8.104 12.768 8.633 18.264 ;
     RECT  8.104 52.464 8.741 52.488 ;
     RECT  8.104 3.408 8.813 7.176 ;
     RECT  8.633 13.008 8.867 18.264 ;
     RECT  8.104 32.784 8.921 33.048 ;
     RECT  8.104 41.904 8.921 42.792 ;
     RECT  8.489 26.736 8.957 26.904 ;
     RECT  8.867 13.008 9.029 17.976 ;
     RECT  9.029 13.008 9.101 15.624 ;
     RECT  8.489 24.48 9.107 25.464 ;
     RECT  8.104 39.744 9.133 39.768 ;
     RECT  9.029 16.992 9.137 17.976 ;
     RECT  8.453 30.816 9.169 30.84 ;
     RECT  9.133 39.456 9.169 39.768 ;
     RECT  9.169 39.456 9.205 39.912 ;
     RECT  9.169 30.816 9.209 31.128 ;
     RECT  8.104 23.328 9.281 23.352 ;
     RECT  8.453 36.096 9.281 37.992 ;
     RECT  8.104 34.128 9.308 34.776 ;
     RECT  9.281 36.096 9.308 37.608 ;
     RECT  9.101 13.008 9.317 15.144 ;
     RECT  9.137 17.088 9.317 17.976 ;
     RECT  8.921 33.024 9.349 33.048 ;
     RECT  9.308 34.128 9.349 37.608 ;
     RECT  8.813 4.032 9.353 7.176 ;
     RECT  9.349 33.024 9.395 37.608 ;
     RECT  9.205 39.168 9.397 39.912 ;
     RECT  9.395 35.904 9.436 37.608 ;
     RECT  9.397 39.168 9.443 40.728 ;
     RECT  8.665 53.904 9.443 53.928 ;
     RECT  9.443 40.32 9.457 40.728 ;
     RECT  8.921 41.904 9.457 42.456 ;
     RECT  9.317 13.008 9.461 13.656 ;
     RECT  9.317 15.12 9.497 15.144 ;
     RECT  8.104 8.256 9.557 10.68 ;
     RECT  9.443 39.168 9.601 39.192 ;
     RECT  9.457 40.32 9.605 42.456 ;
     RECT  9.557 8.256 9.641 10.872 ;
     RECT  8.201 44.448 9.709 51.336 ;
     RECT  9.349 20.112 9.713 20.136 ;
     RECT  8.104 21.984 9.713 22.008 ;
     RECT  9.395 33.024 9.713 33.576 ;
     RECT  9.709 44.208 9.748 51.336 ;
     RECT  9.353 4.32 9.785 7.176 ;
     RECT  9.461 13.008 9.785 13.08 ;
     RECT  9.641 8.256 9.821 10.776 ;
     RECT  8.339 28.416 9.821 29.256 ;
     RECT  8.957 26.88 9.925 26.904 ;
     RECT  9.817 0.576 9.971 0.6 ;
     RECT  9.925 26.88 10.033 27.144 ;
     RECT  9.748 44.208 10.033 51.384 ;
     RECT  9.821 29.232 10.069 29.256 ;
     RECT  10.105 1.728 10.172 1.752 ;
     RECT  9.107 24.672 10.181 25.464 ;
     RECT  9.317 17.136 10.217 17.976 ;
     RECT  9.713 33.312 10.217 33.576 ;
     RECT  9.785 4.704 10.249 7.176 ;
     RECT  9.821 8.256 10.249 9.816 ;
     RECT  9.601 38.736 10.249 39.192 ;
     RECT  10.217 33.312 10.289 33.528 ;
     RECT  10.289 33.312 10.361 33.336 ;
     RECT  10.249 38.592 10.361 39.192 ;
     RECT  10.213 21.168 10.501 21.192 ;
     RECT  10.361 38.688 10.505 39.192 ;
     RECT  10.217 17.136 10.541 17.832 ;
     RECT  10.501 21.072 10.541 21.192 ;
     RECT  10.033 26.88 10.541 27.96 ;
     RECT  10.541 21.072 10.613 21.096 ;
     RECT  9.605 41.904 10.681 42.456 ;
     RECT  10.645 3.36 10.789 3.384 ;
     RECT  10.249 4.704 10.789 9.816 ;
     RECT  9.997 0.096 10.835 0.552 ;
     RECT  10.429 23.904 10.861 24.36 ;
     RECT  9.605 40.32 10.861 40.344 ;
     RECT  9.209 31.104 10.865 31.128 ;
     RECT  10.033 43.536 10.883 51.864 ;
     RECT  9.395 34.656 10.901 34.776 ;
     RECT  10.172 1.728 10.933 2.28 ;
     RECT  10.861 40.32 10.933 40.776 ;
     RECT  10.681 41.76 10.933 42.456 ;
     RECT  10.883 43.536 10.933 51.432 ;
     RECT  10.933 40.32 10.945 51.432 ;
     RECT  10.861 22.992 11.027 24.36 ;
     RECT  11.027 22.992 11.045 23.352 ;
     RECT  9.436 36.24 11.153 37.608 ;
     RECT  10.933 1.728 11.185 2.328 ;
     RECT  10.789 3.36 11.185 9.816 ;
     RECT  10.285 12.192 11.185 12.216 ;
     RECT  10.541 17.376 11.185 17.832 ;
     RECT  10.181 25.44 11.185 25.464 ;
     RECT  10.541 26.88 11.185 26.904 ;
     RECT  10.945 40.32 11.225 51.336 ;
     RECT  10.933 34.8 11.257 35.016 ;
     RECT  10.645 13.344 11.297 13.368 ;
     RECT  11.185 17.376 11.329 17.928 ;
     RECT  11.225 43.68 11.333 51.336 ;
     RECT  11.149 14.784 11.441 14.808 ;
     RECT  11.185 1.728 11.509 9.816 ;
     RECT  11.153 36.24 11.612 37.08 ;
     RECT  11.509 1.728 11.617 10.392 ;
     RECT  11.045 22.992 11.617 23.016 ;
     RECT  10.505 38.688 11.621 39.096 ;
     RECT  11.617 1.728 11.689 10.632 ;
     RECT  11.621 39.072 11.689 39.096 ;
     RECT  11.225 40.32 11.689 42.696 ;
     RECT  11.612 36.144 11.699 37.08 ;
     RECT  11.617 22.896 11.725 23.016 ;
     RECT  11.333 51.312 11.765 51.336 ;
     RECT  11.185 25.44 11.797 26.904 ;
     RECT  10.541 27.936 11.797 27.96 ;
     RECT  11.689 1.728 11.837 10.872 ;
     RECT  11.329 17.376 11.837 18.696 ;
     RECT  11.837 1.728 11.917 10.536 ;
     RECT  10.835 0.096 11.945 0.168 ;
     RECT  11.725 21.936 11.948 23.016 ;
     RECT  11.185 12.192 11.989 12.312 ;
     RECT  11.917 5.136 12.035 10.536 ;
     RECT  11.948 21.024 12.035 23.016 ;
     RECT  11.333 43.68 12.061 50.232 ;
     RECT  11.989 11.664 12.076 12.312 ;
     RECT  11.797 25.44 12.085 27.96 ;
     RECT  11.689 39.072 12.089 42.696 ;
     RECT  11.837 17.376 12.121 17.928 ;
     RECT  12.085 25.44 12.125 28.152 ;
     RECT  10.069 29.232 12.325 29.64 ;
     RECT  11.797 31.92 12.337 31.944 ;
     RECT  12.089 39.168 12.469 42.696 ;
     RECT  12.061 43.68 12.469 49.08 ;
     RECT  12.157 15.168 12.481 15.48 ;
     RECT  11.027 24.336 12.481 24.36 ;
     RECT  12.076 12.192 12.589 12.312 ;
     RECT  11.257 34.8 12.661 35.16 ;
     RECT  12.337 31.92 12.733 32.376 ;
     RECT  12.661 0.528 12.755 0.552 ;
     RECT  12.125 28.128 12.769 28.152 ;
     RECT  12.325 29.232 12.769 30.264 ;
     RECT  12.035 21.936 12.805 23.016 ;
     RECT  12.769 28.128 12.841 30.264 ;
     RECT  12.121 16.944 12.877 17.928 ;
     RECT  12.481 15.12 13.052 15.48 ;
     RECT  13.052 14.784 13.055 15.48 ;
     RECT  12.035 5.136 13.093 10.104 ;
     RECT  12.125 25.44 13.093 27.144 ;
     RECT  12.841 28.128 13.093 30.36 ;
     RECT  12.469 39.168 13.093 49.08 ;
     RECT  12.061 50.208 13.093 50.232 ;
     RECT  13.055 14.208 13.129 15.48 ;
     RECT  12.877 16.56 13.129 17.928 ;
     RECT  11.917 1.728 13.165 3.864 ;
     RECT  13.093 5.136 13.165 10.92 ;
     RECT  12.733 31.488 13.165 32.376 ;
     RECT  12.913 52.992 13.205 53.016 ;
     RECT  13.165 1.728 13.208 10.92 ;
     RECT  12.589 12.192 13.208 13.128 ;
     RECT  13.129 14.208 13.208 17.928 ;
     RECT  12.805 21.936 13.208 23.064 ;
     RECT  12.481 24.192 13.208 24.36 ;
     RECT  13.093 25.44 13.208 30.36 ;
     RECT  13.165 31.488 13.208 33.048 ;
     RECT  12.661 34.128 13.208 35.16 ;
     RECT  11.699 36.24 13.208 37.08 ;
     RECT  13.093 39.168 13.208 50.232 ;
     RECT  12.877 51.36 13.208 51.384 ;
     RECT  13.208 1.728 13.312 51.852 ;
     RECT  13.312 1.728 13.504 51.582 ;
     RECT  13.504 27.888 13.565 30.36 ;
     RECT  13.504 15.408 13.619 16.584 ;
     RECT  13.619 15.408 13.637 16.152 ;
     RECT  13.504 34.128 13.715 51.384 ;
     RECT  13.715 37.68 13.737 51.384 ;
     RECT  13.565 28.416 13.781 30.36 ;
     RECT  13.737 42.192 13.781 51.384 ;
     RECT  13.504 21.12 13.853 21.96 ;
     RECT  13.504 23.904 13.853 24.216 ;
     RECT  13.504 25.2 13.853 26.904 ;
     RECT  13.853 25.2 13.997 25.464 ;
     RECT  13.781 44.448 14.147 51.096 ;
     RECT  14.147 44.448 14.249 49.464 ;
     RECT  13.093 0.576 14.281 0.6 ;
     RECT  13.504 1.728 14.281 12.888 ;
     RECT  13.853 26.64 14.284 26.904 ;
     RECT  13.715 34.128 14.339 36.264 ;
     RECT  14.281 0.576 14.483 12.888 ;
     RECT  13.504 31.488 14.485 32.952 ;
     RECT  14.485 31.488 14.531 33 ;
     RECT  14.339 34.128 14.531 34.152 ;
     RECT  14.249 46.272 14.537 49.464 ;
     RECT  14.249 44.448 14.609 45.096 ;
     RECT  14.483 1.728 14.689 12.888 ;
     RECT  13.853 21.12 14.749 21.144 ;
     RECT  13.781 28.416 14.785 29.736 ;
     RECT  13.737 37.68 14.785 41.112 ;
     RECT  14.689 1.776 14.789 12.888 ;
     RECT  13.637 15.408 14.831 16.056 ;
     RECT  14.531 31.488 14.861 31.8 ;
     RECT  14.339 35.136 14.897 36.264 ;
     RECT  14.609 44.448 14.897 45.048 ;
     RECT  14.749 20.544 14.929 21.144 ;
     RECT  14.897 44.928 14.933 45.048 ;
     RECT  14.929 20.16 14.965 21.144 ;
     RECT  14.531 32.976 14.969 33 ;
     RECT  14.965 19.344 15.001 21.144 ;
     RECT  14.897 36.24 15.005 36.264 ;
     RECT  14.785 17.088 15.02 17.112 ;
     RECT  14.831 15.408 15.037 16.104 ;
     RECT  15.02 17.088 15.037 17.544 ;
     RECT  14.933 44.928 15.077 45 ;
     RECT  13.997 25.296 15.107 25.464 ;
     RECT  15.077 44.976 15.149 45 ;
     RECT  14.785 28.416 15.181 30.024 ;
     RECT  13.853 23.904 15.217 23.928 ;
     RECT  15.181 27.984 15.217 30.024 ;
     RECT  14.785 37.68 15.217 41.208 ;
     RECT  15.217 23.52 15.257 23.928 ;
     RECT  13.781 42.192 15.26 42.696 ;
     RECT  15.217 36.96 15.301 41.208 ;
     RECT  15.26 42.192 15.301 43.512 ;
     RECT  14.537 46.512 15.325 49.464 ;
     RECT  14.147 51.072 15.325 51.096 ;
     RECT  15.301 36.96 15.347 43.512 ;
     RECT  15.001 19.344 15.395 21.192 ;
     RECT  15.347 36.96 15.401 42.216 ;
     RECT  15.073 0.528 15.469 0.552 ;
     RECT  14.897 35.136 15.469 35.16 ;
     RECT  15.325 46.512 15.473 51.096 ;
     RECT  15.473 46.512 15.509 50.232 ;
     RECT  15.107 25.296 15.545 25.32 ;
     RECT  15.509 50.016 15.545 50.232 ;
     RECT  15.217 27.984 15.581 30.696 ;
     RECT  15.509 46.512 15.581 48.984 ;
     RECT  15.395 20.16 15.617 21.192 ;
     RECT  15.401 37.104 15.617 40.92 ;
     RECT  15.581 46.512 15.617 48.408 ;
     RECT  15.548 22.176 15.635 22.2 ;
     RECT  14.789 2.304 15.649 12.888 ;
     RECT  15.401 42.192 15.725 42.216 ;
     RECT  15.037 15.408 15.733 17.544 ;
     RECT  15.649 2.304 15.779 13.656 ;
     RECT  15.469 34.992 15.797 35.16 ;
     RECT  15.733 15.264 15.833 17.544 ;
     RECT  15.833 15.744 15.901 17.544 ;
     RECT  15.779 2.304 15.941 12.84 ;
     RECT  15.617 46.752 15.941 48.408 ;
     RECT  14.284 26.736 15.98 26.904 ;
     RECT  15.581 27.984 15.98 29.016 ;
     RECT  14.861 31.776 16.009 31.8 ;
     RECT  15.617 37.104 16.013 40.824 ;
     RECT  15.941 2.304 16.045 12.36 ;
     RECT  15.617 20.88 16.049 21.192 ;
     RECT  15.98 26.736 16.067 29.016 ;
     RECT  16.045 2.256 16.211 12.36 ;
     RECT  15.257 23.52 16.265 23.544 ;
     RECT  15.581 30.24 16.265 30.696 ;
     RECT  16.067 26.736 16.369 26.904 ;
     RECT  16.009 31.776 16.369 32.376 ;
     RECT  15.397 33.6 16.369 33.624 ;
     RECT  15.469 0.48 16.441 0.552 ;
     RECT  16.225 1.728 16.441 1.8 ;
     RECT  16.369 31.776 16.441 33.624 ;
     RECT  16.441 31.344 16.508 33.624 ;
     RECT  15.797 34.992 16.508 35.016 ;
     RECT  16.508 31.344 16.595 35.016 ;
     RECT  16.441 22.368 16.625 22.392 ;
     RECT  16.067 27.984 16.625 29.016 ;
     RECT  16.441 0.48 16.693 1.8 ;
     RECT  16.013 37.104 16.697 40.68 ;
     RECT  16.693 0.192 16.729 1.8 ;
     RECT  16.369 26.112 16.765 26.904 ;
     RECT  16.595 34.896 16.801 35.016 ;
     RECT  16.693 36.048 16.801 36.072 ;
     RECT  15.901 15.744 16.805 17.928 ;
     RECT  16.595 31.344 16.805 33.624 ;
     RECT  16.729 0.096 16.813 1.8 ;
     RECT  15.545 50.208 16.837 50.232 ;
     RECT  16.697 37.104 16.841 39.672 ;
     RECT  16.801 34.896 16.909 36.072 ;
     RECT  16.841 37.104 16.909 38.184 ;
     RECT  16.729 43.152 16.909 43.176 ;
     RECT  16.265 30.24 16.913 30.264 ;
     RECT  16.909 34.896 16.949 38.184 ;
     RECT  16.604 24.816 16.981 24.84 ;
     RECT  16.765 26.064 16.981 26.904 ;
     RECT  15.941 47.808 16.985 48.408 ;
     RECT  16.837 49.488 17.021 50.232 ;
     RECT  16.697 40.656 17.053 40.68 ;
     RECT  16.693 22.272 17.093 22.296 ;
     RECT  16.805 31.344 17.093 33.384 ;
     RECT  17.093 31.392 17.123 33.384 ;
     RECT  16.949 37.008 17.123 38.184 ;
     RECT  16.837 13.488 17.125 13.512 ;
     RECT  16.985 47.808 17.129 48.168 ;
     RECT  16.211 2.832 17.161 12.36 ;
     RECT  17.125 13.488 17.161 13.848 ;
     RECT  16.909 42.912 17.165 43.176 ;
     RECT  16.049 21.12 17.173 21.192 ;
     RECT  16.813 0.144 17.189 1.8 ;
     RECT  17.161 2.832 17.189 13.848 ;
     RECT  15.941 46.752 17.197 46.776 ;
     RECT  17.173 21.12 17.219 22.056 ;
     RECT  16.805 15.744 17.233 17.64 ;
     RECT  16.949 34.896 17.237 35.976 ;
     RECT  16.625 28.128 17.273 29.016 ;
     RECT  17.123 31.392 17.273 32.376 ;
     RECT  17.165 42.912 17.309 42.936 ;
     RECT  17.233 15.264 17.365 17.64 ;
     RECT  16.549 51.312 17.381 51.336 ;
     RECT  17.123 33.36 17.417 33.384 ;
     RECT  17.189 0.144 17.449 13.848 ;
     RECT  17.449 0.144 17.459 13.944 ;
     RECT  17.459 0.144 17.507 4.008 ;
     RECT  17.507 0.192 17.651 4.008 ;
     RECT  17.459 5.136 17.665 13.944 ;
     RECT  17.365 15.216 17.665 17.64 ;
     RECT  17.197 46.752 17.665 46.92 ;
     RECT  17.521 20.4 17.845 20.424 ;
     RECT  17.804 42.432 17.845 42.744 ;
     RECT  17.845 20.112 17.953 20.424 ;
     RECT  17.123 37.056 18.025 38.184 ;
     RECT  16.841 39.36 18.025 39.672 ;
     RECT  17.053 40.656 18.025 40.824 ;
     RECT  18.025 50.64 18.133 50.664 ;
     RECT  17.665 46.608 18.169 46.92 ;
     RECT  17.129 48 18.169 48.168 ;
     RECT  17.273 28.512 18.205 29.016 ;
     RECT  17.053 30 18.205 30.024 ;
     RECT  17.237 34.896 18.205 35.016 ;
     RECT  18.169 46.608 18.229 48.168 ;
     RECT  16.981 24.816 18.241 26.904 ;
     RECT  18.205 28.512 18.385 30.024 ;
     RECT  17.273 31.392 18.385 32.28 ;
     RECT  17.651 0.192 18.469 0.312 ;
     RECT  17.021 49.488 18.469 49.512 ;
     RECT  18.133 50.496 18.469 50.664 ;
     RECT  18.169 43.824 18.493 43.848 ;
     RECT  18.385 44.88 18.493 44.904 ;
     RECT  18.205 34.32 18.565 35.016 ;
     RECT  17.651 1.632 18.569 4.008 ;
     RECT  18.569 1.728 18.608 4.008 ;
     RECT  17.665 5.136 18.608 17.64 ;
     RECT  17.953 19.248 18.608 20.424 ;
     RECT  17.219 21.888 18.608 22.056 ;
     RECT  18.241 24.096 18.608 26.904 ;
     RECT  18.385 28.512 18.608 32.28 ;
     RECT  18.565 34.08 18.608 35.016 ;
     RECT  18.025 37.056 18.608 40.824 ;
     RECT  17.845 42.288 18.608 42.744 ;
     RECT  18.493 43.824 18.608 44.904 ;
     RECT  18.229 46.608 18.608 48.504 ;
     RECT  18.469 49.488 18.608 50.664 ;
     RECT  18.469 0.096 18.611 0.312 ;
     RECT  18.608 1.728 18.712 51.852 ;
     RECT  18.712 1.728 18.904 51.582 ;
     RECT  18.904 2.832 19.145 4.008 ;
     RECT  18.904 26.064 19.145 27.48 ;
     RECT  18.611 0.096 19.235 0.264 ;
     RECT  18.904 28.512 19.253 31.56 ;
     RECT  18.904 43.824 19.289 45 ;
     RECT  18.904 1.728 19.325 1.752 ;
     RECT  19.253 28.944 19.427 31.56 ;
     RECT  18.904 5.136 19.433 17.64 ;
     RECT  18.904 22.032 19.433 24.12 ;
     RECT  19.289 43.824 19.433 44.616 ;
     RECT  19.145 26.064 19.475 27.336 ;
     RECT  19.235 0.24 19.505 0.264 ;
     RECT  19.427 28.944 19.523 30.984 ;
     RECT  18.904 36.48 19.613 39.864 ;
     RECT  19.433 22.08 19.685 24.12 ;
     RECT  19.523 30.672 19.685 30.984 ;
     RECT  18.904 41.952 19.756 42.744 ;
     RECT  19.523 28.944 19.829 29.64 ;
     RECT  18.904 32.64 19.829 33.432 ;
     RECT  19.613 37.728 19.957 39.864 ;
     RECT  19.145 2.832 20.005 3.96 ;
     RECT  18.904 20.928 20.005 20.952 ;
     RECT  19.756 42.528 20.009 42.744 ;
     RECT  19.433 13.056 20.053 17.64 ;
     RECT  18.904 18.768 20.053 19.416 ;
     RECT  20.012 24.48 20.053 24.504 ;
     RECT  19.475 26.064 20.053 26.904 ;
     RECT  20.053 24.48 20.099 26.904 ;
     RECT  20.077 41.472 20.113 41.496 ;
     RECT  20.005 2.64 20.149 3.96 ;
     RECT  19.433 5.136 20.189 11.976 ;
     RECT  19.957 37.728 20.221 40.008 ;
     RECT  20.113 41.376 20.221 41.496 ;
     RECT  18.904 50.64 20.221 51.288 ;
     RECT  20.221 50.112 20.245 51.288 ;
     RECT  20.005 20.592 20.261 20.952 ;
     RECT  19.829 32.64 20.261 32.664 ;
     RECT  20.245 50.112 20.291 51.336 ;
     RECT  20.261 20.592 20.297 20.616 ;
     RECT  20.291 50.112 20.305 50.136 ;
     RECT  20.099 25.056 20.387 26.904 ;
     RECT  20.189 5.232 20.405 11.976 ;
     RECT  18.904 46.368 20.435 48.504 ;
     RECT  20.387 25.152 20.437 26.904 ;
     RECT  20.365 27.888 20.437 27.912 ;
     RECT  18.904 34.464 20.483 35.016 ;
     RECT  19.433 44.256 20.501 44.616 ;
     RECT  20.501 43.872 20.545 44.616 ;
     RECT  20.221 37.728 20.549 41.496 ;
     RECT  19.613 36.48 20.617 36.696 ;
     RECT  20.549 37.728 20.617 40.44 ;
     RECT  20.549 41.472 20.621 41.496 ;
     RECT  19.829 28.944 20.627 28.968 ;
     RECT  19.685 30.96 20.761 30.984 ;
     RECT  20.405 5.28 20.797 11.976 ;
     RECT  20.053 13.056 20.797 19.416 ;
     RECT  20.545 43.872 20.797 45.288 ;
     RECT  20.009 42.72 20.873 42.744 ;
     RECT  20.797 5.28 20.941 19.416 ;
     RECT  20.941 5.28 20.981 19.944 ;
     RECT  20.617 36.48 21.089 40.44 ;
     RECT  21.089 37.584 21.125 40.44 ;
     RECT  19.685 22.08 21.161 23.4 ;
     RECT  21.125 39.216 21.269 40.44 ;
     RECT  21.161 22.08 21.301 22.776 ;
     RECT  20.797 43.872 21.301 45.384 ;
     RECT  21.269 39.696 21.341 40.44 ;
     RECT  21.341 39.696 21.347 39.912 ;
     RECT  21.301 43.344 21.347 45.384 ;
     RECT  20.149 2.64 21.373 4.152 ;
     RECT  20.981 5.28 21.373 15.336 ;
     RECT  21.373 2.64 21.413 15.336 ;
     RECT  20.483 34.464 21.449 34.776 ;
     RECT  21.413 2.64 21.485 9.48 ;
     RECT  20.437 25.152 21.521 27.912 ;
     RECT  20.435 46.368 21.589 46.92 ;
     RECT  21.485 2.64 21.625 9.096 ;
     RECT  21.553 41.856 21.625 41.88 ;
     RECT  20.761 30.192 21.685 30.984 ;
     RECT  21.589 46.368 21.769 47.064 ;
     RECT  20.435 48.24 21.769 48.504 ;
     RECT  20.981 16.512 21.772 19.944 ;
     RECT  21.685 30.192 21.773 32.76 ;
     RECT  20.291 51.312 21.779 51.336 ;
     RECT  21.301 21.12 21.845 22.776 ;
     RECT  21.773 30.192 21.845 32.136 ;
     RECT  21.347 44.88 21.877 45.384 ;
     RECT  21.769 46.368 21.877 48.504 ;
     RECT  21.877 44.88 21.881 48.504 ;
     RECT  21.413 10.752 21.917 15.336 ;
     RECT  21.881 44.88 21.917 47.4 ;
     RECT  21.772 16.512 21.923 19.032 ;
     RECT  21.449 34.752 21.983 34.776 ;
     RECT  21.845 30.192 22.021 30.984 ;
     RECT  22.021 29.76 22.057 30.984 ;
     RECT  22.057 29.04 22.067 30.984 ;
     RECT  22.067 29.04 22.093 29.832 ;
     RECT  21.917 10.752 22.097 13.896 ;
     RECT  22.097 10.752 22.133 13.848 ;
     RECT  21.089 36.48 22.165 36.504 ;
     RECT  21.125 37.584 22.165 37.752 ;
     RECT  21.625 2.496 22.169 9.096 ;
     RECT  21.521 25.152 22.205 27.144 ;
     RECT  21.845 22.512 22.237 22.776 ;
     RECT  21.983 34.752 22.237 35.112 ;
     RECT  22.169 2.496 22.313 7.272 ;
     RECT  21.917 45.36 22.349 47.4 ;
     RECT  22.313 4.08 22.421 7.272 ;
     RECT  21.733 50.112 22.457 50.136 ;
     RECT  22.165 36.48 22.489 37.752 ;
     RECT  21.625 41.76 22.489 41.88 ;
     RECT  21.347 43.344 22.489 43.368 ;
     RECT  21.923 18.96 22.565 19.032 ;
     RECT  22.421 4.08 22.595 4.152 ;
     RECT  22.489 36.48 22.597 38.184 ;
     RECT  22.169 8.256 22.633 9.096 ;
     RECT  22.205 26.256 22.633 27.144 ;
     RECT  22.093 28.224 22.633 29.832 ;
     RECT  22.237 22.512 22.637 23.112 ;
     RECT  22.633 8.256 22.739 9.576 ;
     RECT  22.067 30.96 22.745 30.984 ;
     RECT  22.313 2.496 22.777 3.096 ;
     RECT  22.739 9.504 22.789 9.576 ;
     RECT  21.347 39.888 22.789 39.912 ;
     RECT  22.789 39.888 22.837 40.68 ;
     RECT  21.845 32.112 22.853 32.136 ;
     RECT  22.417 48.96 22.885 48.984 ;
     RECT  22.237 34.752 22.921 35.256 ;
     RECT  22.837 39.696 22.924 40.68 ;
     RECT  22.777 2.064 22.925 3.096 ;
     RECT  22.885 48.624 22.925 48.984 ;
     RECT  21.917 15.312 22.957 15.336 ;
     RECT  21.923 16.512 22.957 17.64 ;
     RECT  22.921 34.128 22.993 35.256 ;
     RECT  22.597 36.48 22.993 38.232 ;
     RECT  22.633 26.256 23.029 29.832 ;
     RECT  21.845 21.12 23.104 21.144 ;
     RECT  22.133 12.528 23.281 13.848 ;
     RECT  22.957 15.312 23.281 17.64 ;
     RECT  22.349 45.408 23.317 47.4 ;
     RECT  23.317 45.408 23.353 47.448 ;
     RECT  23.353 45.216 23.533 47.448 ;
     RECT  22.133 10.752 23.569 11.496 ;
     RECT  21.949 24.096 23.569 24.12 ;
     RECT  22.205 25.152 23.569 25.272 ;
     RECT  23.569 10.704 23.605 11.496 ;
     RECT  23.605 10.608 23.677 11.496 ;
     RECT  22.993 34.128 23.713 38.232 ;
     RECT  23.569 24.096 23.749 25.272 ;
     RECT  23.029 26.256 23.749 30.696 ;
     RECT  23.533 45.216 23.852 47.64 ;
     RECT  22.925 48.624 23.852 48.648 ;
     RECT  22.789 9.552 23.857 9.576 ;
     RECT  23.677 10.56 23.857 11.496 ;
     RECT  23.533 31.968 23.857 31.992 ;
     RECT  22.489 41.76 23.857 43.368 ;
     RECT  23.852 45.216 23.857 48.648 ;
     RECT  23.857 31.968 23.893 32.232 ;
     RECT  23.857 45.168 23.893 48.648 ;
     RECT  22.739 8.256 23.929 8.28 ;
     RECT  23.281 12.528 23.929 17.64 ;
     RECT  22.565 18.96 23.929 18.984 ;
     RECT  22.885 22.464 23.965 22.488 ;
     RECT  23.857 41.712 23.965 43.368 ;
     RECT  22.925 2.064 24.008 2.856 ;
     RECT  22.595 4.128 24.008 4.152 ;
     RECT  22.421 5.184 24.008 7.272 ;
     RECT  23.929 8.256 24.008 8.568 ;
     RECT  23.857 9.552 24.008 11.496 ;
     RECT  23.929 12.528 24.008 18.984 ;
     RECT  23.104 21.12 24.008 21.192 ;
     RECT  23.965 22.464 24.008 22.824 ;
     RECT  23.749 24.096 24.008 30.696 ;
     RECT  23.893 31.776 24.008 32.232 ;
     RECT  23.713 34.128 24.008 38.424 ;
     RECT  22.924 39.84 24.008 40.68 ;
     RECT  23.965 41.664 24.008 43.368 ;
     RECT  23.893 44.976 24.008 48.648 ;
     RECT  23.317 51.072 24.008 51.096 ;
     RECT  24.008 2.064 24.304 51.852 ;
     RECT  24.304 13.056 24.419 13.08 ;
     RECT  24.304 40.032 24.419 50.76 ;
     RECT  24.304 2.064 24.437 6.6 ;
     RECT  24.304 21.744 24.467 32.328 ;
     RECT  24.433 52.464 24.545 52.488 ;
     RECT  24.304 16.512 24.563 19.56 ;
     RECT  24.419 40.032 24.563 49.08 ;
     RECT  24.476 53.904 24.563 53.928 ;
     RECT  24.304 20.544 24.581 20.568 ;
     RECT  24.304 8.256 24.589 9.096 ;
     RECT  24.563 40.032 24.689 48.984 ;
     RECT  24.304 33.6 24.697 33.624 ;
     RECT  24.467 28.416 24.761 32.328 ;
     RECT  24.437 3.408 24.833 6.6 ;
     RECT  24.761 29.04 24.977 32.328 ;
     RECT  24.304 10.08 25.049 11.976 ;
     RECT  24.563 19.536 25.049 19.56 ;
     RECT  24.467 21.744 25.121 27.144 ;
     RECT  25.121 21.936 25.157 27.144 ;
     RECT  24.977 29.04 25.157 32.232 ;
     RECT  24.689 42 25.187 48.984 ;
     RECT  25.187 48.768 25.228 48.984 ;
     RECT  24.304 37.968 25.441 38.424 ;
     RECT  24.419 50.688 25.441 50.76 ;
     RECT  24.304 35.04 25.445 36.936 ;
     RECT  25.445 35.568 25.477 36.936 ;
     RECT  25.441 37.968 25.477 38.472 ;
     RECT  25.157 29.04 25.481 31.8 ;
     RECT  25.157 21.936 25.517 25.272 ;
     RECT  25.049 11.04 25.549 11.976 ;
     RECT  25.517 23.664 25.553 25.272 ;
     RECT  24.689 40.032 25.571 40.44 ;
     RECT  24.833 3.408 25.589 5.544 ;
     RECT  24.563 16.512 25.621 17.64 ;
     RECT  25.477 35.568 25.661 38.664 ;
     RECT  24.833 6.576 25.669 6.6 ;
     RECT  25.621 49.008 25.685 49.032 ;
     RECT  25.441 50.688 25.685 50.856 ;
     RECT  25.685 49.008 25.693 50.856 ;
     RECT  25.441 33.552 25.697 33.576 ;
     RECT  25.621 16.224 25.729 17.64 ;
     RECT  25.661 36.144 25.729 38.664 ;
     RECT  25.187 42 25.763 47.304 ;
     RECT  24.589 8.256 25.765 8.568 ;
     RECT  25.669 6.576 25.769 6.888 ;
     RECT  25.693 49.008 25.769 50.904 ;
     RECT  25.58 53.904 25.811 53.928 ;
     RECT  25.763 42 25.837 42.024 ;
     RECT  25.549 11.04 25.877 12.216 ;
     RECT  25.571 40.032 25.877 40.056 ;
     RECT  25.729 36.144 25.913 38.76 ;
     RECT  25.589 3.984 25.949 5.544 ;
     RECT  25.553 23.664 26.021 23.688 ;
     RECT  25.909 33.792 26.021 33.816 ;
     RECT  25.769 6.576 26.053 6.6 ;
     RECT  25.769 50.544 26.053 50.904 ;
     RECT  25.769 49.008 26.057 49.032 ;
     RECT  25.157 26.88 26.06 27.144 ;
     RECT  25.877 11.04 26.093 11.976 ;
     RECT  26.06 26.88 26.101 27.912 ;
     RECT  25.481 29.04 26.101 31.224 ;
     RECT  26.101 26.88 26.147 31.224 ;
     RECT  25.517 21.936 26.165 22.488 ;
     RECT  26.147 28.416 26.165 31.224 ;
     RECT  25.763 43.056 26.165 47.304 ;
     RECT  26.093 11.04 26.197 11.784 ;
     RECT  25.765 8.256 26.233 9 ;
     RECT  26.197 10.944 26.233 11.784 ;
     RECT  26.149 20.832 26.236 20.856 ;
     RECT  25.729 15.984 26.341 17.64 ;
     RECT  26.165 44.352 26.345 47.304 ;
     RECT  26.147 26.88 26.413 27.336 ;
     RECT  26.389 47.856 26.476 47.88 ;
     RECT  25.801 19.776 26.485 19.8 ;
     RECT  26.233 8.256 26.489 9.096 ;
     RECT  26.389 53.04 26.489 53.064 ;
     RECT  26.165 43.056 26.525 43.368 ;
     RECT  26.053 6.384 26.597 6.6 ;
     RECT  24.437 2.064 26.629 2.088 ;
     RECT  25.553 24.912 26.629 25.272 ;
     RECT  26.413 26.736 26.629 27.336 ;
     RECT  25.837 41.808 26.629 42.024 ;
     RECT  26.629 2.064 26.773 2.808 ;
     RECT  25.949 3.984 26.773 5.208 ;
     RECT  26.233 10.848 26.773 11.784 ;
     RECT  26.773 10.368 26.849 11.784 ;
     RECT  26.165 28.416 26.867 29.784 ;
     RECT  26.629 24.912 26.876 27.336 ;
     RECT  26.341 15.984 26.881 18.168 ;
     RECT  26.485 19.584 26.881 19.8 ;
     RECT  26.867 28.416 26.893 28.44 ;
     RECT  25.913 36.48 26.921 38.76 ;
     RECT  26.629 40.848 26.921 42.024 ;
     RECT  26.921 36.48 26.953 38.136 ;
     RECT  26.876 24.144 26.963 27.336 ;
     RECT  26.965 32.928 26.989 32.952 ;
     RECT  26.989 32.448 27.052 32.952 ;
     RECT  26.165 21.936 27.061 21.96 ;
     RECT  26.881 15.984 27.101 19.8 ;
     RECT  26.867 29.472 27.173 29.784 ;
     RECT  26.053 50.544 27.205 51.336 ;
     RECT  26.773 2.064 27.277 5.208 ;
     RECT  27.101 16.416 27.347 19.8 ;
     RECT  26.345 44.352 27.349 46.776 ;
     RECT  26.953 35.952 27.353 38.136 ;
     RECT  26.963 25.344 27.385 27.336 ;
     RECT  27.205 50.544 27.421 51.384 ;
     RECT  27.349 48.288 27.457 48.312 ;
     RECT  27.277 2.064 27.461 5.256 ;
     RECT  27.347 17.424 27.461 17.976 ;
     RECT  27.349 44.352 27.461 47.304 ;
     RECT  27.385 25.344 27.569 28.248 ;
     RECT  27.353 35.952 27.569 38.088 ;
     RECT  27.457 48.288 27.637 48.456 ;
     RECT  26.921 40.848 27.713 41.832 ;
     RECT  26.849 10.368 27.733 11.112 ;
     RECT  26.489 8.592 27.749 8.808 ;
     RECT  27.347 16.416 27.785 16.44 ;
     RECT  26.165 31.2 27.817 31.224 ;
     RECT  27.052 32.448 27.817 32.472 ;
     RECT  27.733 9.984 27.82 11.112 ;
     RECT  27.817 31.2 27.857 32.472 ;
     RECT  26.525 43.248 27.877 43.368 ;
     RECT  27.461 44.352 27.877 46.776 ;
     RECT  27.713 41.808 27.923 41.832 ;
     RECT  27.061 21.552 27.925 21.96 ;
     RECT  27.205 23.184 27.925 23.352 ;
     RECT  27.877 43.248 27.961 46.776 ;
     RECT  27.421 50.544 27.971 51.72 ;
     RECT  27.82 10.272 27.997 11.112 ;
     RECT  27.961 43.104 28.012 46.776 ;
     RECT  27.569 35.952 28.033 35.976 ;
     RECT  27.997 10.272 28.108 11.4 ;
     RECT  27.925 21.552 28.145 23.352 ;
     RECT  26.597 6.576 28.165 6.6 ;
     RECT  27.961 13.296 28.217 13.32 ;
     RECT  28.145 21.552 28.217 23.16 ;
     RECT  26.089 34.176 28.249 34.2 ;
     RECT  28.033 35.712 28.249 35.976 ;
     RECT  27.569 25.344 28.253 27.336 ;
     RECT  28.012 43.104 28.285 45 ;
     RECT  28.217 21.552 28.361 22.728 ;
     RECT  27.971 50.832 28.361 51.72 ;
     RECT  28.249 34.176 28.397 35.976 ;
     RECT  27.173 29.712 28.429 29.784 ;
     RECT  27.857 31.2 28.429 31.896 ;
     RECT  27.637 48.144 28.453 48.456 ;
     RECT  28.405 49.44 28.453 49.464 ;
     RECT  28.012 45.984 28.463 46.776 ;
     RECT  28.453 48.144 28.463 49.464 ;
     RECT  27.749 8.736 28.501 8.808 ;
     RECT  28.429 29.712 28.501 31.896 ;
     RECT  27.461 2.064 28.537 4.152 ;
     RECT  27.461 5.184 28.537 5.256 ;
     RECT  26.989 39.216 28.645 39.288 ;
     RECT  28.177 16.368 28.681 16.392 ;
     RECT  28.645 39.216 28.753 39.864 ;
     RECT  28.397 35.712 28.897 35.976 ;
     RECT  27.569 37.008 28.897 37.608 ;
     RECT  28.108 11.376 29.041 11.4 ;
     RECT  28.501 8.736 29.077 9 ;
     RECT  28.165 6.576 29.113 7.224 ;
     RECT  29.077 8.256 29.113 9 ;
     RECT  28.253 26.208 29.221 27.336 ;
     RECT  28.501 29.04 29.221 31.896 ;
     RECT  28.465 25.104 29.269 25.128 ;
     RECT  29.221 26.208 29.269 31.896 ;
     RECT  29.149 33.024 29.269 33.048 ;
     RECT  28.397 34.176 29.269 34.2 ;
     RECT  28.897 35.712 29.269 37.608 ;
     RECT  28.753 38.736 29.269 39.864 ;
     RECT  28.537 2.064 29.408 5.256 ;
     RECT  29.113 6.576 29.408 9 ;
     RECT  28.108 10.272 29.408 10.296 ;
     RECT  29.041 11.376 29.408 12.552 ;
     RECT  24.304 14.4 29.408 14.424 ;
     RECT  28.681 15.456 29.408 16.392 ;
     RECT  27.461 17.424 29.408 17.448 ;
     RECT  27.347 19.296 29.408 19.8 ;
     RECT  28.361 21.552 29.408 21.816 ;
     RECT  29.269 25.104 29.408 31.896 ;
     RECT  29.269 33.024 29.408 34.2 ;
     RECT  29.269 35.712 29.408 39.864 ;
     RECT  28.285 42.192 29.408 45 ;
     RECT  28.463 45.984 29.408 49.464 ;
     RECT  28.361 50.832 29.408 51.432 ;
     RECT  29.408 2.064 29.512 51.852 ;
     RECT  29.512 2.064 29.704 51.582 ;
     RECT  29.704 46.608 29.765 47.448 ;
     RECT  29.704 10.032 29.801 13.368 ;
     RECT  29.704 34.176 29.801 34.2 ;
     RECT  29.704 2.064 29.873 9 ;
     RECT  29.765 47.328 29.945 47.448 ;
     RECT  29.801 10.032 29.981 12.072 ;
     RECT  29.704 44.976 29.981 45.24 ;
     RECT  29.873 2.064 30.089 8.52 ;
     RECT  29.704 25.2 30.089 25.56 ;
     RECT  29.801 13.344 30.233 13.368 ;
     RECT  29.704 15.744 30.305 17.064 ;
     RECT  30.089 25.2 30.341 25.224 ;
     RECT  29.981 45.216 30.341 45.24 ;
     RECT  30.305 15.84 30.413 17.064 ;
     RECT  29.704 21.648 30.485 23.16 ;
     RECT  29.704 43.296 30.557 43.656 ;
     RECT  29.704 40.992 30.652 42.216 ;
     RECT  30.413 16.368 30.701 17.064 ;
     RECT  29.704 29.76 30.769 31.224 ;
     RECT  29.704 36.048 30.809 39.384 ;
     RECT  30.769 28.944 30.841 31.224 ;
     RECT  30.809 36.192 30.845 39.384 ;
     RECT  30.652 42.192 30.845 42.216 ;
     RECT  29.704 18.144 30.889 20.088 ;
     RECT  30.089 3.936 30.917 8.52 ;
     RECT  30.089 2.064 30.953 2.472 ;
     RECT  30.917 4.032 30.953 8.52 ;
     RECT  29.704 48.48 30.953 50.712 ;
     RECT  29.945 47.328 30.977 47.352 ;
     RECT  30.953 4.272 31.021 8.52 ;
     RECT  30.977 46.704 31.061 47.352 ;
     RECT  31.061 47.28 31.133 47.352 ;
     RECT  29.981 10.032 31.169 12.024 ;
     RECT  30.953 48.48 31.169 49.896 ;
     RECT  30.652 40.992 31.201 41.016 ;
     RECT  31.201 40.464 31.241 41.016 ;
     RECT  29.704 32.688 31.273 33.048 ;
     RECT  30.805 13.632 31.309 13.656 ;
     RECT  30.485 21.648 31.313 21.816 ;
     RECT  30.709 24.192 31.313 24.216 ;
     RECT  30.845 36.192 31.313 38.808 ;
     RECT  31.169 11.04 31.345 12.024 ;
     RECT  30.557 43.632 31.381 43.656 ;
     RECT  31.021 4.272 31.385 8.616 ;
     RECT  31.169 49.872 31.421 49.896 ;
     RECT  31.34 44.976 31.427 45 ;
     RECT  31.169 48.48 31.457 48.504 ;
     RECT  31.381 46.176 31.529 46.2 ;
     RECT  31.385 4.512 31.532 8.616 ;
     RECT  29.704 26.88 31.561 27.336 ;
     RECT  30.889 18.144 31.601 18.84 ;
     RECT  31.532 4.512 31.619 9 ;
     RECT  30.841 28.944 31.619 31.464 ;
     RECT  31.561 26.208 31.645 27.912 ;
     RECT  31.619 29.76 31.717 31.464 ;
     RECT  31.645 26.208 31.741 27.144 ;
     RECT  31.273 32.688 31.763 33.432 ;
     RECT  31.345 11.04 31.813 12.36 ;
     RECT  31.309 13.344 31.813 13.656 ;
     RECT  30.485 23.136 31.813 23.16 ;
     RECT  31.717 29.76 31.817 31.704 ;
     RECT  30.953 2.064 31.849 2.088 ;
     RECT  31.241 40.464 31.849 40.488 ;
     RECT  31.813 11.04 31.885 13.656 ;
     RECT  31.525 34.848 31.885 34.872 ;
     RECT  31.763 33.264 31.889 33.432 ;
     RECT  31.849 39.888 31.889 40.488 ;
     RECT  30.701 16.512 31.925 17.064 ;
     RECT  31.885 11.04 31.955 14.28 ;
     RECT  31.619 4.512 31.961 8.808 ;
     RECT  31.313 36.192 31.961 38.76 ;
     RECT  31.381 43.632 31.961 43.704 ;
     RECT  31.133 47.28 31.961 47.304 ;
     RECT  31.961 43.632 32.033 43.656 ;
     RECT  31.777 0.432 32.065 0.456 ;
     RECT  31.849 1.68 32.065 2.088 ;
     RECT  31.925 16.512 32.069 16.536 ;
     RECT  30.889 20.064 32.069 20.088 ;
     RECT  31.889 33.264 32.141 33.288 ;
     RECT  31.955 11.04 32.213 11.064 ;
     RECT  31.955 12.528 32.281 14.28 ;
     RECT  31.669 15.264 32.281 15.288 ;
     RECT  31.169 10.032 32.285 10.056 ;
     RECT  32.281 12.528 32.285 15.288 ;
     RECT  32.065 0.432 32.317 2.088 ;
     RECT  31.889 39.888 32.357 39.912 ;
     RECT  32.281 42.672 32.393 43.176 ;
     RECT  32.285 14.016 32.461 15.288 ;
     RECT  31.885 34.848 32.461 34.92 ;
     RECT  31.601 18.672 32.465 18.84 ;
     RECT  31.817 30.384 32.497 31.704 ;
     RECT  32.281 53.04 32.561 53.064 ;
     RECT  32.461 14.016 32.573 15.384 ;
     RECT  31.813 23.136 32.573 23.208 ;
     RECT  32.317 0.144 32.581 2.088 ;
     RECT  32.581 0.096 32.605 2.088 ;
     RECT  32.461 34.8 32.605 34.92 ;
     RECT  31.961 36.192 32.605 38.184 ;
     RECT  32.605 0.096 32.717 2.28 ;
     RECT  32.317 47.76 32.749 47.784 ;
     RECT  31.961 4.512 32.753 8.616 ;
     RECT  32.285 12.528 32.825 12.552 ;
     RECT  32.533 39.84 32.969 39.864 ;
     RECT  32.605 34.8 33.037 38.184 ;
     RECT  33.037 34.656 33.041 38.184 ;
     RECT  32.497 30.384 33.068 31.896 ;
     RECT  32.821 20.304 33.073 20.328 ;
     RECT  31.313 21.792 33.073 21.816 ;
     RECT  32.573 14.256 33.107 15.384 ;
     RECT  32.753 4.704 33.109 8.616 ;
     RECT  33.068 29.76 33.109 31.896 ;
     RECT  33.107 14.256 33.113 14.856 ;
     RECT  33.073 21.792 33.113 21.96 ;
     RECT  33.061 16.512 33.148 17.064 ;
     RECT  33.109 4.704 33.149 8.76 ;
     RECT  33.149 7.92 33.181 8.76 ;
     RECT  33.109 29.04 33.181 31.896 ;
     RECT  33.073 19.68 33.185 20.328 ;
     RECT  33.041 34.656 33.212 37.08 ;
     RECT  32.749 47.76 33.24 47.88 ;
     RECT  32.561 52.416 33.253 53.064 ;
     RECT  33.24 47.184 33.289 47.88 ;
     RECT  33.245 33.024 33.329 33.048 ;
     RECT  31.741 25.872 33.361 27.144 ;
     RECT  33.181 28.704 33.361 31.896 ;
     RECT  33.281 49.056 33.365 49.08 ;
     RECT  33.361 25.872 33.397 31.896 ;
     RECT  33.397 25.68 33.401 31.896 ;
     RECT  32.465 18.672 33.433 18.696 ;
     RECT  33.212 34.32 33.443 37.08 ;
     RECT  33.181 7.92 33.469 9.672 ;
     RECT  33.149 4.704 33.473 6.744 ;
     RECT  33.443 34.656 33.545 37.08 ;
     RECT  33.289 46.608 33.577 47.88 ;
     RECT  33.473 6.528 33.581 6.744 ;
     RECT  32.717 0.144 33.587 2.28 ;
     RECT  32.393 43.152 33.613 43.176 ;
     RECT  33.577 46.608 33.613 47.976 ;
     RECT  33.113 14.256 33.653 14.28 ;
     RECT  33.185 20.304 33.653 20.328 ;
     RECT  33.613 43.152 33.692 43.848 ;
     RECT  32.425 45.552 33.692 45.576 ;
     RECT  33.587 0.144 33.713 0.6 ;
     RECT  33.253 52.32 33.733 53.064 ;
     RECT  33.401 25.68 33.761 29.64 ;
     RECT  33.692 43.152 33.779 45.576 ;
     RECT  33.469 7.92 33.793 9.912 ;
     RECT  33.073 12 33.793 12.024 ;
     RECT  33.733 51.888 33.829 53.064 ;
     RECT  33.793 7.92 33.901 10.104 ;
     RECT  33.113 21.936 33.973 21.96 ;
     RECT  32.893 23.328 33.973 23.4 ;
     RECT  33.545 34.752 34.009 37.08 ;
     RECT  33.041 38.112 34.009 38.184 ;
     RECT  33.793 12 34.081 12.744 ;
     RECT  34.081 12 34.117 12.888 ;
     RECT  33.148 16.512 34.117 16.536 ;
     RECT  33.829 51.888 34.117 53.88 ;
     RECT  34.117 51.84 34.121 53.88 ;
     RECT  33.901 7.92 34.153 10.968 ;
     RECT  34.117 12 34.153 13.176 ;
     RECT  32.425 41.904 34.153 41.928 ;
     RECT  33.779 43.296 34.153 45.576 ;
     RECT  33.613 46.608 34.153 48.936 ;
     RECT  34.121 51.84 34.181 53.832 ;
     RECT  32.857 24.48 34.261 24.504 ;
     RECT  33.761 25.68 34.261 25.704 ;
     RECT  34.153 41.904 34.261 42.216 ;
     RECT  33.587 1.728 34.309 2.28 ;
     RECT  34.117 16.512 34.309 17.16 ;
     RECT  33.433 18.24 34.309 18.696 ;
     RECT  33.713 0.096 34.333 0.6 ;
     RECT  34.261 41.664 34.333 42.216 ;
     RECT  32.857 3.6 34.405 3.624 ;
     RECT  33.473 4.704 34.405 5.448 ;
     RECT  33.581 6.624 34.453 6.744 ;
     RECT  34.153 7.92 34.453 13.176 ;
     RECT  34.309 1.728 34.513 2.328 ;
     RECT  33.973 21.936 34.513 23.4 ;
     RECT  34.405 3.6 34.549 5.448 ;
     RECT  34.453 6.624 34.549 13.176 ;
     RECT  34.309 16.512 34.657 18.696 ;
     RECT  34.009 34.752 34.693 38.184 ;
     RECT  34.549 3.6 34.729 13.176 ;
     RECT  34.657 16.512 34.729 19.656 ;
     RECT  34.333 0.048 34.739 0.6 ;
     RECT  33.401 31.2 34.765 31.896 ;
     RECT  34.739 0.048 34.769 0.504 ;
     RECT  34.261 24.48 34.801 25.704 ;
     RECT  33.761 26.784 34.801 29.64 ;
     RECT  34.513 1.728 34.808 2.616 ;
     RECT  34.729 3.6 34.808 13.32 ;
     RECT  34.729 15.984 34.808 19.656 ;
     RECT  34.513 20.976 34.808 23.4 ;
     RECT  34.801 24.48 34.808 29.64 ;
     RECT  34.765 30.864 34.808 31.896 ;
     RECT  34.693 34.752 34.808 38.712 ;
     RECT  34.765 39.84 34.808 39.864 ;
     RECT  34.333 41.472 34.808 42.216 ;
     RECT  34.153 43.296 34.808 48.936 ;
     RECT  34.181 51.792 34.808 53.832 ;
     RECT  34.808 1.728 35.104 53.832 ;
     RECT  35.104 50.112 35.165 53.832 ;
     RECT  35.104 1.728 35.201 14.808 ;
     RECT  35.165 50.112 35.201 51.96 ;
     RECT  35.104 19.632 35.219 23.4 ;
     RECT  35.201 50.112 35.267 51.912 ;
     RECT  35.165 52.992 35.267 53.832 ;
     RECT  35.267 52.992 35.273 53.016 ;
     RECT  35.201 1.776 35.309 14.808 ;
     RECT  35.104 30.768 35.345 38.136 ;
     RECT  35.219 19.632 35.381 23.352 ;
     RECT  35.345 30.768 35.489 35.544 ;
     RECT  35.104 42.576 35.507 43.944 ;
     RECT  35.309 2.064 35.548 14.808 ;
     RECT  35.489 30.768 35.555 34.872 ;
     RECT  35.267 51.552 35.561 51.912 ;
     RECT  35.381 19.632 35.597 22.104 ;
     RECT  35.548 2.064 35.633 14.28 ;
     RECT  35.555 30.768 35.669 31.368 ;
     RECT  35.104 46.608 35.777 48.984 ;
     RECT  34.769 0.096 35.809 0.504 ;
     RECT  35.809 0.048 35.837 0.504 ;
     RECT  35.104 29.04 35.849 29.784 ;
     RECT  35.561 51.552 35.885 51.816 ;
     RECT  35.597 19.632 35.891 21.96 ;
     RECT  35.104 39.84 35.913 41.064 ;
     RECT  35.837 0.048 35.921 0.552 ;
     RECT  35.555 32.448 35.939 34.872 ;
     RECT  35.104 25.2 36.029 27.192 ;
     RECT  35.939 32.448 36.029 33.336 ;
     RECT  35.104 18.192 36.065 18.216 ;
     RECT  35.939 34.608 36.065 34.872 ;
     RECT  35.507 42.576 36.092 42.84 ;
     RECT  35.345 36.576 36.205 38.136 ;
     RECT  35.777 46.752 36.205 48.984 ;
     RECT  35.267 50.112 36.205 50.28 ;
     RECT  35.633 3.408 36.227 14.28 ;
     RECT  35.104 16.992 36.277 17.016 ;
     RECT  36.313 25.104 36.349 25.128 ;
     RECT  36.205 36.576 36.385 38.808 ;
     RECT  35.381 23.328 36.421 23.352 ;
     RECT  36.421 23.136 36.457 23.352 ;
     RECT  35.913 40.56 36.485 41.064 ;
     RECT  36.092 42.528 36.485 42.84 ;
     RECT  36.385 36.576 36.493 39.384 ;
     RECT  36.485 40.56 36.565 42.84 ;
     RECT  35.507 43.92 36.565 43.944 ;
     RECT  36.065 34.608 36.569 34.824 ;
     RECT  36.565 40.56 36.569 43.944 ;
     RECT  35.891 20.448 36.601 21.96 ;
     RECT  36.457 23.136 36.601 23.496 ;
     RECT  36.227 3.408 36.611 8.088 ;
     RECT  35.885 51.552 36.641 51.576 ;
     RECT  36.227 9.12 36.713 14.28 ;
     RECT  35.669 30.864 36.785 31.368 ;
     RECT  36.601 20.448 36.817 23.496 ;
     RECT  36.349 24.48 36.817 25.128 ;
     RECT  35.849 29.04 36.853 29.064 ;
     RECT  36.785 30.864 36.889 31.128 ;
     RECT  36.569 42.192 36.889 43.944 ;
     RECT  36.029 26.208 36.893 27.192 ;
     RECT  35.921 0.048 36.899 0.072 ;
     RECT  36.713 9.12 36.929 13.848 ;
     RECT  36.817 20.448 36.956 25.128 ;
     RECT  36.889 30.624 36.997 31.128 ;
     RECT  36.277 16.992 37.001 17.448 ;
     RECT  36.205 46.752 37.043 50.28 ;
     RECT  36.956 20.352 37.069 25.128 ;
     RECT  36.997 30.528 37.069 31.128 ;
     RECT  36.493 36.528 37.073 39.384 ;
     RECT  37.043 50.256 37.073 50.28 ;
     RECT  37.069 20.352 37.105 25.224 ;
     RECT  36.893 26.208 37.105 27.144 ;
     RECT  37.105 20.352 37.145 27.144 ;
     RECT  37.073 36.528 37.145 39.096 ;
     RECT  35.633 2.064 37.177 2.088 ;
     RECT  35.104 15.984 37.177 16.008 ;
     RECT  37.177 14.832 37.217 16.008 ;
     RECT  37.145 22.8 37.217 27.144 ;
     RECT  37.177 1.152 37.289 2.088 ;
     RECT  36.029 33.072 37.321 33.336 ;
     RECT  37.217 14.832 37.325 15.24 ;
     RECT  37.217 22.8 37.361 24.936 ;
     RECT  36.569 34.656 37.361 34.824 ;
     RECT  36.853 29.04 37.429 29.304 ;
     RECT  37.069 30.288 37.429 31.128 ;
     RECT  37.429 35.28 37.465 35.304 ;
     RECT  37.145 36.528 37.465 38.52 ;
     RECT  36.889 42.192 37.537 44.424 ;
     RECT  37.217 25.92 37.541 27.144 ;
     RECT  37.289 2.064 37.573 2.088 ;
     RECT  36.673 3.264 37.573 3.288 ;
     RECT  37.001 17.088 37.573 17.448 ;
     RECT  36.997 18.768 37.573 18.792 ;
     RECT  37.043 46.752 37.573 49.224 ;
     RECT  37.573 2.064 37.619 3.288 ;
     RECT  36.929 9.504 37.649 13.848 ;
     RECT  36.569 40.56 37.649 41.016 ;
     RECT  37.321 33.024 37.681 33.336 ;
     RECT  37.429 29.04 37.825 31.128 ;
     RECT  37.537 42.192 37.825 45.24 ;
     RECT  37.573 46.272 37.825 49.224 ;
     RECT  37.825 28.656 37.865 31.128 ;
     RECT  37.825 42.192 37.937 49.224 ;
     RECT  37.573 17.088 37.969 18.792 ;
     RECT  37.361 23.136 38.009 24.936 ;
     RECT  37.465 35.28 38.009 38.52 ;
     RECT  36.611 4.512 38.113 8.088 ;
     RECT  37.649 9.504 38.113 9.912 ;
     RECT  37.969 17.04 38.113 18.792 ;
     RECT  38.009 23.376 38.185 24.936 ;
     RECT  37.541 25.92 38.185 25.944 ;
     RECT  38.009 36 38.197 38.52 ;
     RECT  37.325 15.216 38.225 15.24 ;
     RECT  37.649 40.56 38.243 40.92 ;
     RECT  37.789 50.88 38.257 50.904 ;
     RECT  37.649 11.088 38.333 13.848 ;
     RECT  37.681 32.592 38.369 33.336 ;
     RECT  37.865 28.656 38.424 30.6 ;
     RECT  38.185 23.376 38.441 25.944 ;
     RECT  38.197 36 38.513 38.76 ;
     RECT  38.444 0.048 38.531 0.072 ;
     RECT  38.424 28.464 38.572 30.6 ;
     RECT  38.369 33.024 38.653 33.336 ;
     RECT  38.113 4.512 38.689 9.912 ;
     RECT  38.333 11.088 38.689 13.656 ;
     RECT  37.619 2.064 38.725 3.048 ;
     RECT  38.689 4.512 38.725 13.656 ;
     RECT  37.145 20.352 38.729 21.096 ;
     RECT  38.572 30.288 38.765 30.6 ;
     RECT  37.541 27.12 38.773 27.144 ;
     RECT  38.572 28.464 38.773 29.016 ;
     RECT  37.937 43.632 38.833 49.224 ;
     RECT  38.765 30.576 38.873 30.6 ;
     RECT  38.653 33.024 38.876 34.056 ;
     RECT  38.243 40.896 38.905 40.92 ;
     RECT  37.937 42.192 38.905 42.216 ;
     RECT  38.833 43.632 38.905 49.512 ;
     RECT  38.725 2.064 38.945 13.656 ;
     RECT  38.876 33.024 38.945 34.92 ;
     RECT  38.905 42.192 38.945 49.512 ;
     RECT  38.257 50.88 39.005 50.952 ;
     RECT  38.905 40.896 39.049 41.064 ;
     RECT  38.773 27.12 39.053 29.016 ;
     RECT  38.113 16.272 39.085 18.792 ;
     RECT  38.441 23.52 39.085 25.944 ;
     RECT  39.053 27.12 39.085 28.92 ;
     RECT  39.085 16.272 39.157 19.224 ;
     RECT  38.945 42.336 39.481 49.512 ;
     RECT  39.005 50.88 39.481 51.336 ;
     RECT  38.945 2.064 39.539 12.552 ;
     RECT  39.049 40.896 39.637 41.16 ;
     RECT  39.164 53.904 39.697 53.928 ;
     RECT  39.157 15.456 39.733 19.224 ;
     RECT  38.729 20.352 39.733 20.376 ;
     RECT  38.941 21.456 39.733 21.48 ;
     RECT  39.539 2.148 39.949 12.552 ;
     RECT  38.945 13.584 39.949 13.656 ;
     RECT  39.637 40.56 39.949 41.16 ;
     RECT  39.481 42.336 39.949 51.336 ;
     RECT  39.697 53.04 39.985 53.928 ;
     RECT  39.973 32.208 40.057 32.232 ;
     RECT  38.945 33.312 40.057 34.92 ;
     RECT  38.513 36 40.057 38.52 ;
     RECT  39.949 40.56 40.069 51.336 ;
     RECT  39.985 52.416 40.097 53.928 ;
     RECT  39.949 2.148 40.208 13.656 ;
     RECT  39.733 15.456 40.208 20.376 ;
     RECT  39.733 21.456 40.208 21.528 ;
     RECT  39.085 23.52 40.208 28.92 ;
     RECT  40.057 32.208 40.208 34.92 ;
     RECT  40.057 36 40.208 38.712 ;
     RECT  40.069 40.56 40.208 51.384 ;
     RECT  40.097 52.416 40.208 52.488 ;
     RECT  40.208 2.148 40.312 52.488 ;
     RECT  40.312 2.418 40.504 52.488 ;
     RECT  40.504 2.88 40.529 11.448 ;
     RECT  40.504 52.416 40.565 52.488 ;
     RECT  40.504 28.464 40.643 33.576 ;
     RECT  40.504 18.672 40.673 23.592 ;
     RECT  40.529 2.88 40.853 11.256 ;
     RECT  40.673 21.744 40.853 23.592 ;
     RECT  40.565 52.416 40.889 52.44 ;
     RECT  40.853 22.416 40.961 23.592 ;
     RECT  40.504 15.072 41.027 16.584 ;
     RECT  40.643 28.464 41.027 32.472 ;
     RECT  40.504 35.856 41.069 50.904 ;
     RECT  40.961 22.512 41.105 23.592 ;
     RECT  41.069 40.896 41.213 50.904 ;
     RECT  40.853 2.88 41.249 5.832 ;
     RECT  40.853 6.864 41.321 11.256 ;
     RECT  41.213 49.2 41.363 50.904 ;
     RECT  41.027 28.8 41.393 31.32 ;
     RECT  41.321 8.592 41.429 11.256 ;
     RECT  40.673 18.672 41.429 20.616 ;
     RECT  40.504 26.208 41.465 27.144 ;
     RECT  41.213 40.896 41.465 48.12 ;
     RECT  41.429 10.128 41.501 11.256 ;
     RECT  41.027 32.304 41.501 32.472 ;
     RECT  40.504 12.528 41.533 12.552 ;
     RECT  41.533 12.48 41.557 12.552 ;
     RECT  40.504 17.616 41.605 17.64 ;
     RECT  41.429 18.672 41.605 18.696 ;
     RECT  41.605 17.616 41.641 18.696 ;
     RECT  41.557 12.48 41.644 13.08 ;
     RECT  41.363 50.736 41.749 50.904 ;
     RECT  41.249 2.88 41.785 5.16 ;
     RECT  41.393 28.8 41.789 29.256 ;
     RECT  41.465 26.304 41.825 27.144 ;
     RECT  41.069 35.856 41.825 39.624 ;
     RECT  41.501 10.128 41.861 11.208 ;
     RECT  41.644 12.48 41.861 12.792 ;
     RECT  40.097 53.856 41.891 53.928 ;
     RECT  41.321 6.864 41.893 7.224 ;
     RECT  40.504 34.608 41.929 34.632 ;
     RECT  41.105 22.752 41.996 23.592 ;
     RECT  40.504 24.768 41.996 24.792 ;
     RECT  41.027 15.456 42.001 16.008 ;
     RECT  41.641 17.376 42.037 18.696 ;
     RECT  41.996 22.752 42.083 24.792 ;
     RECT  42.001 14.832 42.113 16.008 ;
     RECT  41.429 19.824 42.145 20.616 ;
     RECT  41.785 2.736 42.149 5.16 ;
     RECT  42.037 17.184 42.149 18.696 ;
     RECT  41.749 50.736 42.181 51.096 ;
     RECT  41.465 44.976 42.217 48.12 ;
     RECT  41.363 49.2 42.217 49.512 ;
     RECT  42.149 17.616 42.221 18.696 ;
     RECT  42.145 19.824 42.221 21.24 ;
     RECT  42.221 17.616 42.257 17.64 ;
     RECT  42.083 22.752 42.293 24.552 ;
     RECT  41.893 6.768 42.325 7.224 ;
     RECT  41.429 8.592 42.325 8.616 ;
     RECT  42.221 18.672 42.365 18.696 ;
     RECT  41.825 36.528 42.401 39.624 ;
     RECT  41.891 53.904 42.419 53.928 ;
     RECT  42.325 6.24 42.437 8.616 ;
     RECT  41.393 30.816 42.469 31.32 ;
     RECT  42.217 44.976 42.469 49.512 ;
     RECT  42.181 50.736 42.469 51.336 ;
     RECT  42.469 44.976 42.505 51.336 ;
     RECT  42.149 2.88 42.517 5.16 ;
     RECT  42.437 6.24 42.517 7.992 ;
     RECT  42.221 20.112 42.541 21.24 ;
     RECT  41.465 40.896 42.577 43.944 ;
     RECT  42.505 44.976 42.577 51.528 ;
     RECT  42.577 40.896 42.617 51.528 ;
     RECT  42.617 40.896 42.689 51.336 ;
     RECT  41.861 12.768 42.793 12.792 ;
     RECT  41.825 26.736 42.793 27.144 ;
     RECT  42.689 40.896 42.793 42.168 ;
     RECT  42.541 20.112 42.905 21.288 ;
     RECT  42.793 39.888 42.941 42.168 ;
     RECT  42.941 39.888 42.947 41.88 ;
     RECT  42.689 43.392 42.977 51.336 ;
     RECT  41.861 10.128 43.013 10.2 ;
     RECT  42.113 15.456 43.049 16.008 ;
     RECT  42.977 45.936 43.049 51.336 ;
     RECT  43.049 15.456 43.117 15.768 ;
     RECT  41.789 28.8 43.121 28.824 ;
     RECT  43.049 51.168 43.129 51.336 ;
     RECT  42.793 12.768 43.148 13.512 ;
     RECT  43.049 45.936 43.157 50.184 ;
     RECT  43.148 11.952 43.189 13.512 ;
     RECT  43.117 25.728 43.189 25.752 ;
     RECT  42.793 26.736 43.189 27.24 ;
     RECT  43.189 11.952 43.235 13.704 ;
     RECT  42.947 39.888 43.235 40.44 ;
     RECT  43.157 45.984 43.237 50.184 ;
     RECT  43.237 49.728 43.331 50.184 ;
     RECT  42.905 20.352 43.333 21.288 ;
     RECT  43.117 15.072 43.337 15.768 ;
     RECT  42.947 41.52 43.337 41.88 ;
     RECT  41.501 32.304 43.373 32.328 ;
     RECT  42.293 23.232 43.379 24.552 ;
     RECT  42.401 36.528 43.409 38.712 ;
     RECT  41.929 34.608 43.441 35.496 ;
     RECT  43.189 25.728 43.477 27.24 ;
     RECT  43.379 23.376 43.481 24.552 ;
     RECT  43.235 39.888 43.481 40.344 ;
     RECT  43.477 25.728 43.523 27.336 ;
     RECT  42.517 2.88 43.553 7.992 ;
     RECT  43.235 12 43.571 13.704 ;
     RECT  43.525 10.752 43.612 10.776 ;
     RECT  40.643 33.552 43.628 33.576 ;
     RECT  43.441 34.56 43.628 35.496 ;
     RECT  43.553 3.168 43.657 7.992 ;
     RECT  42.977 43.392 43.661 44.904 ;
     RECT  43.129 51.168 43.661 51.192 ;
     RECT  43.657 3.168 43.693 8.136 ;
     RECT  43.337 41.856 43.763 41.88 ;
     RECT  43.333 20.352 43.769 22.2 ;
     RECT  43.337 15.072 43.801 15.624 ;
     RECT  43.628 33.552 43.82 35.496 ;
     RECT  43.409 36.528 43.82 36.6 ;
     RECT  43.441 17.952 43.841 17.976 ;
     RECT  42.469 30.624 43.901 31.32 ;
     RECT  43.82 33.552 43.907 36.6 ;
     RECT  43.901 30.192 43.909 31.32 ;
     RECT  43.661 43.392 43.913 44.664 ;
     RECT  43.571 12.768 43.949 13.704 ;
     RECT  43.868 28.464 43.955 28.488 ;
     RECT  43.909 29.808 43.955 31.32 ;
     RECT  43.237 45.984 44.021 48.456 ;
     RECT  43.769 20.352 44.129 21.672 ;
     RECT  44.017 50.736 44.129 50.76 ;
     RECT  44.129 20.352 44.161 21.288 ;
     RECT  43.907 33.552 44.197 35.496 ;
     RECT  43.693 3.168 44.237 8.472 ;
     RECT  43.801 14.88 44.237 15.624 ;
     RECT  43.481 23.376 44.237 24.456 ;
     RECT  43.955 29.808 44.237 30.216 ;
     RECT  43.955 31.248 44.483 31.32 ;
     RECT  44.197 33.504 44.483 35.496 ;
     RECT  44.197 18.144 44.492 18.168 ;
     RECT  44.483 33.504 44.525 33.768 ;
     RECT  44.021 46.224 44.525 48.456 ;
     RECT  44.525 46.56 44.561 48.456 ;
     RECT  44.492 18.144 44.579 18.696 ;
     RECT  44.483 31.248 44.597 31.272 ;
     RECT  43.913 43.776 44.629 44.664 ;
     RECT  44.449 0.144 44.665 0.168 ;
     RECT  43.525 9.648 44.701 9.672 ;
     RECT  43.439 16.896 44.737 16.92 ;
     RECT  44.665 28.512 44.737 28.536 ;
     RECT  44.237 14.976 44.809 15.624 ;
     RECT  44.737 16.8 44.809 16.92 ;
     RECT  43.523 27.216 44.845 27.336 ;
     RECT  44.629 42.72 44.881 42.744 ;
     RECT  44.629 43.776 44.881 45.144 ;
     RECT  44.809 14.976 44.924 16.92 ;
     RECT  44.579 18.144 44.924 18.168 ;
     RECT  44.665 0.144 44.989 0.552 ;
     RECT  44.881 42.72 45.013 45.144 ;
     RECT  44.989 0.096 45.025 0.552 ;
     RECT  43.523 25.728 45.025 26.232 ;
     RECT  43.907 36.576 45.133 36.6 ;
     RECT  43.409 37.68 45.133 38.712 ;
     RECT  43.331 49.728 45.169 49.752 ;
     RECT  43.949 13.68 45.205 13.704 ;
     RECT  44.924 14.976 45.205 18.168 ;
     RECT  45.025 25.296 45.313 26.232 ;
     RECT  44.845 27.216 45.313 27.384 ;
     RECT  44.525 33.504 45.421 33.576 ;
     RECT  45.013 42.72 45.421 45.288 ;
     RECT  45.457 52.464 45.529 52.488 ;
     RECT  44.701 9.552 45.565 9.672 ;
     RECT  45.205 13.68 45.565 18.168 ;
     RECT  44.737 28.512 45.565 28.728 ;
     RECT  44.237 29.808 45.565 29.832 ;
     RECT  44.869 12 45.601 12.024 ;
     RECT  45.277 1.728 45.608 1.752 ;
     RECT  44.237 3.168 45.608 3.96 ;
     RECT  44.237 5.04 45.608 8.472 ;
     RECT  45.565 9.552 45.608 10.44 ;
     RECT  45.601 12 45.608 12.312 ;
     RECT  45.565 13.392 45.608 18.168 ;
     RECT  44.161 19.92 45.608 21.288 ;
     RECT  44.237 23.376 45.608 23.88 ;
     RECT  45.313 25.296 45.608 27.384 ;
     RECT  45.565 28.512 45.608 29.832 ;
     RECT  45.421 33.024 45.608 33.576 ;
     RECT  44.483 34.752 45.608 35.496 ;
     RECT  45.133 36.576 45.608 38.712 ;
     RECT  43.481 40.032 45.608 40.344 ;
     RECT  45.421 42 45.608 45.288 ;
     RECT  44.561 46.56 45.608 48.216 ;
     RECT  45.169 49.488 45.608 49.752 ;
     RECT  45.529 52.464 45.608 52.536 ;
     RECT  45.025 0.096 45.683 0.6 ;
     RECT  45.608 1.728 45.904 52.536 ;
     RECT  45.904 32.304 46.019 38.712 ;
     RECT  45.637 53.856 46.037 53.88 ;
     RECT  45.904 40.32 46.073 48.216 ;
     RECT  45.904 50.688 46.076 52.536 ;
     RECT  46.076 50.688 46.163 53.064 ;
     RECT  46.019 32.304 46.211 38.52 ;
     RECT  46.073 43.536 46.217 48.216 ;
     RECT  46.211 34.032 46.252 38.52 ;
     RECT  45.904 1.728 46.253 13.416 ;
     RECT  46.252 34.8 46.253 38.52 ;
     RECT  46.163 50.688 46.259 53.016 ;
     RECT  45.904 28.512 46.289 28.968 ;
     RECT  46.211 32.304 46.289 33.048 ;
     RECT  46.217 44.352 46.289 48.216 ;
     RECT  46.289 32.304 46.361 32.856 ;
     RECT  46.361 32.448 46.397 32.856 ;
     RECT  46.289 28.704 46.433 28.968 ;
     RECT  46.259 50.688 46.649 51.336 ;
     RECT  45.683 0.192 46.693 0.6 ;
     RECT  45.904 23.856 46.739 25.32 ;
     RECT  45.904 26.784 46.739 26.808 ;
     RECT  45.904 29.952 46.757 29.976 ;
     RECT  46.253 1.728 46.793 9.576 ;
     RECT  45.904 14.448 46.793 18.024 ;
     RECT  46.253 11.28 46.829 13.416 ;
     RECT  46.793 15.264 46.829 18.024 ;
     RECT  46.739 23.856 46.829 23.88 ;
     RECT  46.289 44.352 46.829 47.592 ;
     RECT  46.693 0.096 46.861 0.6 ;
     RECT  46.253 35.328 46.865 38.52 ;
     RECT  46.073 40.32 46.897 42.168 ;
     RECT  46.739 25.296 46.937 25.32 ;
     RECT  45.904 20.304 46.988 21.96 ;
     RECT  46.829 11.376 47.009 13.416 ;
     RECT  46.829 44.448 47.009 47.592 ;
     RECT  47.009 44.448 47.045 45.864 ;
     RECT  46.988 19.632 47.075 21.96 ;
     RECT  46.897 39.552 47.077 42.168 ;
     RECT  46.861 0.096 47.123 0.648 ;
     RECT  47.077 38.64 47.132 42.168 ;
     RECT  46.259 52.368 47.141 53.016 ;
     RECT  47.045 44.448 47.153 45.72 ;
     RECT  46.649 50.736 47.219 51.336 ;
     RECT  47.141 52.368 47.225 53.88 ;
     RECT  47.225 52.368 47.257 53.832 ;
     RECT  46.793 1.728 47.261 9.096 ;
     RECT  47.257 51.648 47.261 53.832 ;
     RECT  47.009 11.376 47.297 11.976 ;
     RECT  47.132 38.64 47.297 43.128 ;
     RECT  46.829 15.264 47.333 17.064 ;
     RECT  46.397 32.448 47.401 32.472 ;
     RECT  47.009 46.848 47.401 47.592 ;
     RECT  46.865 35.328 47.404 37.608 ;
     RECT  47.261 1.728 47.411 2.28 ;
     RECT  47.009 13.056 47.437 13.416 ;
     RECT  47.401 32.448 47.437 32.856 ;
     RECT  47.297 38.64 47.441 38.664 ;
     RECT  47.123 0.096 47.507 0.552 ;
     RECT  46.433 28.944 47.545 28.968 ;
     RECT  47.261 3.552 47.549 9.096 ;
     RECT  47.297 40.464 47.557 43.128 ;
     RECT  47.404 35.328 47.581 37.512 ;
     RECT  47.437 31.968 47.689 32.856 ;
     RECT  47.075 20.112 47.693 21.24 ;
     RECT  47.507 0.096 47.699 0.504 ;
     RECT  47.545 28.272 47.749 29.688 ;
     RECT  47.401 46.848 47.797 47.928 ;
     RECT  47.797 18.816 47.833 18.84 ;
     RECT  47.749 28.272 47.836 30.312 ;
     RECT  47.557 40.464 47.837 43.32 ;
     RECT  47.261 53.808 47.843 53.832 ;
     RECT  47.837 40.464 47.945 42.792 ;
     RECT  47.437 13.056 47.977 13.608 ;
     RECT  47.581 34.656 48.053 37.512 ;
     RECT  47.797 46.848 48.083 48.456 ;
     RECT  47.905 22.8 48.085 22.824 ;
     RECT  47.977 50.352 48.085 50.376 ;
     RECT  47.945 41.136 48.125 42.792 ;
     RECT  47.689 31.92 48.197 32.856 ;
     RECT  47.297 11.952 48.229 11.976 ;
     RECT  47.977 13.008 48.229 13.608 ;
     RECT  47.699 0.096 48.233 0.12 ;
     RECT  47.153 44.928 48.265 45.72 ;
     RECT  48.197 32.448 48.269 32.856 ;
     RECT  48.085 49.536 48.269 50.376 ;
     RECT  47.833 24.624 48.277 24.648 ;
     RECT  48.121 26.208 48.277 26.232 ;
     RECT  47.411 1.728 48.305 1.8 ;
     RECT  48.229 11.952 48.305 14.232 ;
     RECT  48.125 41.136 48.305 42.6 ;
     RECT  48.269 49.536 48.337 49.608 ;
     RECT  48.277 24.48 48.364 26.232 ;
     RECT  48.305 11.952 48.373 13.032 ;
     RECT  47.693 20.112 48.373 20.136 ;
     RECT  48.305 1.728 48.377 1.752 ;
     RECT  48.364 24.48 48.377 24.648 ;
     RECT  47.261 51.648 48.377 52.44 ;
     RECT  48.373 19.872 48.467 20.136 ;
     RECT  48.269 32.448 48.485 32.712 ;
     RECT  48.364 26.208 48.517 26.232 ;
     RECT  48.377 51.648 48.517 51.912 ;
     RECT  48.467 20.112 48.521 20.136 ;
     RECT  48.085 22.464 48.593 22.824 ;
     RECT  48.377 24.624 48.593 24.648 ;
     RECT  47.836 28.272 48.665 30.072 ;
     RECT  48.053 34.656 48.697 37.368 ;
     RECT  47.549 3.552 48.733 8.76 ;
     RECT  48.373 11.808 48.773 13.032 ;
     RECT  48.083 46.848 48.809 47.304 ;
     RECT  48.337 48.48 48.809 49.608 ;
     RECT  48.805 53.808 48.841 53.832 ;
     RECT  47.833 18.192 48.881 18.84 ;
     RECT  47.693 21.216 48.881 21.24 ;
     RECT  47.333 15.36 48.949 17.064 ;
     RECT  48.881 18.192 48.949 18.216 ;
     RECT  48.733 3.552 48.985 9.528 ;
     RECT  48.665 28.752 48.989 30.072 ;
     RECT  48.469 31.344 48.989 31.368 ;
     RECT  48.697 34.464 48.989 37.368 ;
     RECT  48.841 53.04 48.995 53.832 ;
     RECT  48.949 15.36 49.025 18.216 ;
     RECT  48.265 44.88 49.093 45.72 ;
     RECT  48.773 11.952 49.097 13.032 ;
     RECT  49.045 10.704 49.132 10.728 ;
     RECT  48.989 36 49.133 37.368 ;
     RECT  48.809 48.48 49.205 49.56 ;
     RECT  47.941 43.872 49.237 43.896 ;
     RECT  48.517 51.216 49.241 51.912 ;
     RECT  49.205 49.536 49.283 49.56 ;
     RECT  49.097 11.952 49.313 12.552 ;
     RECT  48.995 53.04 49.313 53.736 ;
     RECT  49.025 15.36 49.34 17.832 ;
     RECT  48.265 38.736 49.345 38.76 ;
     RECT  49.34 15.312 49.349 17.832 ;
     RECT  49.241 51.312 49.381 51.912 ;
     RECT  49.313 53.04 49.381 53.64 ;
     RECT  49.237 43.824 49.453 43.896 ;
     RECT  49.093 44.88 49.453 46.104 ;
     RECT  48.989 28.848 49.529 30.072 ;
     RECT  48.809 47.28 49.553 47.304 ;
     RECT  49.529 29.616 49.565 30.072 ;
     RECT  48.593 22.464 49.573 22.776 ;
     RECT  48.517 26.208 49.58 27.096 ;
     RECT  48.305 41.76 49.597 42.6 ;
     RECT  49.453 43.824 49.597 46.104 ;
     RECT  49.597 41.568 49.601 46.104 ;
     RECT  49.573 21.888 49.619 23.304 ;
     RECT  49.345 38.736 49.628 38.904 ;
     RECT  48.841 39.888 49.628 39.912 ;
     RECT  49.601 41.568 49.633 41.592 ;
     RECT  49.553 47.28 49.66 48.456 ;
     RECT  49.58 25.296 49.667 27.096 ;
     RECT  48.305 14.208 49.705 14.232 ;
     RECT  49.349 15.312 49.705 16.536 ;
     RECT  49.628 38.736 49.709 39.912 ;
     RECT  49.633 41.472 49.715 41.592 ;
     RECT  49.601 42.576 49.715 46.104 ;
     RECT  48.985 3.456 49.745 9.528 ;
     RECT  49.705 14.208 49.745 16.536 ;
     RECT  49.619 23.28 49.813 23.304 ;
     RECT  48.485 32.448 49.849 32.472 ;
     RECT  49.813 23.28 49.853 23.4 ;
     RECT  49.745 14.496 49.889 16.536 ;
     RECT  49.853 23.376 49.916 23.4 ;
     RECT  49.709 38.736 49.916 39.72 ;
     RECT  49.849 32.448 49.921 33.048 ;
     RECT  49.715 42.624 49.993 46.104 ;
     RECT  49.66 47.28 49.993 47.688 ;
     RECT  49.916 38.4 50.003 39.72 ;
     RECT  49.993 42.624 50.033 47.688 ;
     RECT  49.957 50.16 50.041 50.184 ;
     RECT  48.989 34.464 50.129 34.824 ;
     RECT  49.133 36.144 50.129 37.368 ;
     RECT  49.921 32.304 50.137 33.048 ;
     RECT  50.129 34.464 50.137 37.368 ;
     RECT  50.137 32.304 50.149 37.368 ;
     RECT  50.003 38.4 50.149 38.424 ;
     RECT  49.453 19.392 50.245 19.416 ;
     RECT  49.619 21.888 50.245 21.912 ;
     RECT  49.381 51.312 50.341 53.64 ;
     RECT  49.916 23.376 50.353 24.12 ;
     RECT  49.349 17.808 50.389 17.832 ;
     RECT  50.245 18.864 50.389 19.416 ;
     RECT  50.101 31.152 50.569 31.176 ;
     RECT  50.149 32.304 50.569 38.424 ;
     RECT  50.389 17.808 50.629 19.416 ;
     RECT  50.245 21.12 50.629 21.912 ;
     RECT  50.341 51.312 50.645 53.88 ;
     RECT  50.645 51.312 50.723 53.832 ;
     RECT  50.348 48.72 50.821 49.032 ;
     RECT  50.723 51.312 50.849 53.016 ;
     RECT  49.313 11.952 50.869 11.976 ;
     RECT  50.461 13.104 50.869 13.128 ;
     RECT  49.667 25.728 50.893 27.096 ;
     RECT  49.885 2.832 51.008 2.856 ;
     RECT  49.745 3.84 51.008 9.528 ;
     RECT  50.869 11.952 51.008 13.128 ;
     RECT  49.889 14.496 51.008 14.52 ;
     RECT  49.889 16.224 51.008 16.536 ;
     RECT  50.629 17.616 51.008 21.912 ;
     RECT  50.353 23.376 51.008 24.552 ;
     RECT  50.893 25.728 51.008 27.624 ;
     RECT  49.565 29.616 51.008 29.688 ;
     RECT  50.569 31.152 51.008 38.424 ;
     RECT  50.003 39.6 51.008 39.72 ;
     RECT  49.715 41.472 51.008 41.496 ;
     RECT  50.033 42.624 51.008 47.4 ;
     RECT  50.821 48.72 51.008 49.944 ;
     RECT  50.849 51.264 51.008 53.016 ;
     RECT  51.008 2.148 51.112 53.016 ;
     RECT  51.112 2.418 51.304 53.016 ;
     RECT  51.304 35.664 51.329 38.424 ;
     RECT  51.304 2.832 51.365 9.24 ;
     RECT  51.304 13.008 51.365 13.128 ;
     RECT  51.304 23.376 51.401 23.64 ;
     RECT  51.304 24.864 51.401 26.52 ;
     RECT  51.304 51.312 51.473 53.016 ;
     RECT  51.304 32.592 51.581 33.096 ;
     RECT  51.304 14.256 51.617 15.72 ;
     RECT  51.581 32.592 51.617 32.616 ;
     RECT  51.304 42.144 51.617 49.608 ;
     RECT  51.473 52.944 51.685 53.016 ;
     RECT  51.304 39.6 51.689 39.912 ;
     RECT  51.685 52.944 51.731 53.88 ;
     RECT  51.473 51.312 51.761 51.96 ;
     RECT  51.304 20.208 51.797 21.528 ;
     RECT  51.731 53.856 51.827 53.88 ;
     RECT  51.365 3.6 51.869 9.24 ;
     RECT  51.304 18.24 51.869 19.128 ;
     RECT  51.761 51.312 51.869 51.816 ;
     RECT  51.401 26.112 51.875 26.52 ;
     RECT  51.401 24.864 51.916 24.888 ;
     RECT  51.617 43.152 51.923 49.608 ;
     RECT  51.923 43.152 51.977 48.504 ;
     RECT  51.304 29.616 52.265 31.176 ;
     RECT  51.329 35.664 52.357 38.184 ;
     RECT  51.923 49.584 52.357 49.608 ;
     RECT  51.797 20.208 52.373 20.328 ;
     RECT  51.304 27.6 52.373 27.96 ;
     RECT  51.869 3.6 52.405 9 ;
     RECT  52.405 3.408 52.489 9 ;
     RECT  52.489 4.128 52.553 9 ;
     RECT  52.373 27.936 52.553 27.96 ;
     RECT  51.617 14.256 52.589 14.28 ;
     RECT  51.401 23.376 52.621 23.592 ;
     RECT  51.617 15.696 52.652 15.72 ;
     RECT  52.652 15.024 52.693 15.72 ;
     RECT  52.357 35.664 52.693 38.808 ;
     RECT  52.693 15.024 52.739 16.536 ;
     RECT  52.265 30.816 52.835 31.176 ;
     RECT  52.693 34.944 52.873 38.808 ;
     RECT  51.689 39.888 52.873 39.912 ;
     RECT  52.789 32.16 52.877 33.288 ;
     RECT  52.621 22.752 52.909 23.592 ;
     RECT  52.265 29.616 52.909 29.688 ;
     RECT  51.869 18.24 52.913 18.792 ;
     RECT  51.304 11.184 52.981 11.448 ;
     RECT  52.693 53.04 52.985 53.064 ;
     RECT  52.739 16.512 53.017 16.536 ;
     RECT  52.357 49.584 53.053 50.184 ;
     RECT  51.869 51.312 53.053 51.384 ;
     RECT  52.873 34.944 53.057 39.912 ;
     RECT  52.909 22.752 53.093 24.504 ;
     RECT  52.553 4.128 53.129 8.376 ;
     RECT  52.909 29.088 53.233 29.688 ;
     RECT  51.617 42.144 53.269 42.168 ;
     RECT  51.977 43.152 53.269 48.456 ;
     RECT  53.269 42.144 53.305 48.456 ;
     RECT  53.305 42.144 53.309 48.552 ;
     RECT  53.233 28.992 53.341 29.688 ;
     RECT  52.373 20.208 53.365 20.232 ;
     RECT  53.365 20.16 53.452 20.232 ;
     RECT  53.161 53.856 53.459 53.928 ;
     RECT  51.365 13.008 53.485 13.032 ;
     RECT  53.485 13.008 53.525 13.128 ;
     RECT  53.341 28.992 53.557 30.216 ;
     RECT  52.981 10.848 53.777 11.448 ;
     RECT  53.053 49.584 53.845 51.384 ;
     RECT  52.913 18.24 53.881 18.264 ;
     RECT  52.877 32.304 53.885 32.472 ;
     RECT  53.629 33.792 54.025 33.816 ;
     RECT  53.557 28.8 54.029 30.216 ;
     RECT  53.309 42.528 54.061 48.552 ;
     RECT  53.885 32.448 54.065 32.472 ;
     RECT  53.459 53.904 54.083 53.928 ;
     RECT  51.797 21.504 54.101 21.528 ;
     RECT  54.029 28.8 54.253 29.112 ;
     RECT  53.017 16.512 54.277 16.632 ;
     RECT  53.057 35.664 54.281 39.912 ;
     RECT  54.181 27.744 54.317 27.768 ;
     RECT  54.281 35.664 54.317 38.856 ;
     RECT  54.085 41.232 54.349 41.256 ;
     RECT  54.061 42.528 54.349 48.6 ;
     RECT  53.845 49.584 54.389 51.72 ;
     RECT  54.281 39.888 54.46 39.912 ;
     RECT  53.093 22.752 54.493 23.928 ;
     RECT  54.029 30.192 54.533 30.216 ;
     RECT  54.349 41.232 54.533 48.6 ;
     RECT  53.525 13.104 54.565 13.128 ;
     RECT  54.025 33.6 54.565 33.816 ;
     RECT  54.389 50.16 54.569 51.72 ;
     RECT  53.129 4.128 54.601 4.152 ;
     RECT  53.129 5.232 54.601 8.376 ;
     RECT  53.452 20.208 54.605 20.232 ;
     RECT  54.493 22.752 54.605 24.888 ;
     RECT  54.565 33.6 54.609 33.864 ;
     RECT  54.253 28.8 54.673 28.824 ;
     RECT  54.569 50.16 54.677 51.384 ;
     RECT  53.881 18.24 54.709 18.936 ;
     RECT  54.533 41.76 54.749 48.6 ;
     RECT  54.277 16.512 54.757 16.968 ;
     RECT  54.709 18.24 54.757 19.512 ;
     RECT  53.777 11.136 54.781 11.448 ;
     RECT  54.565 12.48 54.781 13.128 ;
     RECT  54.781 11.136 54.785 13.128 ;
     RECT  54.421 9.648 54.817 9.672 ;
     RECT  54.785 11.136 54.817 12.552 ;
     RECT  54.757 16.512 54.892 19.512 ;
     RECT  54.745 22.464 54.929 22.488 ;
     RECT  54.421 14.784 54.956 15.192 ;
     RECT  54.601 4.128 54.965 8.376 ;
     RECT  54.609 33.6 54.965 34.68 ;
     RECT  54.317 35.664 54.965 38.808 ;
     RECT  54.817 9.648 54.995 12.552 ;
     RECT  54.965 4.128 55.037 7.896 ;
     RECT  54.956 14.064 55.043 15.192 ;
     RECT  54.749 43.008 55.069 48.6 ;
     RECT  54.892 16.512 55.145 17.112 ;
     RECT  55.037 4.128 55.181 4.44 ;
     RECT  54.965 33.84 55.181 34.68 ;
     RECT  55.181 4.128 55.185 4.152 ;
     RECT  55.069 43.008 55.253 48.744 ;
     RECT  54.349 2.832 55.283 2.856 ;
     RECT  54.892 18.24 55.283 19.512 ;
     RECT  55.185 3.936 55.289 4.152 ;
     RECT  54.995 10.464 55.289 12.552 ;
     RECT  55.181 34.656 55.357 34.68 ;
     RECT  54.965 35.664 55.357 36.216 ;
     RECT  55.357 34.656 55.361 36.216 ;
     RECT  55.361 34.656 55.397 36.072 ;
     RECT  55.145 16.944 55.433 17.112 ;
     RECT  55.033 20.976 55.465 21 ;
     RECT  51.875 26.208 55.465 26.232 ;
     RECT  54.749 41.76 55.532 41.784 ;
     RECT  54.605 23.568 55.537 24.888 ;
     RECT  55.253 43.152 55.645 48.744 ;
     RECT  55.537 23.568 55.681 25.128 ;
     RECT  55.465 26.208 55.681 26.328 ;
     RECT  54.677 50.16 55.789 51.336 ;
     RECT  55.465 20.976 55.969 21.432 ;
     RECT  55.289 10.464 56.041 11.448 ;
     RECT  55.043 14.448 56.041 15.192 ;
     RECT  55.681 23.568 56.149 26.328 ;
     RECT  54.673 28.032 56.149 28.824 ;
     RECT  55.037 5.664 56.204 7.896 ;
     RECT  55.753 9.216 56.204 9.288 ;
     RECT  56.041 10.368 56.293 11.448 ;
     RECT  55.289 12.48 56.293 12.552 ;
     RECT  55.283 18.768 56.293 19.512 ;
     RECT  55.969 20.544 56.293 21.432 ;
     RECT  56.293 18.768 56.329 21.432 ;
     RECT  55.289 3.936 56.408 3.96 ;
     RECT  56.204 5.664 56.408 9.288 ;
     RECT  56.293 10.368 56.408 12.552 ;
     RECT  56.041 13.632 56.408 15.192 ;
     RECT  55.433 17.088 56.408 17.112 ;
     RECT  56.329 18.768 56.408 21.528 ;
     RECT  56.149 22.752 56.408 26.328 ;
     RECT  56.149 28.032 56.408 29.064 ;
     RECT  55.105 31.392 56.408 31.416 ;
     RECT  55.397 34.704 56.408 36.072 ;
     RECT  54.965 37.296 56.408 38.808 ;
     RECT  55.573 39.888 56.408 39.912 ;
     RECT  55.532 41.04 56.408 41.784 ;
     RECT  55.645 43.152 56.408 49.032 ;
     RECT  55.789 50.16 56.408 51.48 ;
     RECT  56.408 2.148 56.512 51.852 ;
     RECT  56.512 2.418 56.704 51.852 ;
     RECT  56.704 43.728 56.729 44.424 ;
     RECT  56.704 45.552 56.833 51.852 ;
     RECT  56.833 45.552 56.867 52.488 ;
     RECT  56.704 27.888 56.963 29.64 ;
     RECT  56.704 9.264 57.059 9.288 ;
     RECT  56.704 15.84 57.097 17.112 ;
     RECT  56.704 12 57.125 12.072 ;
     RECT  56.867 50.16 57.125 52.488 ;
     RECT  56.704 20.976 57.197 22.248 ;
     RECT  56.729 43.728 57.197 44.28 ;
     RECT  57.125 50.16 57.277 50.184 ;
     RECT  57.125 51.312 57.305 52.488 ;
     RECT  57.305 52.464 57.341 52.488 ;
     RECT  56.704 33.6 57.377 39.624 ;
     RECT  56.704 25.632 57.395 26.76 ;
     RECT  57.197 21.504 57.485 22.248 ;
     RECT  57.197 43.728 57.557 44.136 ;
     RECT  57.305 51.312 57.565 51.336 ;
     RECT  57.557 43.824 57.593 44.136 ;
     RECT  56.704 30.672 57.629 31.944 ;
     RECT  56.704 23.568 57.635 24.36 ;
     RECT  56.704 3.936 57.665 4.296 ;
     RECT  57.377 39.6 57.665 39.624 ;
     RECT  57.377 33.6 57.737 38.232 ;
     RECT  57.737 33.6 57.773 37.848 ;
     RECT  56.704 41.04 57.773 42.6 ;
     RECT  56.704 18.384 57.805 18.792 ;
     RECT  57.773 41.04 57.805 41.064 ;
     RECT  56.704 13.152 57.841 13.224 ;
     RECT  56.704 14.4 57.841 14.76 ;
     RECT  57.805 40.464 57.845 41.064 ;
     RECT  56.867 45.552 57.845 48.792 ;
     RECT  56.704 10.272 57.877 10.392 ;
     RECT  57.845 47.808 57.877 48.792 ;
     RECT  56.704 6 57.985 7.896 ;
     RECT  57.877 9.552 57.989 10.392 ;
     RECT  57.773 33.6 57.989 35.64 ;
     RECT  57.989 10.272 58.021 10.392 ;
     RECT  57.841 13.152 58.021 14.76 ;
     RECT  56.963 29.616 58.021 29.64 ;
     RECT  58.021 29.184 58.057 29.64 ;
     RECT  58.021 13.056 58.117 14.76 ;
     RECT  57.097 15.84 58.117 16.536 ;
     RECT  57.989 35.328 58.133 35.64 ;
     RECT  58.117 13.056 58.163 16.584 ;
     RECT  57.845 45.552 58.165 46.392 ;
     RECT  57.877 47.808 58.169 49.224 ;
     RECT  57.125 12.048 58.201 12.072 ;
     RECT  58.163 13.056 58.201 15.384 ;
     RECT  58.163 16.56 58.204 16.584 ;
     RECT  58.165 45.12 58.205 46.392 ;
     RECT  58.169 47.808 58.205 48.504 ;
     RECT  57.589 0.096 58.309 0.12 ;
     RECT  57.395 25.632 58.313 25.656 ;
     RECT  57.629 30.672 58.313 31.8 ;
     RECT  58.313 30.96 58.421 31.8 ;
     RECT  57.773 36.768 58.421 37.848 ;
     RECT  58.093 9.12 58.493 9.144 ;
     RECT  58.021 10.272 58.493 10.872 ;
     RECT  57.985 5.328 58.556 7.896 ;
     RECT  57.805 18.144 58.633 18.792 ;
     RECT  58.633 17.04 58.637 18.792 ;
     RECT  58.489 24.864 58.637 25.128 ;
     RECT  57.395 26.736 58.637 26.76 ;
     RECT  58.556 5.328 58.643 8.904 ;
     RECT  57.665 4.272 58.669 4.296 ;
     RECT  57.773 42.144 58.709 42.168 ;
     RECT  58.489 2.256 58.777 2.28 ;
     RECT  57.989 33.6 58.781 33.624 ;
     RECT  58.669 3.84 58.813 4.296 ;
     RECT  58.643 5.328 58.813 6.84 ;
     RECT  57.485 22.224 58.844 22.248 ;
     RECT  58.813 3.84 58.853 6.84 ;
     RECT  58.201 12.048 58.853 15.384 ;
     RECT  58.777 1.824 58.885 2.28 ;
     RECT  57.593 43.824 58.885 43.896 ;
     RECT  58.205 45.12 58.885 45.144 ;
     RECT  58.844 22.128 58.931 22.248 ;
     RECT  58.885 43.824 58.957 45.144 ;
     RECT  58.669 51.648 58.957 51.672 ;
     RECT  58.637 17.04 58.969 17.688 ;
     RECT  58.931 22.224 58.981 22.248 ;
     RECT  57.635 23.568 58.981 23.592 ;
     RECT  58.309 0.096 58.993 0.6 ;
     RECT  58.885 1.728 58.993 2.28 ;
     RECT  58.853 12.192 58.997 15.384 ;
     RECT  58.957 51.36 58.997 51.672 ;
     RECT  58.957 43.392 59.021 45.144 ;
     RECT  58.981 22.224 59.027 23.592 ;
     RECT  57.845 40.464 59.069 40.488 ;
     RECT  58.205 48.48 59.141 48.504 ;
     RECT  58.205 46.368 59.177 46.392 ;
     RECT  58.493 10.848 59.219 10.872 ;
     RECT  58.133 35.568 59.245 35.64 ;
     RECT  58.421 36.768 59.245 37.032 ;
     RECT  58.853 3.936 59.249 6.84 ;
     RECT  58.643 8.496 59.26 8.904 ;
     RECT  59.249 6 59.267 6.84 ;
     RECT  59.18 34.032 59.267 34.056 ;
     RECT  59.245 35.568 59.267 37.032 ;
     RECT  59.26 8.496 59.293 8.568 ;
     RECT  59.021 42.72 59.321 45.144 ;
     RECT  58.993 0.096 59.329 2.28 ;
     RECT  58.421 30.96 59.357 30.984 ;
     RECT  59.321 42.72 59.357 44.28 ;
     RECT  59.267 35.568 59.389 36.792 ;
     RECT  59.389 35.376 59.393 36.792 ;
     RECT  59.393 35.376 59.533 36.504 ;
     RECT  59.329 0.528 59.603 2.28 ;
     RECT  59.357 42.72 59.609 42.744 ;
     RECT  58.057 28.992 59.651 29.64 ;
     RECT  59.533 30.912 59.677 30.936 ;
     RECT  59.027 22.752 59.708 23.592 ;
     RECT  58.969 17.04 59.717 17.208 ;
     RECT  59.717 17.04 59.753 17.064 ;
     RECT  59.708 22.752 59.789 24.072 ;
     RECT  59.789 24.048 59.795 24.072 ;
     RECT  59.708 26.256 59.795 26.28 ;
     RECT  58.633 27.984 59.843 28.008 ;
     RECT  59.249 3.936 59.897 4.92 ;
     RECT  59.785 9.696 59.897 9.72 ;
     RECT  58.997 12.192 59.897 13.704 ;
     RECT  59.821 34.08 59.921 34.104 ;
     RECT  59.533 35.136 59.921 36.504 ;
     RECT  59.677 30.144 59.933 30.936 ;
     RECT  58.637 18.768 60.001 18.792 ;
     RECT  58.885 21.12 60.005 21.144 ;
     RECT  59.921 34.08 60.005 36.504 ;
     RECT  59.357 43.824 60.005 44.28 ;
     RECT  59.651 28.992 60.145 29.016 ;
     RECT  60.005 35.232 60.149 36.504 ;
     RECT  59.267 6.24 60.289 6.84 ;
     RECT  60.181 45.552 60.289 45.576 ;
     RECT  60.001 18.192 60.365 18.792 ;
     RECT  59.789 22.752 60.397 22.824 ;
     RECT  60.289 44.64 60.401 45.576 ;
     RECT  60.289 6.24 60.405 7.416 ;
     RECT  59.293 8.496 60.405 8.52 ;
     RECT  60.401 45.552 60.419 45.576 ;
     RECT  59.353 32.736 60.428 32.76 ;
     RECT  60.005 34.08 60.428 34.104 ;
     RECT  59.461 47.28 60.437 47.304 ;
     RECT  59.603 0.576 60.467 2.28 ;
     RECT  60.428 32.736 60.469 34.104 ;
     RECT  56.704 19.872 60.473 19.896 ;
     RECT  60.405 6.24 60.509 8.52 ;
     RECT  60.397 22.176 60.509 22.824 ;
     RECT  60.145 28.944 60.509 29.016 ;
     RECT  60.469 31.92 60.515 34.104 ;
     RECT  58.637 25.104 60.541 25.128 ;
     RECT  58.997 51.36 60.565 51.384 ;
     RECT  60.565 50.688 60.611 51.384 ;
     RECT  60.611 50.688 60.652 50.712 ;
     RECT  59.897 4.896 60.653 4.92 ;
     RECT  60.509 6.24 60.689 7.992 ;
     RECT  60.467 1.728 60.755 2.28 ;
     RECT  60.689 6.24 60.761 6.264 ;
     RECT  59.857 49.536 60.764 49.56 ;
     RECT  59.933 30.432 60.833 30.936 ;
     RECT  59.897 12.864 60.937 13.656 ;
     RECT  58.997 15.36 60.937 15.384 ;
     RECT  60.433 16.512 60.949 16.536 ;
     RECT  60.509 22.176 60.973 22.2 ;
     RECT  60.541 25.104 61.004 25.272 ;
     RECT  60.577 10.992 61.045 11.016 ;
     RECT  60.365 18.768 61.148 18.792 ;
     RECT  61.148 18.768 61.189 18.888 ;
     RECT  60.613 0.096 61.265 0.216 ;
     RECT  61.045 10.272 61.285 11.016 ;
     RECT  61.265 0.144 61.337 0.216 ;
     RECT  60.755 1.728 61.409 1.8 ;
     RECT  61.337 0.144 61.481 0.168 ;
     RECT  60.973 2.88 61.808 2.904 ;
     RECT  60.689 7.392 61.808 7.992 ;
     RECT  61.285 9.648 61.808 11.016 ;
     RECT  60.937 12.864 61.808 15.384 ;
     RECT  60.949 16.512 61.808 17.064 ;
     RECT  61.189 18.768 61.808 19.512 ;
     RECT  60.973 21.552 61.808 22.2 ;
     RECT  60.829 23.52 61.808 23.544 ;
     RECT  61.004 25.104 61.808 25.704 ;
     RECT  60.509 28.992 61.808 29.016 ;
     RECT  60.833 30.432 61.808 30.456 ;
     RECT  60.515 31.92 61.808 31.944 ;
     RECT  60.515 33.504 61.808 34.104 ;
     RECT  60.149 35.328 61.808 36.504 ;
     RECT  60.764 48.816 61.808 49.56 ;
     RECT  61.808 2.148 61.912 51.852 ;
     RECT  61.912 2.418 62.104 51.582 ;
    LAYER M5 ;
     RECT  16.08 0.016 19.08 0.085 ;
     RECT  45.264 0.016 48.264 0.131 ;
     RECT  32.208 0.016 35.208 0.517 ;
     RECT  36.24 0.037 36.888 0.517 ;
     RECT  16.08 0.085 19.224 0.563 ;
     RECT  9.936 0.016 14.76 0.611 ;
     RECT  45.36 0.131 48.264 0.611 ;
     RECT  58.32 0.016 61.32 0.611 ;
     RECT  32.208 0.517 36.888 1.715 ;
     RECT  10.128 0.611 14.76 1.763 ;
     RECT  45.456 0.611 48.264 1.763 ;
     RECT  10.224 1.763 14.76 1.811 ;
     RECT  45.6 1.763 48.264 1.811 ;
     RECT  58.608 0.611 61.32 1.811 ;
     RECT  39.504 2.053 39.528 2.137 ;
     RECT  2.4 2.137 2.52 2.151 ;
     RECT  7.8 2.137 7.92 2.151 ;
     RECT  24 2.137 24.12 2.151 ;
     RECT  29.4 2.137 29.52 2.151 ;
     RECT  39.504 2.137 40.32 2.151 ;
     RECT  51 2.137 51.12 2.151 ;
     RECT  56.4 2.137 56.52 2.151 ;
     RECT  61.8 2.137 61.92 2.151 ;
     RECT  38.496 0.037 38.52 2.197 ;
     RECT  39.504 2.151 40.512 2.197 ;
     RECT  16.176 0.563 19.224 2.245 ;
     RECT  29.4 2.151 29.712 2.245 ;
     RECT  10.224 1.811 14.184 2.291 ;
     RECT  32.976 1.715 36.888 2.291 ;
     RECT  45.6 1.811 47.4 2.291 ;
     RECT  58.608 1.811 60.744 2.291 ;
     RECT  34.32 2.291 36.888 2.339 ;
     RECT  45.6 2.291 46.44 2.339 ;
     RECT  34.656 2.339 36.888 2.725 ;
     RECT  38.496 2.197 40.512 2.725 ;
     RECT  10.896 2.291 14.184 2.821 ;
     RECT  10.896 2.821 14.856 3.539 ;
     RECT  16.128 2.245 19.224 3.925 ;
     RECT  45.6 2.339 46.104 3.925 ;
     RECT  55.248 2.821 55.272 3.971 ;
     RECT  10.896 3.539 14.184 4.019 ;
     RECT  26.784 3.013 26.808 4.019 ;
     RECT  16.128 3.925 19.512 4.117 ;
     RECT  34.656 2.725 40.512 4.501 ;
     RECT  28.56 2.245 29.712 4.547 ;
     RECT  11.376 4.019 14.184 4.595 ;
     RECT  59.184 2.291 60.264 4.595 ;
     RECT  34.416 4.501 40.512 4.691 ;
     RECT  16.128 4.117 20.184 4.693 ;
     RECT  4.416 4.501 4.44 5.171 ;
     RECT  44.88 3.925 46.728 5.171 ;
     RECT  15.264 4.693 20.184 5.219 ;
     RECT  11.904 4.595 14.184 5.221 ;
     RECT  53.856 4.117 54.792 5.221 ;
     RECT  53.472 5.221 54.792 5.267 ;
     RECT  49.968 5.173 49.992 5.459 ;
     RECT  7.8 2.151 8.112 5.701 ;
     RECT  52.416 3.397 52.44 5.747 ;
     RECT  11.904 5.221 14.712 5.891 ;
     RECT  11.904 5.891 13.512 5.987 ;
     RECT  53.472 5.267 53.88 5.987 ;
     RECT  31.968 5.365 31.992 5.989 ;
     RECT  51 2.151 51.312 5.989 ;
     RECT  31.728 5.989 31.992 6.037 ;
     RECT  22.56 2.821 22.584 6.083 ;
     RECT  59.232 5.989 59.256 6.229 ;
     RECT  10.416 5.173 10.44 6.275 ;
     RECT  60.24 4.595 60.264 6.323 ;
     RECT  38.304 4.691 40.512 6.371 ;
     RECT  34.416 4.691 36.888 6.469 ;
     RECT  34.416 6.469 37.176 6.565 ;
     RECT  16.128 5.219 20.184 6.661 ;
     RECT  31.632 6.037 31.992 6.709 ;
     RECT  33.456 6.565 37.176 6.709 ;
     RECT  7.8 5.701 9.096 6.755 ;
     RECT  42.528 2.869 42.552 6.803 ;
     RECT  28.752 4.547 29.712 6.805 ;
     RECT  56.4 2.151 56.712 6.805 ;
     RECT  25.68 4.501 25.704 6.899 ;
     RECT  54.912 6.277 54.936 6.899 ;
     RECT  22.512 6.133 22.536 7.139 ;
     RECT  14.688 5.891 14.712 7.187 ;
     RECT  31.632 6.709 37.176 7.187 ;
     RECT  38.976 6.371 40.512 7.381 ;
     RECT  61.8 2.151 62.112 7.381 ;
     RECT  50.112 5.989 51.312 7.429 ;
     RECT  31.632 7.187 37.032 7.475 ;
     RECT  12.48 5.987 13.512 7.523 ;
     RECT  31.632 7.475 31.992 7.621 ;
     RECT  31.44 7.621 31.992 7.667 ;
     RECT  5.664 2.821 5.688 7.861 ;
     RECT  44.88 5.171 46.392 7.907 ;
     RECT  60.432 7.381 62.112 8.003 ;
     RECT  31.44 7.667 31.848 8.099 ;
     RECT  58.608 6.229 59.256 8.195 ;
     RECT  16.128 6.661 20.52 8.339 ;
     RECT  0.288 7.717 0.312 8.341 ;
     RECT  31.44 8.099 31.608 8.435 ;
     RECT  5.664 7.861 6.312 8.483 ;
     RECT  50.112 7.429 51.864 8.485 ;
     RECT  56.4 6.805 57.096 8.485 ;
     RECT  16.128 8.339 20.136 8.579 ;
     RECT  38.976 7.381 41.016 8.579 ;
     RECT  59.184 8.195 59.256 8.579 ;
     RECT  39.312 8.579 41.016 8.627 ;
     RECT  42.384 8.485 42.408 8.627 ;
     RECT  39.312 8.627 40.512 8.723 ;
     RECT  13.104 7.523 13.512 8.771 ;
     RECT  28.176 6.805 29.712 8.773 ;
     RECT  44.88 7.907 45.912 9.013 ;
     RECT  7.8 6.755 8.112 9.061 ;
     RECT  24 2.151 24.312 9.061 ;
     RECT  44.88 9.013 46.68 9.155 ;
     RECT  56.256 8.485 57.096 9.251 ;
     RECT  22.704 8.437 22.728 9.539 ;
     RECT  50.112 8.485 52.152 9.539 ;
     RECT  0.144 8.341 0.312 9.587 ;
     RECT  10.224 8.485 10.248 9.587 ;
     RECT  5.664 8.483 5.928 9.781 ;
     RECT  18.192 8.579 20.136 9.923 ;
     RECT  5.664 9.781 6.216 10.019 ;
     RECT  27.744 8.773 29.712 10.019 ;
     RECT  31.584 8.435 31.608 10.021 ;
     RECT  30.864 10.021 31.608 10.067 ;
     RECT  24 9.061 24.552 10.115 ;
     RECT  14.832 7.813 14.856 10.549 ;
     RECT  16.128 8.579 16.632 10.549 ;
     RECT  14.832 10.549 16.632 10.595 ;
     RECT  7.8 9.061 8.856 10.645 ;
     RECT  21.024 10.309 21.048 10.739 ;
     RECT  49.056 9.493 49.08 10.739 ;
     RECT  39.456 8.723 40.512 10.789 ;
     RECT  28.032 10.019 29.712 10.835 ;
     RECT  50.88 9.539 52.152 10.837 ;
     RECT  53.856 5.987 53.88 10.837 ;
     RECT  7.8 10.645 9.624 10.883 ;
     RECT  59.184 8.579 59.208 10.883 ;
     RECT  39.456 10.789 41.064 10.979 ;
     RECT  2.4 2.151 2.712 11.173 ;
     RECT  15.264 10.595 16.632 11.173 ;
     RECT  33.456 7.475 37.032 11.219 ;
     RECT  50.88 10.837 53.88 11.219 ;
     RECT  26.448 10.885 26.472 11.267 ;
     RECT  30.864 10.067 30.888 11.459 ;
     RECT  50.88 11.219 51.72 11.459 ;
     RECT  2.4 11.173 2.808 11.891 ;
     RECT  38.064 11.221 38.088 11.939 ;
     RECT  39.456 10.979 40.512 11.941 ;
     RECT  43.536 9.637 43.56 11.941 ;
     RECT  44.88 9.155 45.912 11.941 ;
     RECT  43.2 11.941 43.56 12.035 ;
     RECT  44.88 11.941 46.008 12.035 ;
     RECT  54.96 9.637 54.984 12.179 ;
     RECT  12 10.501 12.024 12.323 ;
     RECT  31.92 11.029 31.944 12.563 ;
     RECT  48.432 11.941 48.456 13.043 ;
     RECT  52.992 11.219 53.88 13.043 ;
     RECT  41.568 12.517 41.592 13.091 ;
     RECT  44.976 12.035 46.008 13.427 ;
     RECT  15.264 11.173 16.872 13.523 ;
     RECT  59.712 12.517 59.736 13.571 ;
     RECT  30.816 11.509 30.84 13.667 ;
     RECT  55.008 12.517 55.032 14.099 ;
     RECT  13.2 8.771 13.512 14.197 ;
     RECT  32.208 13.045 32.232 14.291 ;
     RECT  24 10.115 24.408 14.435 ;
     RECT  56.4 9.251 57.096 14.437 ;
     RECT  55.776 14.437 57.096 14.627 ;
     RECT  0.288 9.587 0.312 14.773 ;
     RECT  53.856 13.043 53.88 14.773 ;
     RECT  0.192 14.773 0.312 14.819 ;
     RECT  13.104 14.197 13.512 14.819 ;
     RECT  39.168 11.941 40.512 15.061 ;
     RECT  53.856 14.773 54.456 15.157 ;
     RECT  18.192 9.923 19.992 15.205 ;
     RECT  43.2 12.035 43.224 15.251 ;
     RECT  44.976 13.427 45.912 15.301 ;
     RECT  33.456 11.219 33.48 15.349 ;
     RECT  44.928 15.301 45.912 15.349 ;
     RECT  47.088 11.941 47.112 15.349 ;
     RECT  15.264 13.523 16.152 15.397 ;
     RECT  15.072 15.397 16.152 15.443 ;
     RECT  13.2 14.819 13.512 16.117 ;
     RECT  49.392 14.197 49.416 16.259 ;
     RECT  15.072 15.443 15.096 16.405 ;
     RECT  16.128 15.443 16.152 16.405 ;
     RECT  28.512 10.835 29.712 16.501 ;
     RECT  33.072 15.349 33.48 16.501 ;
     RECT  34.8 11.219 37.032 16.501 ;
     RECT  53.856 15.157 54.696 16.501 ;
     RECT  61.248 8.003 62.112 16.501 ;
     RECT  50.88 11.459 51.312 16.547 ;
     RECT  52.704 15.013 52.728 16.547 ;
     RECT  13.2 16.117 13.608 16.595 ;
     RECT  39.168 15.061 41.016 16.595 ;
     RECT  44.928 15.349 47.256 16.595 ;
     RECT  58.128 13.621 58.152 16.595 ;
     RECT  44.976 16.595 47.256 16.835 ;
     RECT  17.376 15.205 19.992 16.837 ;
     RECT  28.512 16.501 30.6 17.075 ;
     RECT  33.072 16.501 37.032 17.075 ;
     RECT  39.168 16.595 40.512 17.075 ;
     RECT  60.96 16.501 62.112 17.075 ;
     RECT  15.072 16.405 16.152 17.123 ;
     RECT  17.376 16.837 20.424 17.411 ;
     RECT  53.856 16.501 54.792 17.509 ;
     RECT  24 14.435 24.312 17.605 ;
     RECT  51 16.547 51.312 17.605 ;
     RECT  58.896 17.029 58.92 17.699 ;
     RECT  49.008 17.077 49.032 17.843 ;
     RECT  44.976 16.835 45.912 18.133 ;
     RECT  28.512 17.075 29.712 18.181 ;
     RECT  53.856 17.509 54.84 18.229 ;
     RECT  7.8 10.883 8.856 18.275 ;
     RECT  21.888 17.413 21.912 18.275 ;
     RECT  18.192 17.411 20.424 18.517 ;
     RECT  27.312 16.405 27.336 18.659 ;
     RECT  33.456 17.075 37.032 18.707 ;
     RECT  50.64 17.605 51.312 18.757 ;
     RECT  53.856 18.229 55.272 18.803 ;
     RECT  28.512 18.181 30.408 18.853 ;
     RECT  61.248 17.075 62.112 18.853 ;
     RECT  50.4 18.757 51.312 18.899 ;
     RECT  28.512 18.853 30.84 19.091 ;
     RECT  30.816 19.091 30.84 19.139 ;
     RECT  15.072 17.123 15.096 19.333 ;
     RECT  53.856 18.803 54.792 19.523 ;
     RECT  61.2 18.853 62.112 19.523 ;
     RECT  28.512 19.091 29.712 19.571 ;
     RECT  47.088 16.835 47.256 19.621 ;
     RECT  56.4 14.627 57.096 19.861 ;
     RECT  48.432 18.181 48.456 19.907 ;
     RECT  53.856 19.523 53.88 20.149 ;
     RECT  43.488 16.885 43.512 20.389 ;
     RECT  44.544 18.133 45.912 20.389 ;
     RECT  34.8 18.707 37.032 20.437 ;
     RECT  24 17.605 24.552 20.579 ;
     RECT  56.304 19.861 57.096 20.579 ;
     RECT  26.16 19.765 26.184 20.867 ;
     RECT  43.488 20.389 45.912 21.013 ;
     RECT  15.072 19.333 15.384 21.109 ;
     RECT  50.64 18.899 51.312 21.109 ;
     RECT  21.696 18.709 21.72 21.155 ;
     RECT  53.376 20.149 53.88 21.539 ;
     RECT  50.256 21.109 51.312 21.877 ;
     RECT  49.584 21.877 51.312 21.923 ;
     RECT  12 21.013 12.024 21.925 ;
     RECT  13.2 16.595 13.512 21.925 ;
     RECT  24 20.579 24.312 21.925 ;
     RECT  12 21.925 13.512 21.971 ;
     RECT  17.184 21.109 17.208 21.971 ;
     RECT  34.8 20.437 37.08 21.971 ;
     RECT  47.04 19.621 47.256 21.971 ;
     RECT  58.896 21.109 58.92 22.163 ;
     RECT  15.072 21.109 15.624 22.211 ;
     RECT  39.456 17.075 40.512 22.213 ;
     RECT  12.48 21.971 13.512 22.739 ;
     RECT  53.856 21.539 53.88 22.741 ;
     RECT  56.4 20.579 57.096 22.741 ;
     RECT  58.992 22.213 59.016 22.789 ;
     RECT  58.992 22.789 59.784 23.027 ;
     RECT  39.456 22.213 40.632 23.075 ;
     RECT  43.344 21.013 45.912 23.267 ;
     RECT  49.584 21.923 49.608 23.315 ;
     RECT  50.688 21.923 51.312 23.365 ;
     RECT  43.488 23.267 45.912 23.411 ;
     RECT  43.488 23.411 44.328 23.459 ;
     RECT  24 21.925 24.504 23.557 ;
     RECT  2.4 11.891 2.712 23.701 ;
     RECT  45.6 23.411 45.912 23.845 ;
     RECT  47.088 21.971 47.256 23.845 ;
     RECT  53.712 22.741 53.88 23.939 ;
     RECT  49.968 23.365 51.864 24.131 ;
     RECT  30.72 23.125 30.744 24.227 ;
     RECT  56.16 22.741 57.096 24.325 ;
     RECT  10.992 23.317 11.016 24.371 ;
     RECT  34.8 21.971 36.84 24.373 ;
     RECT  38.16 23.365 38.184 24.373 ;
     RECT  7.8 18.275 8.112 24.469 ;
     RECT  33.456 18.707 33.48 24.469 ;
     RECT  24 23.557 24.984 24.515 ;
     RECT  34.8 24.373 38.184 24.515 ;
     RECT  36.816 24.515 38.184 24.563 ;
     RECT  50.688 24.131 51.864 24.563 ;
     RECT  2.4 23.701 3 24.611 ;
     RECT  56.16 24.325 57.624 24.661 ;
     RECT  42.048 22.741 42.072 24.803 ;
     RECT  39.456 23.075 40.512 25.045 ;
     RECT  29.4 19.571 29.712 25.093 ;
     RECT  61.248 19.523 62.112 25.093 ;
     RECT  7.8 24.469 9.096 25.237 ;
     RECT  7.68 25.237 9.096 25.283 ;
     RECT  15.072 22.211 15.096 25.475 ;
     RECT  55.344 24.661 57.624 25.667 ;
     RECT  39.312 25.045 40.512 25.715 ;
     RECT  61.056 25.093 62.112 25.715 ;
     RECT  26.928 24.133 26.952 25.717 ;
     RECT  26.832 25.717 26.952 25.859 ;
     RECT  16.656 24.805 16.68 26.243 ;
     RECT  24 24.515 24.504 26.243 ;
     RECT  29.28 25.093 29.712 26.243 ;
     RECT  33.072 24.469 33.48 26.243 ;
     RECT  48.288 24.469 48.312 26.243 ;
     RECT  49.632 25.285 49.656 26.243 ;
     RECT  55.344 25.667 57.384 26.243 ;
     RECT  59.76 23.027 59.784 26.291 ;
     RECT  7.68 25.283 8.112 26.293 ;
     RECT  51 24.563 51.864 26.531 ;
     RECT  13.2 22.739 13.512 26.629 ;
     RECT  45.6 23.845 47.256 26.819 ;
     RECT  0.192 14.819 0.216 26.915 ;
     RECT  5.904 10.019 6.216 27.301 ;
     RECT  7.632 26.293 8.112 27.301 ;
     RECT  43.488 23.459 43.512 27.301 ;
     RECT  43.488 27.301 43.944 27.347 ;
     RECT  39.456 25.715 40.512 27.733 ;
     RECT  53.856 23.939 53.88 27.733 ;
     RECT  13.2 26.629 14.232 27.877 ;
     RECT  18.192 18.517 20.472 27.877 ;
     RECT  24 26.243 24.408 27.877 ;
     RECT  26.832 27.301 26.856 27.877 ;
     RECT  13.104 27.877 14.232 28.163 ;
     RECT  29.4 26.243 29.712 28.261 ;
     RECT  18.192 27.877 20.616 28.405 ;
     RECT  13.2 28.163 14.232 28.451 ;
     RECT  24 27.877 24.456 28.453 ;
     RECT  38.784 27.733 40.512 28.453 ;
     RECT  16.032 27.205 16.056 28.595 ;
     RECT  53.856 27.733 54.216 28.789 ;
     RECT  17.232 28.405 20.616 28.979 ;
     RECT  4.992 27.301 8.112 28.981 ;
     RECT  59.808 27.973 59.832 29.027 ;
     RECT  33.456 26.243 33.48 29.029 ;
     RECT  26.112 27.877 26.856 29.075 ;
     RECT  23.424 28.453 24.456 29.123 ;
     RECT  53.568 28.789 54.216 29.123 ;
     RECT  13.2 28.451 13.944 29.365 ;
     RECT  4.56 28.981 8.112 29.411 ;
     RECT  5.088 29.411 8.112 29.459 ;
     RECT  26.832 29.075 26.856 29.507 ;
     RECT  7.632 29.459 8.112 29.509 ;
     RECT  51 26.531 51.312 29.605 ;
     RECT  53.568 29.123 53.88 29.605 ;
     RECT  47.088 26.819 47.256 29.653 ;
     RECT  52.752 29.605 53.88 29.699 ;
     RECT  22.704 29.653 22.728 29.749 ;
     RECT  34.8 24.515 35.736 29.795 ;
     RECT  17.232 28.979 20.472 30.035 ;
     RECT  47.088 29.653 47.784 30.037 ;
     RECT  36.816 24.563 37.464 30.229 ;
     RECT  38.496 28.453 41.016 30.229 ;
     RECT  12.336 29.365 13.944 30.275 ;
     RECT  29.232 28.261 29.712 30.275 ;
     RECT  7.632 29.509 8.328 30.323 ;
     RECT  31.584 27.877 31.608 30.323 ;
     RECT  36.816 30.229 41.016 30.323 ;
     RECT  47.088 30.037 48.504 30.323 ;
     RECT  43.68 27.347 43.944 30.613 ;
     RECT  42.96 30.613 43.944 30.755 ;
     RECT  39.456 30.323 41.016 30.805 ;
     RECT  5.088 29.459 6.216 30.851 ;
     RECT  52.752 29.699 52.776 30.851 ;
     RECT  59.232 29.605 59.64 30.947 ;
     RECT  22.032 29.749 22.728 30.949 ;
     RECT  21.696 30.949 22.728 30.995 ;
     RECT  50.496 29.605 51.312 31.141 ;
     RECT  39.456 30.805 41.64 31.235 ;
     RECT  2.4 24.611 2.712 31.285 ;
     RECT  43.68 30.755 43.944 31.285 ;
     RECT  39.456 31.235 41.016 31.379 ;
     RECT  48.48 30.323 48.504 31.379 ;
     RECT  13.2 30.275 13.944 31.765 ;
     RECT  33.12 29.029 33.48 31.907 ;
     RECT  61.248 25.715 62.112 31.909 ;
     RECT  34.8 29.795 35.544 32.437 ;
     RECT  36.816 30.323 37.608 32.437 ;
     RECT  45.6 26.819 45.912 32.437 ;
     RECT  47.088 30.323 47.256 32.437 ;
     RECT  50.112 31.141 51.312 32.483 ;
     RECT  31.728 31.669 31.752 32.723 ;
     RECT  2.4 31.285 2.904 32.771 ;
     RECT  21.696 30.995 22.056 32.771 ;
     RECT  5.664 30.851 6.216 32.819 ;
     RECT  16.992 32.341 17.016 33.013 ;
     RECT  33.456 31.907 33.48 33.013 ;
     RECT  16.992 33.013 17.112 33.155 ;
     RECT  60.48 31.909 62.112 33.251 ;
     RECT  52.8 31.141 52.824 33.299 ;
     RECT  39.456 31.379 40.512 33.301 ;
     RECT  34.8 32.437 37.608 33.347 ;
     RECT  61.248 33.251 62.112 33.539 ;
     RECT  39.456 33.301 40.632 33.541 ;
     RECT  24 29.123 24.456 33.589 ;
     RECT  29.28 30.275 29.712 33.683 ;
     RECT  34.8 33.347 36.84 33.683 ;
     RECT  13.2 31.765 14.52 34.163 ;
     RECT  50.256 32.483 51.312 34.165 ;
     RECT  26.976 32.917 27 34.211 ;
     RECT  16.56 33.589 16.584 34.355 ;
     RECT  18.192 30.035 20.472 34.499 ;
     RECT  2.4 32.771 2.712 34.501 ;
     RECT  43.68 31.285 44.472 34.595 ;
     RECT  34.8 33.683 35.112 34.645 ;
     RECT  36.816 33.683 36.84 34.645 ;
     RECT  53.856 29.699 53.88 34.645 ;
     RECT  55.344 26.243 57.096 34.645 ;
     RECT  24 33.589 24.648 34.741 ;
     RECT  59.232 30.947 59.256 34.741 ;
     RECT  53.856 34.645 57.096 34.787 ;
     RECT  50.16 34.165 51.312 34.789 ;
     RECT  33.264 33.013 33.48 34.883 ;
     RECT  34.8 34.645 36.84 34.883 ;
     RECT  19.968 34.499 20.472 35.027 ;
     RECT  22.032 32.771 22.056 35.077 ;
     RECT  22.032 35.077 22.2 35.123 ;
     RECT  33.264 34.883 33.432 35.269 ;
     RECT  33.072 35.269 33.432 35.315 ;
     RECT  5.904 32.819 6.216 35.317 ;
     RECT  61.8 33.539 62.112 35.317 ;
     RECT  59.232 34.741 59.976 35.411 ;
     RECT  43.68 34.595 43.896 35.507 ;
     RECT  4.176 31.861 4.2 35.653 ;
     RECT  5.328 35.317 6.216 35.653 ;
     RECT  4.176 35.653 6.216 35.699 ;
     RECT  53.856 34.787 56.808 35.699 ;
     RECT  53.856 35.699 53.88 35.843 ;
     RECT  38.928 33.541 40.632 35.845 ;
     RECT  23.184 34.741 24.648 35.893 ;
     RECT  25.728 31.189 25.752 35.893 ;
     RECT  13.2 34.163 14.328 35.939 ;
     RECT  33.072 35.315 33.096 36.131 ;
     RECT  43.872 35.507 43.896 36.227 ;
     RECT  9.36 33.541 9.384 36.229 ;
     RECT  4.512 35.699 6.216 36.275 ;
     RECT  38.928 35.845 41.592 36.373 ;
     RECT  22.176 35.123 22.2 36.469 ;
     RECT  45.6 32.437 47.256 36.469 ;
     RECT  45.6 36.469 47.352 36.515 ;
     RECT  61.296 35.317 62.112 36.515 ;
     RECT  21.312 36.469 22.2 36.517 ;
     RECT  23.184 35.893 25.752 36.517 ;
     RECT  36.816 34.883 36.84 36.563 ;
     RECT  21.312 36.517 25.752 36.659 ;
     RECT  30.768 36.325 30.792 36.755 ;
     RECT  29.4 33.683 29.712 36.757 ;
     RECT  55.344 35.699 56.808 36.757 ;
     RECT  5.328 36.275 6.216 36.803 ;
     RECT  23.04 36.659 25.752 36.947 ;
     RECT  29.136 36.757 29.712 36.995 ;
     RECT  9.36 36.229 9.528 36.997 ;
     RECT  50.064 34.789 51.312 36.997 ;
     RECT  59.232 35.411 59.256 37.043 ;
     RECT  9.36 36.997 9.576 37.091 ;
     RECT  11.664 36.133 11.688 37.091 ;
     RECT  38.544 36.373 41.592 37.091 ;
     RECT  2.4 34.501 3.096 37.187 ;
     RECT  23.04 36.947 24.456 37.331 ;
     RECT  17.088 36.997 17.112 37.333 ;
     RECT  18.192 34.499 18.912 37.333 ;
     RECT  47.088 36.515 47.352 37.619 ;
     RECT  26.736 36.469 26.76 37.667 ;
     RECT  55.344 36.757 57.768 37.859 ;
     RECT  55.344 37.859 57.48 38.003 ;
     RECT  17.088 37.333 18.912 38.195 ;
     RECT  40.08 37.091 41.592 38.387 ;
     RECT  29.28 36.995 29.712 38.435 ;
     RECT  36.528 37.045 36.552 38.437 ;
     RECT  40.08 38.387 41.208 38.483 ;
     RECT  18.192 38.195 18.912 38.531 ;
     RECT  44.4 38.149 44.424 38.723 ;
     RECT  45.6 36.515 46.008 38.723 ;
     RECT  9.552 37.091 9.576 38.725 ;
     RECT  38.544 37.091 38.568 38.725 ;
     RECT  47.088 37.619 47.256 38.771 ;
     RECT  18.6 38.531 18.912 38.773 ;
     RECT  19.968 35.027 19.992 38.773 ;
     RECT  55.344 38.003 56.712 38.773 ;
     RECT  5.904 36.803 6.216 38.819 ;
     RECT  49.968 36.997 51.312 38.869 ;
     RECT  47.088 38.771 47.112 39.011 ;
     RECT  13.2 35.939 13.704 39.059 ;
     RECT  17.088 38.195 17.112 39.443 ;
     RECT  55.056 38.773 56.712 39.589 ;
     RECT  18.6 38.773 19.992 39.635 ;
     RECT  22.848 38.197 22.872 39.731 ;
     RECT  49.68 38.869 51.312 39.731 ;
     RECT  34.8 34.883 35.112 39.829 ;
     RECT  36.528 38.437 36.888 39.829 ;
     RECT  2.4 37.187 2.712 39.877 ;
     RECT  9.552 38.725 10.248 39.877 ;
     RECT  55.056 39.589 57.528 39.877 ;
     RECT  7.632 30.323 8.112 39.923 ;
     RECT  19.968 39.635 19.992 40.019 ;
     RECT  42.912 39.877 42.936 40.165 ;
     RECT  25.728 36.947 25.752 40.405 ;
     RECT  13.2 39.059 13.608 40.453 ;
     RECT  40.2 38.483 41.208 40.549 ;
     RECT  38.208 38.725 38.568 40.595 ;
     RECT  24 37.331 24.456 40.691 ;
     RECT  18.6 39.635 18.912 40.789 ;
     RECT  29.4 38.435 29.712 40.981 ;
     RECT  54.384 39.877 57.528 41.029 ;
     RECT  34.8 39.829 36.888 41.075 ;
     RECT  54.384 41.029 57.672 41.221 ;
     RECT  13.2 40.453 13.704 41.365 ;
     RECT  5.088 40.405 5.112 41.411 ;
     RECT  12.96 41.365 13.704 41.411 ;
     RECT  50.4 39.731 51.312 41.461 ;
     RECT  49.968 41.461 51.312 41.557 ;
     RECT  29.4 40.981 30.6 41.651 ;
     RECT  22.8 40.261 22.824 41.795 ;
     RECT  42.912 40.165 43.32 41.843 ;
     RECT  43.056 41.843 43.32 41.845 ;
     RECT  17.856 40.789 18.912 41.941 ;
     RECT  12.96 41.411 13.512 42.085 ;
     RECT  9.408 39.877 10.248 42.131 ;
     RECT  54.096 41.221 57.672 42.131 ;
     RECT  49.68 41.557 51.312 42.133 ;
     RECT  52.368 38.725 52.392 42.133 ;
     RECT  38.544 40.595 38.568 42.325 ;
     RECT  39.648 40.549 41.208 42.325 ;
     RECT  17.856 41.941 19.704 42.467 ;
     RECT  25.536 40.405 25.752 42.515 ;
     RECT  34.8 41.075 35.496 42.517 ;
     RECT  36.528 41.075 36.888 42.517 ;
     RECT  27.888 41.797 27.912 42.709 ;
     RECT  29.4 41.651 29.712 42.709 ;
     RECT  38.544 42.325 41.208 42.709 ;
     RECT  2.4 39.877 3.432 42.755 ;
     RECT  18.6 42.467 19.704 42.755 ;
     RECT  34.8 42.517 36.888 42.755 ;
     RECT  49.68 42.133 52.392 42.803 ;
     RECT  6.192 38.819 6.216 43.139 ;
     RECT  47.184 43.093 47.208 43.285 ;
     RECT  15.312 41.557 15.336 43.523 ;
     RECT  27.888 42.709 29.712 43.715 ;
     RECT  49.68 42.803 51.312 43.813 ;
     RECT  59.04 42.709 59.064 43.813 ;
     RECT  58.704 43.813 59.064 43.859 ;
     RECT  21.312 36.659 21.336 43.861 ;
     RECT  38.544 42.709 41.352 43.861 ;
     RECT  43.056 41.845 43.752 43.861 ;
     RECT  54.096 42.131 57.528 43.861 ;
     RECT  58.704 43.859 58.728 43.861 ;
     RECT  10.224 42.131 10.248 44.053 ;
     RECT  11.28 43.813 11.304 44.053 ;
     RECT  25.536 42.515 25.56 44.099 ;
     RECT  10.224 44.053 11.304 44.101 ;
     RECT  12.48 42.085 13.512 44.101 ;
     RECT  2.4 42.755 2.712 44.245 ;
     RECT  20.544 43.861 21.336 44.245 ;
     RECT  20.4 44.245 21.336 44.291 ;
     RECT  9.12 42.421 9.144 44.437 ;
     RECT  45.6 38.723 45.912 44.437 ;
     RECT  52.368 42.803 52.392 44.437 ;
     RECT  20.4 44.291 20.568 44.627 ;
     RECT  33.744 43.141 33.768 44.677 ;
     RECT  34.8 42.755 35.496 44.677 ;
     RECT  54.096 43.861 58.728 44.869 ;
     RECT  2.4 44.245 3 44.915 ;
     RECT  5.184 43.861 5.208 44.915 ;
     RECT  7.8 39.923 8.112 44.965 ;
     RECT  9.12 44.437 9.24 44.965 ;
     RECT  45.024 44.437 45.912 45.013 ;
     RECT  53.472 44.869 58.728 45.155 ;
     RECT  28.464 43.715 29.712 45.205 ;
     RECT  45.024 45.013 46.056 45.299 ;
     RECT  24 40.691 24.312 45.397 ;
     RECT  38.16 43.861 41.352 45.445 ;
     RECT  7.8 44.965 9.24 45.541 ;
     RECT  10.224 44.101 13.512 45.541 ;
     RECT  33.744 44.677 35.496 45.587 ;
     RECT  49.248 43.813 51.312 45.637 ;
     RECT  52.368 44.437 52.44 45.637 ;
     RECT  25.776 45.493 26.472 45.685 ;
     RECT  47.184 43.285 47.592 45.731 ;
     RECT  49.248 45.637 52.44 45.971 ;
     RECT  25.728 45.685 26.472 46.069 ;
     RECT  27.936 45.205 29.712 46.069 ;
     RECT  5.088 44.965 5.112 46.117 ;
     RECT  37.92 45.445 41.352 46.117 ;
     RECT  42.432 43.861 43.752 46.117 ;
     RECT  31.392 43.669 31.416 46.211 ;
     RECT  23.472 45.397 24.312 46.259 ;
     RECT  20.4 44.627 20.424 46.357 ;
     RECT  45.6 45.299 46.056 46.549 ;
     RECT  47.184 45.731 47.208 46.549 ;
     RECT  25.728 46.069 29.712 46.645 ;
     RECT  25.584 46.645 29.712 46.693 ;
     RECT  34.416 45.587 35.496 46.787 ;
     RECT  37.92 46.117 43.752 46.787 ;
     RECT  4.128 46.117 5.112 46.883 ;
     RECT  7.8 45.541 13.512 46.883 ;
     RECT  36.864 42.755 36.888 46.883 ;
     RECT  5.088 46.883 5.112 47.027 ;
     RECT  12.72 46.883 13.512 47.125 ;
     RECT  52.368 45.971 52.44 47.173 ;
     RECT  53.472 45.155 58.2 47.173 ;
     RECT  7.8 46.883 11.736 47.269 ;
     RECT  20.16 46.357 20.424 47.269 ;
     RECT  49.248 45.971 51.312 47.269 ;
     RECT  52.368 47.173 58.2 47.269 ;
     RECT  19.968 47.269 20.424 47.315 ;
     RECT  31.008 46.693 31.032 47.315 ;
     RECT  60.384 45.541 60.408 47.315 ;
     RECT  15.408 46.501 15.432 47.363 ;
     RECT  7.68 47.269 11.736 47.845 ;
     RECT  23.904 46.259 24.312 47.845 ;
     RECT  25.344 46.693 29.712 47.845 ;
     RECT  33.312 47.173 33.336 47.893 ;
     RECT  34.416 46.787 35.352 47.893 ;
     RECT  45.6 46.549 47.208 47.893 ;
     RECT  48.96 47.269 58.2 47.893 ;
     RECT  38.544 46.787 43.752 47.987 ;
     RECT  18.6 42.755 18.912 47.989 ;
     RECT  19.968 47.315 20.184 48.275 ;
     RECT  7.392 47.845 11.736 48.421 ;
     RECT  12.72 47.125 13.608 48.421 ;
     RECT  33.312 47.893 35.352 48.467 ;
     RECT  38.544 47.987 43.32 48.467 ;
     RECT  18.24 47.989 18.912 48.515 ;
     RECT  19.968 48.275 19.992 48.515 ;
     RECT  45.6 47.893 58.2 48.515 ;
     RECT  23.904 47.845 29.712 48.659 ;
     RECT  34.416 48.467 35.352 48.659 ;
     RECT  7.392 48.421 13.608 48.661 ;
     RECT  61.8 36.515 62.112 48.805 ;
     RECT  3.792 48.373 3.816 49.043 ;
     RECT  38.688 48.467 43.32 49.043 ;
     RECT  33.312 48.467 33.336 49.091 ;
     RECT  45.6 48.515 57.528 49.571 ;
     RECT  60.816 48.805 62.112 49.571 ;
     RECT  7.392 48.661 14.136 49.619 ;
     RECT  7.392 49.619 11.736 50.195 ;
     RECT  39.024 49.043 43.32 50.195 ;
     RECT  49.968 49.571 57.528 50.195 ;
     RECT  12.72 49.619 14.136 50.243 ;
     RECT  15.408 48.901 15.432 50.243 ;
     RECT  37.008 48.997 37.032 50.291 ;
     RECT  18.48 48.515 18.912 50.531 ;
     RECT  24 48.659 29.712 50.579 ;
     RECT  34.416 48.659 35.208 50.677 ;
     RECT  30.72 49.861 30.744 50.723 ;
     RECT  24 50.579 27.384 50.771 ;
     RECT  45.6 49.571 48.984 50.771 ;
     RECT  25.584 50.771 27.384 50.819 ;
     RECT  28.8 50.579 29.712 50.867 ;
     RECT  50.016 50.195 57.528 51.059 ;
     RECT  13.2 50.243 14.136 51.107 ;
     RECT  13.2 51.107 13.656 51.155 ;
     RECT  47.808 50.771 48.984 51.205 ;
     RECT  50.016 51.059 54.456 51.205 ;
     RECT  4.56 50.677 4.584 51.347 ;
     RECT  7.392 50.195 11.64 51.347 ;
     RECT  20.256 50.101 20.28 51.347 ;
     RECT  21.744 50.101 21.768 51.347 ;
     RECT  39.024 50.195 43.08 51.347 ;
     RECT  55.44 51.059 57.528 51.347 ;
     RECT  7.392 51.347 9.816 51.395 ;
     RECT  25.632 50.819 27.384 51.395 ;
     RECT  60.576 50.677 60.6 51.395 ;
     RECT  10.848 51.347 10.92 51.443 ;
     RECT  47.808 51.205 54.456 51.539 ;
     RECT  34.416 50.677 35.256 51.541 ;
     RECT  34.416 51.541 35.592 51.781 ;
     RECT  34.224 51.781 35.592 51.829 ;
     RECT  45.6 50.771 46.824 51.829 ;
     RECT  47.808 51.539 54.072 51.829 ;
     RECT  2.4 44.915 2.712 51.849 ;
     RECT  7.392 51.395 9.432 51.849 ;
     RECT  13.2 51.155 13.512 51.849 ;
     RECT  18.6 50.531 18.912 51.849 ;
     RECT  29.4 50.867 29.712 51.849 ;
     RECT  56.4 51.347 56.712 51.849 ;
     RECT  61.8 49.571 62.112 51.849 ;
     RECT  2.4 51.849 2.52 51.863 ;
     RECT  7.392 51.849 7.92 51.863 ;
     RECT  13.2 51.849 13.32 51.863 ;
     RECT  18.6 51.849 18.72 51.863 ;
     RECT  24 50.771 24.552 51.863 ;
     RECT  29.4 51.849 29.52 51.863 ;
     RECT  45.6 51.829 54.072 51.863 ;
     RECT  56.4 51.849 56.52 51.863 ;
     RECT  61.8 51.849 61.92 51.863 ;
     RECT  10.848 51.443 10.872 51.875 ;
     RECT  34.128 51.829 35.592 51.877 ;
     RECT  33.744 51.877 35.592 52.309 ;
     RECT  33.264 52.309 35.592 52.405 ;
     RECT  7.392 51.863 7.416 52.499 ;
     RECT  25.632 51.395 26.424 53.075 ;
     RECT  45.744 51.863 54.072 53.075 ;
     RECT  45.744 53.075 51.816 53.845 ;
     RECT  45.648 53.845 51.816 53.891 ;
     RECT  8.928 51.849 9.432 53.939 ;
     RECT  24.528 51.863 24.552 53.939 ;
     RECT  25.632 53.075 25.8 53.939 ;
     RECT  39.216 51.347 42.408 53.939 ;
     RECT  53.232 53.075 54.072 53.939 ;
     RECT  32.592 52.405 35.592 53.968 ;
     RECT  45.648 53.891 51.72 53.968 ;
     RECT  14.808 0.016 16.032 0.132 ;
     RECT  35.256 0.037 36.24 0.132 ;
     RECT  14.76 0.132 16.08 0.563 ;
     RECT  35.208 0.132 36.24 0.517 ;
     RECT  14.76 0.563 16.176 1.811 ;
     RECT  14.184 1.811 16.176 2.245 ;
     RECT  60.744 1.811 61.32 2.137 ;
     RECT  38.52 2.053 39.504 2.197 ;
     RECT  60.744 2.137 61.8 2.291 ;
     RECT  14.184 2.245 16.128 2.821 ;
     RECT  14.856 2.821 16.128 3.539 ;
     RECT  22.584 2.821 24 6.083 ;
     RECT  55.272 2.821 56.4 3.971 ;
     RECT  51.312 3.397 52.416 5.747 ;
     RECT  14.184 3.539 16.128 4.693 ;
     RECT  10.896 4.019 11.376 4.595 ;
     RECT  52.44 4.117 53.856 5.221 ;
     RECT  4.44 4.501 5.664 5.171 ;
     RECT  24.312 4.501 25.68 6.899 ;
     RECT  10.896 4.595 11.904 5.173 ;
     RECT  59.232 4.595 60.24 5.989 ;
     RECT  36.888 4.691 38.304 6.371 ;
     RECT  14.184 4.693 15.264 5.219 ;
     RECT  10.44 5.173 11.904 5.987 ;
     RECT  49.992 5.173 51 5.459 ;
     RECT  14.184 5.219 16.128 5.221 ;
     RECT  14.712 5.221 16.128 7.187 ;
     RECT  52.44 5.221 53.472 5.747 ;
     RECT  53.88 5.267 54.792 6.277 ;
     RECT  50.112 5.459 51 5.989 ;
     RECT  9.096 5.701 10.416 6.275 ;
     RECT  13.512 5.891 14.688 7.187 ;
     RECT  59.256 5.989 60.24 6.323 ;
     RECT  22.56 6.083 24 6.133 ;
     RECT  22.536 6.133 24 7.139 ;
     RECT  53.88 6.277 54.912 6.899 ;
     RECT  54.936 6.277 56.4 6.899 ;
     RECT  59.256 6.323 60.264 7.381 ;
     RECT  36.888 6.371 37.176 6.469 ;
     RECT  31.992 6.565 33.456 6.709 ;
     RECT  57.096 6.805 58.608 8.195 ;
     RECT  22.704 7.139 24 8.437 ;
     RECT  13.512 7.187 16.128 7.813 ;
     RECT  59.256 7.381 60.432 8.003 ;
     RECT  31.992 7.475 33.456 7.667 ;
     RECT  13.512 7.813 14.832 10.595 ;
     RECT  14.856 7.813 16.128 10.549 ;
     RECT  6.312 7.861 7.8 8.483 ;
     RECT  45.912 7.907 46.392 9.013 ;
     RECT  22.728 8.437 24 9.539 ;
     RECT  5.928 8.483 6.216 9.781 ;
     RECT  41.016 8.485 42.384 8.627 ;
     RECT  8.856 9.061 10.224 9.587 ;
     RECT  56.256 9.251 56.4 9.637 ;
     RECT  49.08 9.493 50.112 9.539 ;
     RECT  8.856 9.587 9.624 10.645 ;
     RECT  43.56 9.637 44.88 12.035 ;
     RECT  53.88 9.637 54.96 12.179 ;
     RECT  54.984 9.637 56.4 12.179 ;
     RECT  19.992 9.923 20.136 10.309 ;
     RECT  29.712 10.021 30.864 11.459 ;
     RECT  30.888 10.067 31.608 11.029 ;
     RECT  19.992 10.309 21.024 10.739 ;
     RECT  12.024 10.501 13.2 12.323 ;
     RECT  30.888 11.029 31.92 11.459 ;
     RECT  31.944 11.029 33.456 12.563 ;
     RECT  16.872 11.173 18.192 13.523 ;
     RECT  33.48 11.219 34.8 16.501 ;
     RECT  51.72 11.219 52.992 11.459 ;
     RECT  37.032 11.221 38.064 11.939 ;
     RECT  38.088 11.221 39.456 11.939 ;
     RECT  29.712 11.459 31.92 11.509 ;
     RECT  29.712 11.509 30.816 13.667 ;
     RECT  30.84 11.509 31.92 12.563 ;
     RECT  39.168 11.939 39.456 11.941 ;
     RECT  46.008 11.941 47.088 13.427 ;
     RECT  47.112 11.941 48.432 13.043 ;
     RECT  53.88 12.179 56.4 12.517 ;
     RECT  40.512 12.517 41.568 13.091 ;
     RECT  53.88 12.517 55.008 14.099 ;
     RECT  55.032 12.517 56.4 14.099 ;
     RECT  59.736 12.517 61.248 13.571 ;
     RECT  30.84 12.563 33.456 13.045 ;
     RECT  30.84 13.045 32.208 13.667 ;
     RECT  32.232 13.045 33.456 14.291 ;
     RECT  45.912 13.427 47.088 15.349 ;
     RECT  57.096 13.621 58.128 16.595 ;
     RECT  53.88 14.099 56.4 14.437 ;
     RECT  49.416 14.197 50.88 16.259 ;
     RECT  33.072 14.291 33.456 15.349 ;
     RECT  53.88 14.437 55.776 14.627 ;
     RECT  53.88 14.627 54.696 14.773 ;
     RECT  54.456 14.773 54.696 15.157 ;
     RECT  51.312 15.013 52.704 16.547 ;
     RECT  52.728 15.013 53.856 16.547 ;
     RECT  16.152 15.205 17.376 17.123 ;
     RECT  15.096 15.443 16.128 16.405 ;
     RECT  13.608 16.117 15.072 16.595 ;
     RECT  50.64 16.259 50.88 16.547 ;
     RECT  27.336 16.405 28.512 18.659 ;
     RECT  50.64 16.547 51 17.605 ;
     RECT  44.928 16.595 44.976 16.885 ;
     RECT  45.912 16.835 47.088 19.621 ;
     RECT  43.512 16.885 44.976 18.133 ;
     RECT  29.712 17.075 30.408 18.181 ;
     RECT  20.424 17.413 21.888 18.275 ;
     RECT  43.512 18.133 44.544 20.389 ;
     RECT  47.256 18.181 48.432 19.907 ;
     RECT  55.272 18.229 56.4 18.803 ;
     RECT  20.424 18.275 21.72 18.517 ;
     RECT  20.472 18.517 21.72 18.709 ;
     RECT  33.48 18.707 34.8 34.883 ;
     RECT  20.472 18.709 21.696 21.155 ;
     RECT  54.792 18.803 56.4 19.523 ;
     RECT  29.712 19.091 30.816 19.139 ;
     RECT  56.304 19.523 56.4 19.861 ;
     RECT  45.912 19.621 47.04 21.971 ;
     RECT  24.312 20.579 24.504 21.925 ;
     RECT  12.024 21.013 13.2 21.925 ;
     RECT  17.208 21.109 18.192 21.971 ;
     RECT  53.712 21.539 53.856 22.741 ;
     RECT  49.608 21.923 50.688 23.315 ;
     RECT  36.84 21.971 37.08 23.365 ;
     RECT  45.912 21.971 47.088 23.845 ;
     RECT  40.632 22.741 42.048 23.075 ;
     RECT  42.072 22.741 43.344 23.267 ;
     RECT  59.784 22.789 61.248 25.093 ;
     RECT  29.712 23.125 30.72 24.227 ;
     RECT  42.072 23.267 43.488 24.803 ;
     RECT  49.968 23.315 50.688 23.365 ;
     RECT  36.84 23.365 38.16 24.373 ;
     RECT  38.184 23.365 39.456 24.563 ;
     RECT  44.328 23.411 45.6 23.459 ;
     RECT  49.968 24.131 50.688 24.563 ;
     RECT  47.256 24.469 48.288 26.243 ;
     RECT  35.736 24.515 36.816 29.795 ;
     RECT  39.312 24.563 39.456 25.045 ;
     RECT  49.968 24.563 51 25.285 ;
     RECT  53.88 24.661 55.344 27.733 ;
     RECT  16.68 24.805 18.192 26.243 ;
     RECT  59.784 25.093 61.056 25.715 ;
     RECT  6.216 25.237 7.68 26.293 ;
     RECT  48.312 25.285 49.632 26.243 ;
     RECT  49.656 25.285 51 26.243 ;
     RECT  59.784 25.715 61.248 26.291 ;
     RECT  26.832 25.859 26.856 27.301 ;
     RECT  6.216 26.293 7.632 27.301 ;
     RECT  45.912 26.819 47.088 32.437 ;
     RECT  37.464 27.733 38.784 28.453 ;
     RECT  54.216 27.733 55.344 29.123 ;
     RECT  59.832 27.973 61.248 29.027 ;
     RECT  13.104 28.163 13.2 29.365 ;
     RECT  16.056 28.405 17.232 28.595 ;
     RECT  37.464 28.453 38.496 30.229 ;
     RECT  31.608 29.029 33.12 30.323 ;
     RECT  23.424 29.123 24 29.653 ;
     RECT  53.88 29.123 55.344 34.645 ;
     RECT  6.216 29.459 7.632 39.923 ;
     RECT  51.312 29.605 52.752 30.851 ;
     RECT  22.728 29.653 24 30.995 ;
     RECT  52.776 29.699 53.856 30.851 ;
     RECT  35.544 29.795 36.816 32.437 ;
     RECT  31.728 30.323 33.12 31.669 ;
     RECT  47.256 30.323 48.48 31.379 ;
     RECT  5.088 30.851 5.664 31.861 ;
     RECT  51.312 30.851 53.856 31.141 ;
     RECT  59.256 30.947 59.64 31.909 ;
     RECT  20.472 30.949 21.696 32.771 ;
     RECT  51.312 31.141 52.8 33.299 ;
     RECT  52.824 31.141 53.856 33.299 ;
     RECT  24.456 31.189 25.728 33.589 ;
     RECT  44.472 31.285 45.6 34.595 ;
     RECT  31.752 31.669 33.12 31.907 ;
     RECT  2.904 31.861 4.176 32.771 ;
     RECT  4.2 31.861 5.664 32.819 ;
     RECT  31.752 31.907 33.456 32.723 ;
     RECT  59.256 31.909 60.48 33.251 ;
     RECT  17.016 32.341 18.192 33.013 ;
     RECT  33.264 32.723 33.456 33.013 ;
     RECT  2.712 32.771 4.176 34.501 ;
     RECT  25.752 32.917 26.976 34.211 ;
     RECT  17.112 33.013 18.192 33.155 ;
     RECT  59.256 33.251 61.248 33.539 ;
     RECT  59.256 33.539 59.976 34.741 ;
     RECT  8.112 33.541 9.36 37.091 ;
     RECT  24.648 33.589 25.728 35.893 ;
     RECT  35.112 33.683 36.816 34.645 ;
     RECT  18.912 34.499 19.968 38.773 ;
     RECT  3.096 34.501 4.176 35.699 ;
     RECT  22.056 34.741 23.184 35.077 ;
     RECT  33.432 34.883 34.8 35.315 ;
     RECT  19.992 35.027 20.472 36.469 ;
     RECT  22.2 35.077 23.184 36.517 ;
     RECT  22.032 35.123 22.176 36.469 ;
     RECT  4.2 35.317 5.328 35.653 ;
     RECT  59.976 35.317 61.296 35.411 ;
     RECT  3.096 35.699 4.512 36.275 ;
     RECT  53.88 35.699 55.344 35.843 ;
     RECT  11.688 36.133 13.2 37.091 ;
     RECT  29.712 36.325 30.768 36.755 ;
     RECT  19.992 36.469 21.312 40.019 ;
     RECT  25.752 36.469 26.736 37.667 ;
     RECT  46.008 36.515 47.088 38.723 ;
     RECT  57.768 36.757 59.232 37.043 ;
     RECT  24.456 36.947 25.728 40.405 ;
     RECT  17.112 36.997 18.192 37.333 ;
     RECT  35.112 37.045 36.528 39.829 ;
     RECT  8.112 37.091 9.552 39.877 ;
     RECT  38.568 37.091 40.08 38.483 ;
     RECT  23.04 37.331 24 38.197 ;
     RECT  44.424 38.149 45.6 38.723 ;
     RECT  17.112 38.195 18.192 38.531 ;
     RECT  21.336 38.197 22.848 39.731 ;
     RECT  22.872 38.197 24 39.731 ;
     RECT  17.112 38.531 18.6 39.443 ;
     RECT  45.912 38.723 47.088 39.011 ;
     RECT  36.888 38.725 38.208 40.595 ;
     RECT  51.312 38.725 52.368 42.133 ;
     RECT  13.608 39.059 13.704 40.453 ;
     RECT  17.856 39.443 18.6 40.789 ;
     RECT  18.912 39.635 19.968 40.019 ;
     RECT  21.336 39.731 24 40.261 ;
     RECT  8.112 39.877 9.408 42.131 ;
     RECT  21.336 40.261 22.8 41.795 ;
     RECT  22.824 40.261 24 41.795 ;
     RECT  5.112 40.405 6.192 41.411 ;
     RECT  24.456 40.405 25.536 40.691 ;
     RECT  38.568 40.549 39.648 42.325 ;
     RECT  24.312 40.691 25.536 44.099 ;
     RECT  35.496 41.075 36.528 42.517 ;
     RECT  27.912 41.797 29.4 42.709 ;
     RECT  8.112 42.131 10.224 42.421 ;
     RECT  57.528 42.131 57.672 42.709 ;
     RECT  8.112 42.421 9.12 44.965 ;
     RECT  9.144 42.421 10.224 44.437 ;
     RECT  57.528 42.709 59.04 43.813 ;
     RECT  2.712 42.755 3 44.245 ;
     RECT  18.912 42.755 19.704 43.861 ;
     RECT  35.496 42.755 36.864 46.787 ;
     RECT  51.312 42.803 52.368 45.637 ;
     RECT  45.912 43.093 47.184 45.013 ;
     RECT  33.768 43.141 34.8 44.677 ;
     RECT  27.936 43.715 28.464 45.205 ;
     RECT  10.248 43.813 11.28 44.053 ;
     RECT  11.304 43.813 12.48 44.101 ;
     RECT  57.528 43.813 58.704 43.861 ;
     RECT  18.912 43.861 20.544 44.245 ;
     RECT  36.888 43.861 38.16 45.445 ;
     RECT  41.352 43.861 42.432 46.117 ;
     RECT  24.312 44.099 25.56 45.493 ;
     RECT  18.912 44.245 20.4 46.357 ;
     RECT  9.24 44.437 10.224 45.541 ;
     RECT  43.752 44.437 45.024 45.299 ;
     RECT  52.44 44.869 53.472 47.173 ;
     RECT  2.712 44.915 3 46.117 ;
     RECT  46.056 45.013 47.184 46.549 ;
     RECT  36.888 45.445 37.92 46.787 ;
     RECT  24.312 45.493 25.776 45.685 ;
     RECT  26.472 45.493 27.936 46.069 ;
     RECT  60.408 45.541 61.8 47.315 ;
     RECT  24.312 45.685 25.728 46.645 ;
     RECT  51.312 45.971 52.368 47.269 ;
     RECT  2.712 46.117 4.128 46.883 ;
     RECT  18.912 46.357 20.16 47.269 ;
     RECT  24.312 46.645 25.584 46.693 ;
     RECT  24.312 46.693 25.344 47.845 ;
     RECT  29.712 46.693 31.008 47.315 ;
     RECT  35.352 46.787 36.864 46.883 ;
     RECT  2.712 46.883 5.088 47.027 ;
     RECT  11.736 46.883 12.72 48.421 ;
     RECT  2.712 47.027 3.816 48.373 ;
     RECT  33.336 47.173 34.416 47.893 ;
     RECT  18.912 47.269 19.968 48.515 ;
     RECT  60.816 47.315 61.8 48.805 ;
     RECT  2.712 48.373 3.792 49.043 ;
     RECT  33.336 48.467 34.416 49.091 ;
     RECT  14.136 48.901 15.408 50.243 ;
     RECT  48.984 49.571 49.968 50.195 ;
     RECT  60.816 49.571 61.8 50.677 ;
     RECT  11.736 49.619 12.72 50.195 ;
     RECT  29.712 49.861 30.72 50.723 ;
     RECT  18.912 50.101 20.256 51.347 ;
     RECT  20.28 50.101 21.744 51.347 ;
     RECT  11.64 50.195 12.72 50.243 ;
     RECT  48.984 50.195 50.016 51.205 ;
     RECT  27.384 50.579 28.8 50.867 ;
     RECT  60.6 50.677 61.8 51.395 ;
     RECT  24.552 50.771 25.584 50.819 ;
     RECT  46.824 50.771 47.808 51.829 ;
     RECT  24.552 50.819 25.632 53.939 ;
     RECT  54.456 51.059 55.44 51.347 ;
     RECT  9.816 51.347 10.848 51.395 ;
     RECT  9.432 51.395 10.848 51.875 ;
     RECT  7.92 51.849 8.928 51.863 ;
     RECT  7.416 51.863 8.928 52.499 ;
     RECT  51.816 53.075 53.232 53.891 ;
     RECT  51.768 53.891 53.232 53.939 ;
  END
END ot_hgi_idx_ix2_lane
END LIBRARY
